VERSION 5.8 ;
BUSBITCHARS "[]" ;
DIVIDERCHAR "/" ;
UNITS
    DATABASE MICRONS 1000 ;
END UNITS

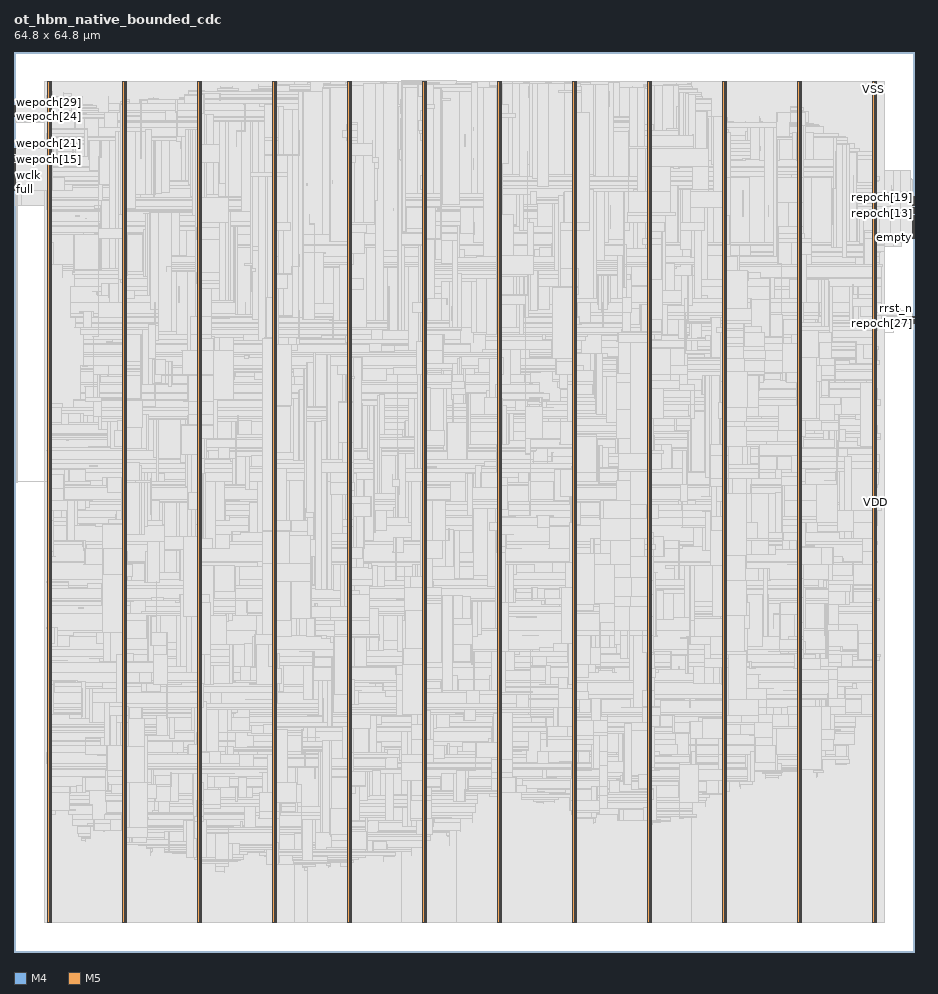
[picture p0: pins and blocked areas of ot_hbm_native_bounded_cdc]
MACRO ot_hbm_native_bounded_cdc
  FOREIGN ot_hbm_native_bounded_cdc 0 0 ;
  CLASS BLOCK ;
  SIZE 64.8 BY 64.8 ;
  PIN empty
    DIRECTION OUTPUT ;
    USE SIGNAL ;
    PORT
      LAYER M4 ;
        RECT  64.716 51.408 64.8 51.432 ;
    END
  END empty
  PIN full
    DIRECTION OUTPUT ;
    USE SIGNAL ;
    PORT
      LAYER M4 ;
        RECT  0 54.864 0.084 54.888 ;
    END
  END full
  PIN r_fault
    DIRECTION OUTPUT ;
    USE SIGNAL ;
    PORT
      LAYER M4 ;
        RECT  64.716 51.504 64.8 51.528 ;
    END
  END r_fault
  PIN rclk
    DIRECTION INPUT ;
    USE SIGNAL ;
    PORT
      LAYER M4 ;
        RECT  64.716 51.6 64.8 51.624 ;
    END
  END rclk
  PIN rd_freed[0]
    DIRECTION OUTPUT ;
    USE SIGNAL ;
    PORT
      LAYER M4 ;
        RECT  0 54.96 0.084 54.984 ;
    END
  END rd_freed[0]
  PIN rd_freed[1]
    DIRECTION OUTPUT ;
    USE SIGNAL ;
    PORT
      LAYER M4 ;
        RECT  0 55.056 0.084 55.08 ;
    END
  END rd_freed[1]
  PIN rd_freed[2]
    DIRECTION OUTPUT ;
    USE SIGNAL ;
    PORT
      LAYER M4 ;
        RECT  0 55.152 0.084 55.176 ;
    END
  END rd_freed[2]
  PIN rdata[0]
    DIRECTION OUTPUT ;
    USE SIGNAL ;
    PORT
      LAYER M4 ;
        RECT  64.716 51.696 64.8 51.72 ;
    END
  END rdata[0]
  PIN re
    DIRECTION INPUT ;
    USE SIGNAL ;
    PORT
      LAYER M4 ;
        RECT  64.716 51.792 64.8 51.816 ;
    END
  END re
  PIN repoch[0]
    DIRECTION INPUT ;
    USE SIGNAL ;
    PORT
      LAYER M4 ;
        RECT  64.716 51.888 64.8 51.912 ;
    END
  END repoch[0]
  PIN repoch[10]
    DIRECTION INPUT ;
    USE SIGNAL ;
    PORT
      LAYER M4 ;
        RECT  64.716 52.848 64.8 52.872 ;
    END
  END repoch[10]
  PIN repoch[11]
    DIRECTION INPUT ;
    USE SIGNAL ;
    PORT
      LAYER M4 ;
        RECT  64.716 52.944 64.8 52.968 ;
    END
  END repoch[11]
  PIN repoch[12]
    DIRECTION INPUT ;
    USE SIGNAL ;
    PORT
      LAYER M4 ;
        RECT  64.716 53.04 64.8 53.064 ;
    END
  END repoch[12]
  PIN repoch[13]
    DIRECTION INPUT ;
    USE SIGNAL ;
    PORT
      LAYER M4 ;
        RECT  64.716 53.136 64.8 53.16 ;
    END
  END repoch[13]
  PIN repoch[14]
    DIRECTION INPUT ;
    USE SIGNAL ;
    PORT
      LAYER M4 ;
        RECT  64.716 53.232 64.8 53.256 ;
    END
  END repoch[14]
  PIN repoch[15]
    DIRECTION INPUT ;
    USE SIGNAL ;
    PORT
      LAYER M4 ;
        RECT  64.716 53.328 64.8 53.352 ;
    END
  END repoch[15]
  PIN repoch[16]
    DIRECTION INPUT ;
    USE SIGNAL ;
    PORT
      LAYER M4 ;
        RECT  64.716 53.424 64.8 53.448 ;
    END
  END repoch[16]
  PIN repoch[17]
    DIRECTION INPUT ;
    USE SIGNAL ;
    PORT
      LAYER M4 ;
        RECT  64.716 53.52 64.8 53.544 ;
    END
  END repoch[17]
  PIN repoch[18]
    DIRECTION INPUT ;
    USE SIGNAL ;
    PORT
      LAYER M4 ;
        RECT  64.716 53.616 64.8 53.64 ;
    END
  END repoch[18]
  PIN repoch[19]
    DIRECTION INPUT ;
    USE SIGNAL ;
    PORT
      LAYER M4 ;
        RECT  64.716 53.712 64.8 53.736 ;
    END
  END repoch[19]
  PIN repoch[1]
    DIRECTION INPUT ;
    USE SIGNAL ;
    PORT
      LAYER M4 ;
        RECT  64.716 51.984 64.8 52.008 ;
    END
  END repoch[1]
  PIN repoch[20]
    DIRECTION INPUT ;
    USE SIGNAL ;
    PORT
      LAYER M4 ;
        RECT  64.716 53.808 64.8 53.832 ;
    END
  END repoch[20]
  PIN repoch[21]
    DIRECTION INPUT ;
    USE SIGNAL ;
    PORT
      LAYER M4 ;
        RECT  64.716 53.904 64.8 53.928 ;
    END
  END repoch[21]
  PIN repoch[22]
    DIRECTION INPUT ;
    USE SIGNAL ;
    PORT
      LAYER M4 ;
        RECT  64.716 54 64.8 54.024 ;
    END
  END repoch[22]
  PIN repoch[23]
    DIRECTION INPUT ;
    USE SIGNAL ;
    PORT
      LAYER M4 ;
        RECT  64.716 54.096 64.8 54.12 ;
    END
  END repoch[23]
  PIN repoch[24]
    DIRECTION INPUT ;
    USE SIGNAL ;
    PORT
      LAYER M4 ;
        RECT  64.716 54.192 64.8 54.216 ;
    END
  END repoch[24]
  PIN repoch[25]
    DIRECTION INPUT ;
    USE SIGNAL ;
    PORT
      LAYER M4 ;
        RECT  64.716 54.288 64.8 54.312 ;
    END
  END repoch[25]
  PIN repoch[26]
    DIRECTION INPUT ;
    USE SIGNAL ;
    PORT
      LAYER M4 ;
        RECT  64.716 54.384 64.8 54.408 ;
    END
  END repoch[26]
  PIN repoch[27]
    DIRECTION INPUT ;
    USE SIGNAL ;
    PORT
      LAYER M4 ;
        RECT  64.716 45.264 64.8 45.288 ;
    END
  END repoch[27]
  PIN repoch[28]
    DIRECTION INPUT ;
    USE SIGNAL ;
    PORT
      LAYER M4 ;
        RECT  64.716 45.36 64.8 45.384 ;
    END
  END repoch[28]
  PIN repoch[29]
    DIRECTION INPUT ;
    USE SIGNAL ;
    PORT
      LAYER M4 ;
        RECT  64.716 45.456 64.8 45.48 ;
    END
  END repoch[29]
  PIN repoch[2]
    DIRECTION INPUT ;
    USE SIGNAL ;
    PORT
      LAYER M4 ;
        RECT  64.716 52.08 64.8 52.104 ;
    END
  END repoch[2]
  PIN repoch[30]
    DIRECTION INPUT ;
    USE SIGNAL ;
    PORT
      LAYER M4 ;
        RECT  64.716 45.552 64.8 45.576 ;
    END
  END repoch[30]
  PIN repoch[31]
    DIRECTION INPUT ;
    USE SIGNAL ;
    PORT
      LAYER M4 ;
        RECT  64.716 45.648 64.8 45.672 ;
    END
  END repoch[31]
  PIN repoch[3]
    DIRECTION INPUT ;
    USE SIGNAL ;
    PORT
      LAYER M4 ;
        RECT  64.716 52.176 64.8 52.2 ;
    END
  END repoch[3]
  PIN repoch[4]
    DIRECTION INPUT ;
    USE SIGNAL ;
    PORT
      LAYER M4 ;
        RECT  64.716 52.272 64.8 52.296 ;
    END
  END repoch[4]
  PIN repoch[5]
    DIRECTION INPUT ;
    USE SIGNAL ;
    PORT
      LAYER M4 ;
        RECT  64.716 52.368 64.8 52.392 ;
    END
  END repoch[5]
  PIN repoch[6]
    DIRECTION INPUT ;
    USE SIGNAL ;
    PORT
      LAYER M4 ;
        RECT  64.716 52.464 64.8 52.488 ;
    END
  END repoch[6]
  PIN repoch[7]
    DIRECTION INPUT ;
    USE SIGNAL ;
    PORT
      LAYER M4 ;
        RECT  64.716 52.56 64.8 52.584 ;
    END
  END repoch[7]
  PIN repoch[8]
    DIRECTION INPUT ;
    USE SIGNAL ;
    PORT
      LAYER M4 ;
        RECT  64.716 52.656 64.8 52.68 ;
    END
  END repoch[8]
  PIN repoch[9]
    DIRECTION INPUT ;
    USE SIGNAL ;
    PORT
      LAYER M4 ;
        RECT  64.716 52.752 64.8 52.776 ;
    END
  END repoch[9]
  PIN rrst_n
    DIRECTION INPUT ;
    USE SIGNAL ;
    PORT
      LAYER M4 ;
        RECT  64.716 45.744 64.8 45.768 ;
    END
  END rrst_n
  PIN w_fault
    DIRECTION OUTPUT ;
    USE SIGNAL ;
    PORT
      LAYER M4 ;
        RECT  0 55.248 0.084 55.272 ;
    END
  END w_fault
  PIN wclk
    DIRECTION INPUT ;
    USE SIGNAL ;
    PORT
      LAYER M4 ;
        RECT  0 55.344 0.084 55.368 ;
    END
  END wclk
  PIN wdata[0]
    DIRECTION INPUT ;
    USE SIGNAL ;
    PORT
      LAYER M4 ;
        RECT  0 55.44 0.084 55.464 ;
    END
  END wdata[0]
  PIN we
    DIRECTION INPUT ;
    USE SIGNAL ;
    PORT
      LAYER M4 ;
        RECT  0 55.536 0.084 55.56 ;
    END
  END we
  PIN wepoch[0]
    DIRECTION INPUT ;
    USE SIGNAL ;
    PORT
      LAYER M4 ;
        RECT  0 55.632 0.084 55.656 ;
    END
  END wepoch[0]
  PIN wepoch[10]
    DIRECTION INPUT ;
    USE SIGNAL ;
    PORT
      LAYER M4 ;
        RECT  0 56.592 0.084 56.616 ;
    END
  END wepoch[10]
  PIN wepoch[11]
    DIRECTION INPUT ;
    USE SIGNAL ;
    PORT
      LAYER M4 ;
        RECT  0 56.688 0.084 56.712 ;
    END
  END wepoch[11]
  PIN wepoch[12]
    DIRECTION INPUT ;
    USE SIGNAL ;
    PORT
      LAYER M4 ;
        RECT  0 56.784 0.084 56.808 ;
    END
  END wepoch[12]
  PIN wepoch[13]
    DIRECTION INPUT ;
    USE SIGNAL ;
    PORT
      LAYER M4 ;
        RECT  0 56.88 0.084 56.904 ;
    END
  END wepoch[13]
  PIN wepoch[14]
    DIRECTION INPUT ;
    USE SIGNAL ;
    PORT
      LAYER M4 ;
        RECT  0 56.976 0.084 57 ;
    END
  END wepoch[14]
  PIN wepoch[15]
    DIRECTION INPUT ;
    USE SIGNAL ;
    PORT
      LAYER M4 ;
        RECT  0 57.072 0.084 57.096 ;
    END
  END wepoch[15]
  PIN wepoch[16]
    DIRECTION INPUT ;
    USE SIGNAL ;
    PORT
      LAYER M4 ;
        RECT  0 57.168 0.084 57.192 ;
    END
  END wepoch[16]
  PIN wepoch[17]
    DIRECTION INPUT ;
    USE SIGNAL ;
    PORT
      LAYER M4 ;
        RECT  0 57.264 0.084 57.288 ;
    END
  END wepoch[17]
  PIN wepoch[18]
    DIRECTION INPUT ;
    USE SIGNAL ;
    PORT
      LAYER M4 ;
        RECT  0 57.36 0.084 57.384 ;
    END
  END wepoch[18]
  PIN wepoch[19]
    DIRECTION INPUT ;
    USE SIGNAL ;
    PORT
      LAYER M4 ;
        RECT  0 57.456 0.084 57.48 ;
    END
  END wepoch[19]
  PIN wepoch[1]
    DIRECTION INPUT ;
    USE SIGNAL ;
    PORT
      LAYER M4 ;
        RECT  0 55.728 0.084 55.752 ;
    END
  END wepoch[1]
  PIN wepoch[20]
    DIRECTION INPUT ;
    USE SIGNAL ;
    PORT
      LAYER M4 ;
        RECT  0 57.552 0.084 57.576 ;
    END
  END wepoch[20]
  PIN wepoch[21]
    DIRECTION INPUT ;
    USE SIGNAL ;
    PORT
      LAYER M4 ;
        RECT  0 57.648 0.084 57.672 ;
    END
  END wepoch[21]
  PIN wepoch[22]
    DIRECTION INPUT ;
    USE SIGNAL ;
    PORT
      LAYER M4 ;
        RECT  0 57.744 0.084 57.768 ;
    END
  END wepoch[22]
  PIN wepoch[23]
    DIRECTION INPUT ;
    USE SIGNAL ;
    PORT
      LAYER M4 ;
        RECT  0 57.84 0.084 57.864 ;
    END
  END wepoch[23]
  PIN wepoch[24]
    DIRECTION INPUT ;
    USE SIGNAL ;
    PORT
      LAYER M4 ;
        RECT  0 60.144 0.084 60.168 ;
    END
  END wepoch[24]
  PIN wepoch[25]
    DIRECTION INPUT ;
    USE SIGNAL ;
    PORT
      LAYER M4 ;
        RECT  0 60.24 0.084 60.264 ;
    END
  END wepoch[25]
  PIN wepoch[26]
    DIRECTION INPUT ;
    USE SIGNAL ;
    PORT
      LAYER M4 ;
        RECT  0 60.336 0.084 60.36 ;
    END
  END wepoch[26]
  PIN wepoch[27]
    DIRECTION INPUT ;
    USE SIGNAL ;
    PORT
      LAYER M4 ;
        RECT  0 60.432 0.084 60.456 ;
    END
  END wepoch[27]
  PIN wepoch[28]
    DIRECTION INPUT ;
    USE SIGNAL ;
    PORT
      LAYER M4 ;
        RECT  0 60.528 0.084 60.552 ;
    END
  END wepoch[28]
  PIN wepoch[29]
    DIRECTION INPUT ;
    USE SIGNAL ;
    PORT
      LAYER M4 ;
        RECT  0 60.624 0.084 60.648 ;
    END
  END wepoch[29]
  PIN wepoch[2]
    DIRECTION INPUT ;
    USE SIGNAL ;
    PORT
      LAYER M4 ;
        RECT  0 55.824 0.084 55.848 ;
    END
  END wepoch[2]
  PIN wepoch[30]
    DIRECTION INPUT ;
    USE SIGNAL ;
    PORT
      LAYER M4 ;
        RECT  0 60.72 0.084 60.744 ;
    END
  END wepoch[30]
  PIN wepoch[31]
    DIRECTION INPUT ;
    USE SIGNAL ;
    PORT
      LAYER M4 ;
        RECT  0 60.816 0.084 60.84 ;
    END
  END wepoch[31]
  PIN wepoch[3]
    DIRECTION INPUT ;
    USE SIGNAL ;
    PORT
      LAYER M4 ;
        RECT  0 55.92 0.084 55.944 ;
    END
  END wepoch[3]
  PIN wepoch[4]
    DIRECTION INPUT ;
    USE SIGNAL ;
    PORT
      LAYER M4 ;
        RECT  0 56.016 0.084 56.04 ;
    END
  END wepoch[4]
  PIN wepoch[5]
    DIRECTION INPUT ;
    USE SIGNAL ;
    PORT
      LAYER M4 ;
        RECT  0 56.112 0.084 56.136 ;
    END
  END wepoch[5]
  PIN wepoch[6]
    DIRECTION INPUT ;
    USE SIGNAL ;
    PORT
      LAYER M4 ;
        RECT  0 56.208 0.084 56.232 ;
    END
  END wepoch[6]
  PIN wepoch[7]
    DIRECTION INPUT ;
    USE SIGNAL ;
    PORT
      LAYER M4 ;
        RECT  0 56.304 0.084 56.328 ;
    END
  END wepoch[7]
  PIN wepoch[8]
    DIRECTION INPUT ;
    USE SIGNAL ;
    PORT
      LAYER M4 ;
        RECT  0 56.4 0.084 56.424 ;
    END
  END wepoch[8]
  PIN wepoch[9]
    DIRECTION INPUT ;
    USE SIGNAL ;
    PORT
      LAYER M4 ;
        RECT  0 56.496 0.084 56.52 ;
    END
  END wepoch[9]
  PIN wrst_n
    DIRECTION INPUT ;
    USE SIGNAL ;
    PORT
      LAYER M4 ;
        RECT  0 60.912 0.084 60.936 ;
    END
  END wrst_n
  PIN VDD
    DIRECTION INOUT ;
    USE POWER ;
    PORT
      LAYER M5 ;
        RECT  61.992 2.151 62.112 62.649 ;
        RECT  56.592 2.151 56.712 62.649 ;
        RECT  51.192 2.151 51.312 62.649 ;
        RECT  45.792 2.151 45.912 62.649 ;
        RECT  40.392 2.151 40.512 62.649 ;
        RECT  34.992 2.151 35.112 62.649 ;
        RECT  29.592 2.151 29.712 62.649 ;
        RECT  24.192 2.151 24.312 62.649 ;
        RECT  18.792 2.151 18.912 62.649 ;
        RECT  13.392 2.151 13.512 62.649 ;
        RECT  7.992 2.151 8.112 62.649 ;
        RECT  2.592 2.151 2.712 62.649 ;
    END
  END VDD
  PIN VSS
    DIRECTION INOUT ;
    USE GROUND ;
    PORT
      LAYER M5 ;
        RECT  61.8 2.137 61.92 62.663 ;
        RECT  56.4 2.137 56.52 62.663 ;
        RECT  51 2.137 51.12 62.663 ;
        RECT  45.6 2.137 45.72 62.663 ;
        RECT  40.2 2.137 40.32 62.663 ;
        RECT  34.8 2.137 34.92 62.663 ;
        RECT  29.4 2.137 29.52 62.663 ;
        RECT  24 2.137 24.12 62.663 ;
        RECT  18.6 2.137 18.72 62.663 ;
        RECT  13.2 2.137 13.32 62.663 ;
        RECT  7.8 2.137 7.92 62.663 ;
        RECT  2.4 2.137 2.52 62.663 ;
    END
  END VSS
  # OT_OBS_CLOSED layer=M5 d_um=1.536 added=353
  OBS
    LAYER RVTN ;
     RECT  2.16 2.16 62.64 2.295 ;
     RECT  2.16 2.565 62.64 2.835 ;
     RECT  2.16 3.105 62.64 3.375 ;
     RECT  2.16 3.645 62.64 3.915 ;
     RECT  2.16 4.185 62.64 4.455 ;
     RECT  2.16 4.725 62.64 4.995 ;
     RECT  2.16 5.265 62.64 5.535 ;
     RECT  2.16 5.805 62.64 6.075 ;
     RECT  2.16 6.345 62.64 6.615 ;
     RECT  2.16 6.885 62.64 7.155 ;
     RECT  2.16 7.425 62.64 7.695 ;
     RECT  2.16 7.965 62.64 8.235 ;
     RECT  2.16 8.505 62.64 8.775 ;
     RECT  2.16 9.045 62.64 9.315 ;
     RECT  2.16 9.585 62.64 9.855 ;
     RECT  2.16 10.125 62.64 10.395 ;
     RECT  2.16 10.665 62.64 10.935 ;
     RECT  2.16 11.205 62.64 11.475 ;
     RECT  2.16 11.745 62.64 12.015 ;
     RECT  2.16 12.285 62.64 12.555 ;
     RECT  2.16 12.825 62.64 13.095 ;
     RECT  2.16 13.365 62.64 13.635 ;
     RECT  2.16 13.905 62.64 14.175 ;
     RECT  2.16 14.445 62.64 14.715 ;
     RECT  2.16 14.985 62.64 15.255 ;
     RECT  2.16 15.525 62.64 15.795 ;
     RECT  2.16 16.065 62.64 16.335 ;
     RECT  2.16 16.605 62.64 16.875 ;
     RECT  2.16 17.145 62.64 17.415 ;
     RECT  2.16 17.685 62.64 17.955 ;
     RECT  2.16 18.225 62.64 18.495 ;
     RECT  2.16 18.765 62.64 19.035 ;
     RECT  2.16 19.305 62.64 19.575 ;
     RECT  2.16 19.845 62.64 20.115 ;
     RECT  2.16 20.385 62.64 20.655 ;
     RECT  2.16 20.925 62.64 21.195 ;
     RECT  2.16 21.465 62.64 21.735 ;
     RECT  2.16 22.005 62.64 22.275 ;
     RECT  2.16 22.545 62.64 22.815 ;
     RECT  2.16 23.085 62.64 23.355 ;
     RECT  2.16 23.625 62.64 23.895 ;
     RECT  2.16 24.165 62.64 24.435 ;
     RECT  2.16 24.705 62.64 24.975 ;
     RECT  2.16 25.245 62.64 25.515 ;
     RECT  2.16 25.785 62.64 26.055 ;
     RECT  2.16 26.325 62.64 26.595 ;
     RECT  2.16 26.865 62.64 27.135 ;
     RECT  2.16 27.405 62.64 27.675 ;
     RECT  2.16 27.945 62.64 28.215 ;
     RECT  2.16 28.485 62.64 28.755 ;
     RECT  2.16 29.025 62.64 29.295 ;
     RECT  2.16 29.565 62.64 29.835 ;
     RECT  2.16 30.105 62.64 30.375 ;
     RECT  2.16 30.645 62.64 30.915 ;
     RECT  2.16 31.185 62.64 31.455 ;
     RECT  2.16 31.725 62.64 31.995 ;
     RECT  2.16 32.265 62.64 32.535 ;
     RECT  2.16 32.805 62.64 33.075 ;
     RECT  2.16 33.345 62.64 33.615 ;
     RECT  2.16 33.885 62.64 34.155 ;
     RECT  2.16 34.425 62.64 34.695 ;
     RECT  2.16 34.965 62.64 35.235 ;
     RECT  2.16 35.505 62.64 35.775 ;
     RECT  2.16 36.045 62.64 36.315 ;
     RECT  2.16 36.585 62.64 36.855 ;
     RECT  2.16 37.125 62.64 37.395 ;
     RECT  2.16 37.665 62.64 37.935 ;
     RECT  2.16 38.205 62.64 38.475 ;
     RECT  2.16 38.745 62.64 39.015 ;
     RECT  2.16 39.285 62.64 39.555 ;
     RECT  2.16 39.825 62.64 40.095 ;
     RECT  2.16 40.365 62.64 40.635 ;
     RECT  2.16 40.905 62.64 41.175 ;
     RECT  2.16 41.445 62.64 41.715 ;
     RECT  2.16 41.985 62.64 42.255 ;
     RECT  2.16 42.525 62.64 42.795 ;
     RECT  2.16 43.065 62.64 43.335 ;
     RECT  2.16 43.605 62.64 43.875 ;
     RECT  2.16 44.145 62.64 44.415 ;
     RECT  2.16 44.685 62.64 44.955 ;
     RECT  2.16 45.225 62.64 45.495 ;
     RECT  2.16 45.765 62.64 46.035 ;
     RECT  2.16 46.305 62.64 46.575 ;
     RECT  2.16 46.845 62.64 47.115 ;
     RECT  2.16 47.385 62.64 47.655 ;
     RECT  2.16 47.925 62.64 48.195 ;
     RECT  2.16 48.465 62.64 48.735 ;
     RECT  2.16 49.005 62.64 49.275 ;
     RECT  2.16 49.545 62.64 49.815 ;
     RECT  2.16 50.085 62.64 50.355 ;
     RECT  2.16 50.625 62.64 50.895 ;
     RECT  2.16 51.165 62.64 51.435 ;
     RECT  2.16 51.705 62.64 51.975 ;
     RECT  2.16 52.245 62.64 52.515 ;
     RECT  2.16 52.785 62.64 53.055 ;
     RECT  2.16 53.325 62.64 53.595 ;
     RECT  2.16 53.865 62.64 54.135 ;
     RECT  2.16 54.405 62.64 54.675 ;
     RECT  2.16 54.945 62.64 55.215 ;
     RECT  2.16 55.485 62.64 55.755 ;
     RECT  2.16 56.025 62.64 56.295 ;
     RECT  2.16 56.565 62.64 56.835 ;
     RECT  2.16 57.105 62.64 57.375 ;
     RECT  2.16 57.645 62.64 57.915 ;
     RECT  2.16 58.185 62.64 58.455 ;
     RECT  2.16 58.725 62.64 58.995 ;
     RECT  2.16 59.265 62.64 59.535 ;
     RECT  2.16 59.805 62.64 60.075 ;
     RECT  2.16 60.345 62.64 60.615 ;
     RECT  2.16 60.885 62.64 61.155 ;
     RECT  2.16 61.425 62.64 61.695 ;
     RECT  2.16 61.965 62.64 62.235 ;
     RECT  2.16 62.505 62.64 62.64 ;
    LAYER RVTP ;
     RECT  2.16 2.295 62.64 2.565 ;
     RECT  2.16 2.835 62.64 3.105 ;
     RECT  2.16 3.375 62.64 3.645 ;
     RECT  2.16 3.915 62.64 4.185 ;
     RECT  2.16 4.455 62.64 4.725 ;
     RECT  2.16 4.995 62.64 5.265 ;
     RECT  2.16 5.535 62.64 5.805 ;
     RECT  2.16 6.075 62.64 6.345 ;
     RECT  2.16 6.615 62.64 6.885 ;
     RECT  2.16 7.155 62.64 7.425 ;
     RECT  2.16 7.695 62.64 7.965 ;
     RECT  2.16 8.235 62.64 8.505 ;
     RECT  2.16 8.775 62.64 9.045 ;
     RECT  2.16 9.315 62.64 9.585 ;
     RECT  2.16 9.855 62.64 10.125 ;
     RECT  2.16 10.395 62.64 10.665 ;
     RECT  2.16 10.935 62.64 11.205 ;
     RECT  2.16 11.475 62.64 11.745 ;
     RECT  2.16 12.015 62.64 12.285 ;
     RECT  2.16 12.555 62.64 12.825 ;
     RECT  2.16 13.095 62.64 13.365 ;
     RECT  2.16 13.635 62.64 13.905 ;
     RECT  2.16 14.175 62.64 14.445 ;
     RECT  2.16 14.715 62.64 14.985 ;
     RECT  2.16 15.255 62.64 15.525 ;
     RECT  2.16 15.795 62.64 16.065 ;
     RECT  2.16 16.335 62.64 16.605 ;
     RECT  2.16 16.875 62.64 17.145 ;
     RECT  2.16 17.415 62.64 17.685 ;
     RECT  2.16 17.955 62.64 18.225 ;
     RECT  2.16 18.495 62.64 18.765 ;
     RECT  2.16 19.035 62.64 19.305 ;
     RECT  2.16 19.575 62.64 19.845 ;
     RECT  2.16 20.115 62.64 20.385 ;
     RECT  2.16 20.655 62.64 20.925 ;
     RECT  2.16 21.195 62.64 21.465 ;
     RECT  2.16 21.735 62.64 22.005 ;
     RECT  2.16 22.275 62.64 22.545 ;
     RECT  2.16 22.815 62.64 23.085 ;
     RECT  2.16 23.355 62.64 23.625 ;
     RECT  2.16 23.895 62.64 24.165 ;
     RECT  2.16 24.435 62.64 24.705 ;
     RECT  2.16 24.975 62.64 25.245 ;
     RECT  2.16 25.515 62.64 25.785 ;
     RECT  2.16 26.055 62.64 26.325 ;
     RECT  2.16 26.595 62.64 26.865 ;
     RECT  2.16 27.135 62.64 27.405 ;
     RECT  2.16 27.675 62.64 27.945 ;
     RECT  2.16 28.215 62.64 28.485 ;
     RECT  2.16 28.755 62.64 29.025 ;
     RECT  2.16 29.295 62.64 29.565 ;
     RECT  2.16 29.835 62.64 30.105 ;
     RECT  2.16 30.375 62.64 30.645 ;
     RECT  2.16 30.915 62.64 31.185 ;
     RECT  2.16 31.455 62.64 31.725 ;
     RECT  2.16 31.995 62.64 32.265 ;
     RECT  2.16 32.535 62.64 32.805 ;
     RECT  2.16 33.075 62.64 33.345 ;
     RECT  2.16 33.615 62.64 33.885 ;
     RECT  2.16 34.155 62.64 34.425 ;
     RECT  2.16 34.695 62.64 34.965 ;
     RECT  2.16 35.235 62.64 35.505 ;
     RECT  2.16 35.775 62.64 36.045 ;
     RECT  2.16 36.315 62.64 36.585 ;
     RECT  2.16 36.855 62.64 37.125 ;
     RECT  2.16 37.395 62.64 37.665 ;
     RECT  2.16 37.935 62.64 38.205 ;
     RECT  2.16 38.475 62.64 38.745 ;
     RECT  2.16 39.015 62.64 39.285 ;
     RECT  2.16 39.555 62.64 39.825 ;
     RECT  2.16 40.095 62.64 40.365 ;
     RECT  2.16 40.635 62.64 40.905 ;
     RECT  2.16 41.175 62.64 41.445 ;
     RECT  2.16 41.715 62.64 41.985 ;
     RECT  2.16 42.255 62.64 42.525 ;
     RECT  2.16 42.795 62.64 43.065 ;
     RECT  2.16 43.335 62.64 43.605 ;
     RECT  2.16 43.875 62.64 44.145 ;
     RECT  2.16 44.415 62.64 44.685 ;
     RECT  2.16 44.955 62.64 45.225 ;
     RECT  2.16 45.495 62.64 45.765 ;
     RECT  2.16 46.035 62.64 46.305 ;
     RECT  2.16 46.575 62.64 46.845 ;
     RECT  2.16 47.115 62.64 47.385 ;
     RECT  2.16 47.655 62.64 47.925 ;
     RECT  2.16 48.195 62.64 48.465 ;
     RECT  2.16 48.735 62.64 49.005 ;
     RECT  2.16 49.275 62.64 49.545 ;
     RECT  2.16 49.815 62.64 50.085 ;
     RECT  2.16 50.355 62.64 50.625 ;
     RECT  2.16 50.895 62.64 51.165 ;
     RECT  2.16 51.435 62.64 51.705 ;
     RECT  2.16 51.975 62.64 52.245 ;
     RECT  2.16 52.515 62.64 52.785 ;
     RECT  2.16 53.055 62.64 53.325 ;
     RECT  2.16 53.595 62.64 53.865 ;
     RECT  2.16 54.135 62.64 54.405 ;
     RECT  2.16 54.675 62.64 54.945 ;
     RECT  2.16 55.215 62.64 55.485 ;
     RECT  2.16 55.755 62.64 56.025 ;
     RECT  2.16 56.295 62.64 56.565 ;
     RECT  2.16 56.835 62.64 57.105 ;
     RECT  2.16 57.375 62.64 57.645 ;
     RECT  2.16 57.915 62.64 58.185 ;
     RECT  2.16 58.455 62.64 58.725 ;
     RECT  2.16 58.995 62.64 59.265 ;
     RECT  2.16 59.535 62.64 59.805 ;
     RECT  2.16 60.075 62.64 60.345 ;
     RECT  2.16 60.615 62.64 60.885 ;
     RECT  2.16 61.155 62.64 61.425 ;
     RECT  2.16 61.695 62.64 61.965 ;
     RECT  2.16 62.235 62.64 62.505 ;
    LAYER M1 ;
     RECT  2.16 2.151 62.64 62.649 ;
    LAYER M2 ;
     RECT  0.103 53.766 0.139 53.784 ;
     RECT  0.139 53.766 0.175 54.504 ;
     RECT  0.103 55.26 0.175 55.71 ;
     RECT  0.103 57.186 0.239 57.204 ;
     RECT  0.175 53.766 0.535 55.71 ;
     RECT  0.103 59.742 0.535 59.76 ;
     RECT  0.535 53.766 2.16 55.854 ;
     RECT  0.535 59.742 2.16 59.832 ;
     RECT  2.16 2.151 18.931 62.649 ;
     RECT  18.931 2.151 20.219 62.694 ;
     RECT  20.219 2.151 21.127 62.649 ;
     RECT  21.127 2.151 27.931 62.694 ;
     RECT  27.931 2.151 31.883 62.766 ;
     RECT  31.883 2.151 48.803 62.694 ;
     RECT  48.803 2.151 62.64 62.649 ;
     RECT  62.64 50.436 62.699 56.286 ;
     RECT  62.64 45.738 63.239 46.368 ;
     RECT  62.64 44.622 63.311 44.64 ;
     RECT  63.239 45.738 63.311 46.296 ;
     RECT  62.699 50.796 63.311 56.286 ;
     RECT  63.311 46.206 63.851 46.296 ;
     RECT  63.311 51.876 63.851 56.286 ;
     RECT  63.311 50.796 63.887 51.12 ;
     RECT  63.851 52.254 63.887 53.01 ;
     RECT  63.887 50.868 63.923 51.12 ;
     RECT  63.887 52.254 63.923 52.272 ;
     RECT  63.923 51.102 63.959 51.12 ;
     RECT  63.851 54.756 64.535 56.286 ;
     RECT  64.535 54.756 64.607 55.674 ;
     RECT  64.607 54.756 64.643 55.584 ;
     RECT  64.643 55.566 64.679 55.584 ;
     RECT  63.851 46.206 64.715 46.224 ;
     RECT  64.615 51.786 64.715 51.804 ;
     RECT  64.643 54.756 64.715 54.774 ;
    LAYER M3 ;
     RECT  2.415 2.143 2.505 2.413 ;
     RECT  7.815 2.143 7.905 2.413 ;
     RECT  13.215 2.143 13.305 2.413 ;
     RECT  18.615 2.143 18.705 2.413 ;
     RECT  24.015 2.143 24.105 2.413 ;
     RECT  29.415 2.143 29.505 2.413 ;
     RECT  34.815 2.143 34.905 2.413 ;
     RECT  40.215 2.143 40.305 2.413 ;
     RECT  45.615 2.143 45.705 2.413 ;
     RECT  51.015 2.143 51.105 2.413 ;
     RECT  56.415 2.143 56.505 2.413 ;
     RECT  61.815 2.143 61.905 2.413 ;
     RECT  15.12 5.701 15.138 5.773 ;
     RECT  14.652 5.773 15.138 5.809 ;
     RECT  20.916 5.845 20.934 5.881 ;
     RECT  20.916 5.881 21.114 6.115 ;
     RECT  14.508 5.809 15.138 6.151 ;
     RECT  20.772 6.115 21.114 6.151 ;
     RECT  22.608 6.115 22.626 6.151 ;
     RECT  24.015 2.413 24.297 6.151 ;
     RECT  22.608 6.151 22.77 6.241 ;
     RECT  20.772 6.151 21.69 6.277 ;
     RECT  18.615 2.413 18.897 6.283 ;
     RECT  13.215 2.413 13.497 6.349 ;
     RECT  13.176 6.349 13.497 6.385 ;
     RECT  14.472 6.151 15.426 6.385 ;
     RECT  20.124 6.277 21.69 6.385 ;
     RECT  22.5 6.241 22.77 6.385 ;
     RECT  18.216 6.283 18.897 6.421 ;
     RECT  20.124 6.385 22.77 6.421 ;
     RECT  23.508 6.151 24.297 6.421 ;
     RECT  13.176 6.385 15.426 6.511 ;
     RECT  13.176 6.511 16.074 6.583 ;
     RECT  20.124 6.421 24.462 6.619 ;
     RECT  13.176 6.583 16.29 6.691 ;
     RECT  18.216 6.421 19.098 6.691 ;
     RECT  20.052 6.619 24.462 6.691 ;
     RECT  12.996 6.691 16.506 6.781 ;
     RECT  20.052 6.691 24.786 6.781 ;
     RECT  18.18 6.691 19.098 6.889 ;
     RECT  26.568 6.547 26.586 6.889 ;
     RECT  27.396 6.853 27.414 6.889 ;
     RECT  18.036 6.889 19.098 6.925 ;
     RECT  20.052 6.781 25.326 6.925 ;
     RECT  26.568 6.889 27.414 6.925 ;
     RECT  18.036 6.925 25.326 6.961 ;
     RECT  26.568 6.925 27.45 6.961 ;
     RECT  12.42 6.781 16.506 7.003 ;
     RECT  12.42 7.003 16.794 7.087 ;
     RECT  9.792 6.925 9.81 7.159 ;
     RECT  11.376 7.087 16.794 7.159 ;
     RECT  10.836 7.159 16.794 7.189 ;
     RECT  10.836 7.189 16.938 7.195 ;
     RECT  17.676 6.961 27.45 7.195 ;
     RECT  9.792 7.159 9.882 7.231 ;
     RECT  10.836 7.195 27.45 7.231 ;
     RECT  28.584 6.961 28.602 7.231 ;
     RECT  10.836 7.231 28.638 7.349 ;
     RECT  9.792 7.231 9.954 7.465 ;
     RECT  9.54 7.465 9.954 7.501 ;
     RECT  10.836 7.349 21.726 7.501 ;
     RECT  22.5 7.349 28.638 7.501 ;
     RECT  29.415 2.413 29.697 7.501 ;
     RECT  22.5 7.501 29.697 7.529 ;
     RECT  9.54 7.501 21.726 7.663 ;
     RECT  9.036 7.663 21.726 7.699 ;
     RECT  7.815 2.413 8.097 7.771 ;
     RECT  8.964 7.699 21.726 7.771 ;
     RECT  22.824 7.529 29.697 8.005 ;
     RECT  5.112 7.933 5.13 8.041 ;
     RECT  4.86 8.041 5.13 8.203 ;
     RECT  4.86 8.203 5.526 8.239 ;
     RECT  31.32 7.699 31.338 8.239 ;
     RECT  4.824 8.239 5.526 8.311 ;
     RECT  22.824 8.005 30.006 8.311 ;
     RECT  31.32 8.239 31.374 8.311 ;
     RECT  31.212 8.311 31.374 8.401 ;
     RECT  22.788 8.311 30.006 8.437 ;
     RECT  4.608 8.311 5.526 8.545 ;
     RECT  7.815 7.771 21.726 8.581 ;
     RECT  22.788 8.437 30.114 8.581 ;
     RECT  31.14 8.401 31.374 8.581 ;
     RECT  7.776 8.581 31.374 8.609 ;
     RECT  26.136 8.609 31.374 8.699 ;
     RECT  6.408 8.707 6.534 8.779 ;
     RECT  26.244 8.699 31.374 8.779 ;
     RECT  32.112 8.707 32.13 8.779 ;
     RECT  6.264 8.779 6.534 8.851 ;
     RECT  7.776 8.609 25.398 8.851 ;
     RECT  6.264 8.851 25.398 8.969 ;
     RECT  17.388 8.969 25.398 9.005 ;
     RECT  4.536 8.545 5.526 9.013 ;
     RECT  6.264 8.969 16.614 9.013 ;
     RECT  4.536 9.013 16.614 9.121 ;
     RECT  45.615 2.413 45.897 9.211 ;
     RECT  26.244 8.779 32.13 9.319 ;
     RECT  41.724 9.283 41.742 9.355 ;
     RECT  45.615 9.211 45.954 9.355 ;
     RECT  23.976 9.005 25.398 9.391 ;
     RECT  45.615 9.355 46.53 9.391 ;
     RECT  45.615 9.391 47.286 9.499 ;
     RECT  4.212 9.121 16.614 9.509 ;
     RECT  26.244 9.319 32.166 9.589 ;
     RECT  33.012 9.355 33.03 9.589 ;
     RECT  40.215 2.413 40.497 9.625 ;
     RECT  41.724 9.355 41.886 9.625 ;
     RECT  23.976 9.391 25.506 9.643 ;
     RECT  26.244 9.589 33.03 9.643 ;
     RECT  43.56 9.499 43.578 9.661 ;
     RECT  45.18 9.499 47.286 9.661 ;
     RECT  48.204 9.625 48.222 9.661 ;
     RECT  40.215 9.625 41.886 9.691 ;
     RECT  43.56 9.661 47.286 9.751 ;
     RECT  48.204 9.661 49.158 9.751 ;
     RECT  17.388 9.005 23.202 9.823 ;
     RECT  23.976 9.643 33.03 9.823 ;
     RECT  6.516 9.509 16.614 9.887 ;
     RECT  2.415 2.413 2.697 9.895 ;
     RECT  43.56 9.751 49.158 9.923 ;
     RECT  4.212 9.509 5.634 9.931 ;
     RECT  40.215 9.691 41.958 9.931 ;
     RECT  6.588 9.887 16.614 9.959 ;
     RECT  17.388 9.823 33.03 10.021 ;
     RECT  6.624 9.959 16.614 10.049 ;
     RECT  40.14 9.931 42.714 10.093 ;
     RECT  43.56 9.923 48.834 10.093 ;
     RECT  9.972 10.049 10.422 10.157 ;
     RECT  40.14 10.093 48.834 10.165 ;
     RECT  2.415 9.895 2.97 10.253 ;
     RECT  39.996 10.165 48.834 10.363 ;
     RECT  11.196 10.049 16.614 10.471 ;
     RECT  17.352 10.021 33.246 10.471 ;
     RECT  3.888 9.931 5.634 10.561 ;
     RECT  3.816 10.561 5.634 10.625 ;
     RECT  3.816 10.625 5.454 10.669 ;
     RECT  11.196 10.471 33.246 10.669 ;
     RECT  38.088 10.705 38.106 10.741 ;
     RECT  39.96 10.363 48.834 10.741 ;
     RECT  49.752 10.471 49.77 10.741 ;
     RECT  6.624 10.049 9.234 10.831 ;
     RECT  37.62 10.741 38.106 10.831 ;
     RECT  38.88 10.741 38.898 10.831 ;
     RECT  37.62 10.831 38.898 10.867 ;
     RECT  6.588 10.831 9.234 10.903 ;
     RECT  34.815 2.413 35.097 10.903 ;
     RECT  39.96 10.741 49.77 10.939 ;
     RECT  3.744 10.669 5.454 11.011 ;
     RECT  10.08 10.157 10.422 11.011 ;
     RECT  11.196 10.669 33.39 11.011 ;
     RECT  37.368 10.867 38.898 11.011 ;
     RECT  36.504 11.011 39.186 11.101 ;
     RECT  39.96 10.939 49.878 11.101 ;
     RECT  36.504 11.101 49.878 11.137 ;
     RECT  34.776 10.903 35.097 11.209 ;
     RECT  6.588 10.903 9.306 11.245 ;
     RECT  3.6 11.011 5.454 11.275 ;
     RECT  6.552 11.245 9.306 11.281 ;
     RECT  10.08 11.011 33.39 11.281 ;
     RECT  36.504 11.137 50.094 11.371 ;
     RECT  51.015 2.413 51.297 11.371 ;
     RECT  6.552 11.281 33.39 11.443 ;
     RECT  34.2 11.209 35.097 11.443 ;
     RECT  36.504 11.371 51.297 11.507 ;
     RECT  36.504 11.507 42.858 11.509 ;
     RECT  2.415 10.253 2.697 11.551 ;
     RECT  3.456 11.275 5.454 11.551 ;
     RECT  6.552 11.443 35.097 11.551 ;
     RECT  43.596 11.507 51.297 11.551 ;
     RECT  2.415 11.551 5.454 11.641 ;
     RECT  6.552 11.551 35.19 11.641 ;
     RECT  36.108 11.509 42.858 11.669 ;
     RECT  2.415 11.641 35.19 11.705 ;
     RECT  15.516 11.705 35.19 11.713 ;
     RECT  36.468 11.669 42.858 11.741 ;
     RECT  2.415 11.705 14.706 11.813 ;
     RECT  2.415 11.813 14.526 11.849 ;
     RECT  15.516 11.713 35.262 11.947 ;
     RECT  52.272 11.749 52.29 11.947 ;
     RECT  52.236 11.947 52.29 12.091 ;
     RECT  52.236 12.091 53.19 12.245 ;
     RECT  43.596 11.551 51.498 12.253 ;
     RECT  52.236 12.245 53.118 12.253 ;
     RECT  36.576 11.741 42.858 12.361 ;
     RECT  43.596 12.253 53.118 12.361 ;
     RECT  15.516 11.947 35.694 12.523 ;
     RECT  36.576 12.361 53.118 12.523 ;
     RECT  54.108 12.523 54.126 12.559 ;
     RECT  55.008 12.487 55.026 12.559 ;
     RECT  2.415 11.849 14.454 12.631 ;
     RECT  15.516 12.523 53.118 12.631 ;
     RECT  56.415 2.413 56.697 12.631 ;
     RECT  57.744 12.559 57.762 12.631 ;
     RECT  54.108 12.559 55.026 12.721 ;
     RECT  54.108 12.721 55.242 12.865 ;
     RECT  53.892 12.865 55.242 12.901 ;
     RECT  57.744 12.631 57.834 12.901 ;
     RECT  53.892 12.901 55.314 13.027 ;
     RECT  56.376 12.631 56.697 13.027 ;
     RECT  57.564 12.901 58.266 13.055 ;
     RECT  2.415 12.631 53.118 13.171 ;
     RECT  53.892 13.027 56.697 13.171 ;
     RECT  2.415 13.171 56.697 13.199 ;
     RECT  27.576 13.199 56.697 13.277 ;
     RECT  27.576 13.277 53.154 13.289 ;
     RECT  2.415 13.199 26.73 13.361 ;
     RECT  57.564 13.055 58.194 13.405 ;
     RECT  53.892 13.277 56.697 13.441 ;
     RECT  57.492 13.405 58.194 13.441 ;
     RECT  2.415 13.361 16.218 13.559 ;
     RECT  27.576 13.289 53.082 13.559 ;
     RECT  2.415 13.559 14.094 13.603 ;
     RECT  59.112 13.531 59.958 13.603 ;
     RECT  27.576 13.559 37.71 13.631 ;
     RECT  38.448 13.559 53.082 13.631 ;
     RECT  59.112 13.603 60.174 13.829 ;
     RECT  53.892 13.441 58.194 13.873 ;
     RECT  59.112 13.829 60.102 13.873 ;
     RECT  17.244 13.361 26.73 13.945 ;
     RECT  17.244 13.945 26.802 13.981 ;
     RECT  27.576 13.631 36.918 13.981 ;
     RECT  41.436 13.631 53.082 14.071 ;
     RECT  53.892 13.873 60.102 14.071 ;
     RECT  41.436 14.071 60.102 14.099 ;
     RECT  41.436 14.099 59.13 14.207 ;
     RECT  41.436 14.207 47.754 14.243 ;
     RECT  14.832 13.559 16.218 14.251 ;
     RECT  17.244 13.981 36.918 14.251 ;
     RECT  2.34 13.603 14.094 14.369 ;
     RECT  2.376 14.369 14.094 14.381 ;
     RECT  37.656 13.631 37.71 14.413 ;
     RECT  38.448 13.631 40.662 14.413 ;
     RECT  41.436 14.243 42.606 14.413 ;
     RECT  37.656 14.413 42.606 14.441 ;
     RECT  14.832 14.251 36.918 14.521 ;
     RECT  12.168 14.381 14.094 14.611 ;
     RECT  14.832 14.521 37.062 14.611 ;
     RECT  12.168 14.611 37.062 14.747 ;
     RECT  16.776 14.747 37.062 14.783 ;
     RECT  16.812 14.783 37.062 14.819 ;
     RECT  48.528 14.207 59.13 14.881 ;
     RECT  59.904 14.099 60.102 14.881 ;
     RECT  43.38 14.243 47.754 14.909 ;
     RECT  48.528 14.881 60.102 14.953 ;
     RECT  2.376 14.381 11.43 15.151 ;
     RECT  12.168 14.747 15.966 15.151 ;
     RECT  17.244 14.819 37.062 15.179 ;
     RECT  2.376 15.151 15.966 15.215 ;
     RECT  37.872 14.441 42.606 15.331 ;
     RECT  43.38 14.909 47.61 15.331 ;
     RECT  17.244 15.179 20.79 15.565 ;
     RECT  37.872 15.331 47.61 15.727 ;
     RECT  48.528 14.953 60.534 15.727 ;
     RECT  2.415 15.215 15.966 15.799 ;
     RECT  16.776 15.565 20.79 15.799 ;
     RECT  21.708 15.179 37.062 15.871 ;
     RECT  37.872 15.727 60.534 15.871 ;
     RECT  2.415 15.799 20.79 15.961 ;
     RECT  2.415 15.961 20.826 16.141 ;
     RECT  21.708 15.871 60.534 16.141 ;
     RECT  2.415 16.141 60.606 16.259 ;
     RECT  2.415 16.259 15.966 16.403 ;
     RECT  16.776 16.259 60.606 16.529 ;
     RECT  16.92 16.529 60.606 16.951 ;
     RECT  61.815 2.413 62.097 16.951 ;
     RECT  16.92 16.951 62.097 17.105 ;
     RECT  2.415 16.403 15.786 17.149 ;
     RECT  16.92 17.105 61.038 17.213 ;
     RECT  2.415 17.149 15.93 17.221 ;
     RECT  2.415 17.221 16.074 17.491 ;
     RECT  16.92 17.213 40.734 17.491 ;
     RECT  2.415 17.491 40.734 17.609 ;
     RECT  2.415 17.609 36.198 17.879 ;
     RECT  14.904 17.879 32.706 17.915 ;
     RECT  37.008 17.609 40.734 18.187 ;
     RECT  41.508 17.213 61.038 18.187 ;
     RECT  37.008 18.187 61.038 18.257 ;
     RECT  33.516 17.879 36.198 18.571 ;
     RECT  37.008 18.257 40.497 18.571 ;
     RECT  41.292 18.257 61.038 18.571 ;
     RECT  61.815 17.105 62.097 18.571 ;
     RECT  2.415 17.879 14.166 18.661 ;
     RECT  14.904 17.915 32.598 18.661 ;
     RECT  33.516 18.571 40.497 19.075 ;
     RECT  2.415 18.661 32.598 19.111 ;
     RECT  33.48 19.075 40.497 19.111 ;
     RECT  2.415 19.111 40.497 19.373 ;
     RECT  9.864 19.373 40.497 19.381 ;
     RECT  41.292 18.571 62.097 19.381 ;
     RECT  9.864 19.381 62.097 19.535 ;
     RECT  2.415 19.373 9.054 20.155 ;
     RECT  9.864 19.535 16.29 20.155 ;
     RECT  17.028 19.535 62.097 20.489 ;
     RECT  38.304 20.489 62.097 20.579 ;
     RECT  2.415 20.155 16.29 20.821 ;
     RECT  17.028 20.489 37.35 20.821 ;
     RECT  38.304 20.579 59.562 20.849 ;
     RECT  60.336 20.579 62.097 21.001 ;
     RECT  2.415 20.821 37.35 21.271 ;
     RECT  38.304 20.849 40.77 21.271 ;
     RECT  60.336 21.001 62.298 21.271 ;
     RECT  60.336 21.271 62.406 21.389 ;
     RECT  41.508 20.849 59.562 21.397 ;
     RECT  60.336 21.389 62.298 21.397 ;
     RECT  41.508 21.397 62.298 21.425 ;
     RECT  2.415 21.271 40.77 21.775 ;
     RECT  41.508 21.425 62.097 21.775 ;
     RECT  2.415 21.775 62.097 23.125 ;
     RECT  2.376 23.125 62.097 24.359 ;
     RECT  9.18 24.359 62.097 24.539 ;
     RECT  9.468 24.539 62.097 24.899 ;
     RECT  2.376 24.359 8.406 24.971 ;
     RECT  2.415 24.971 8.406 25.249 ;
     RECT  2.415 25.249 8.586 25.285 ;
     RECT  9.468 24.899 39.258 25.285 ;
     RECT  39.996 24.899 62.097 25.321 ;
     RECT  2.415 25.285 39.258 25.439 ;
     RECT  39.996 25.321 62.298 25.475 ;
     RECT  38.16 25.439 39.258 26.131 ;
     RECT  39.996 25.475 62.097 26.131 ;
     RECT  2.415 25.439 37.314 26.203 ;
     RECT  38.16 26.131 62.097 26.203 ;
     RECT  2.415 26.203 62.097 26.401 ;
     RECT  2.376 26.401 62.097 26.789 ;
     RECT  2.415 26.789 62.097 28.021 ;
     RECT  2.415 28.021 62.154 28.139 ;
     RECT  2.415 28.139 62.097 29.371 ;
     RECT  2.415 29.371 62.154 29.561 ;
     RECT  2.415 29.561 62.097 30.721 ;
     RECT  2.415 30.721 62.154 31.253 ;
     RECT  3.42 31.253 62.154 31.793 ;
     RECT  3.564 31.793 62.154 31.801 ;
     RECT  3.564 31.801 62.442 32.189 ;
     RECT  3.564 32.189 62.298 32.225 ;
     RECT  3.564 32.225 62.262 32.459 ;
     RECT  3.6 32.459 62.262 32.567 ;
     RECT  3.6 32.567 62.097 33.421 ;
     RECT  3.6 33.421 62.154 33.583 ;
     RECT  2.415 31.253 2.697 33.691 ;
     RECT  3.42 33.583 62.154 33.691 ;
     RECT  2.415 33.691 62.226 34.501 ;
     RECT  2.415 34.501 62.334 34.781 ;
     RECT  2.415 34.781 54.702 35.159 ;
     RECT  55.476 34.781 62.334 35.339 ;
     RECT  2.415 35.159 37.422 35.429 ;
     RECT  38.376 35.159 54.702 35.659 ;
     RECT  55.476 35.339 59.238 35.659 ;
     RECT  59.976 35.339 62.334 35.843 ;
     RECT  15.48 35.429 37.422 36.013 ;
     RECT  15.48 36.013 37.566 36.085 ;
     RECT  2.415 35.429 14.706 36.091 ;
     RECT  38.376 35.659 59.238 36.247 ;
     RECT  59.976 35.843 62.097 36.247 ;
     RECT  15.48 36.085 37.638 36.283 ;
     RECT  38.376 36.247 62.097 36.283 ;
     RECT  2.376 36.091 14.706 36.319 ;
     RECT  15.48 36.283 62.097 36.319 ;
     RECT  2.376 36.319 62.097 36.931 ;
     RECT  2.376 36.931 62.406 37.049 ;
     RECT  2.376 37.049 14.634 37.157 ;
     RECT  2.376 37.157 14.598 37.229 ;
     RECT  15.372 37.049 62.406 37.319 ;
     RECT  2.376 37.229 14.418 37.355 ;
     RECT  15.372 37.319 62.154 37.355 ;
     RECT  39.168 37.355 62.154 37.499 ;
     RECT  39.348 37.499 62.154 37.895 ;
     RECT  2.415 37.355 14.418 38.011 ;
     RECT  15.912 37.355 38.394 38.101 ;
     RECT  2.415 38.011 14.922 38.155 ;
     RECT  15.912 38.101 38.502 38.155 ;
     RECT  2.415 38.155 38.502 38.443 ;
     RECT  39.348 37.895 62.097 38.443 ;
     RECT  2.415 38.443 62.097 38.543 ;
     RECT  2.415 38.543 37.098 38.975 ;
     RECT  37.836 38.543 62.097 39.011 ;
     RECT  2.415 38.975 36.126 39.209 ;
     RECT  50.832 39.011 62.097 39.361 ;
     RECT  36.972 38.975 37.098 39.451 ;
     RECT  37.836 39.011 49.986 39.451 ;
     RECT  2.415 39.209 3.51 39.479 ;
     RECT  36.972 39.451 49.986 39.623 ;
     RECT  4.284 39.209 36.126 39.721 ;
     RECT  36.972 39.623 38.538 39.721 ;
     RECT  50.832 39.361 62.37 39.749 ;
     RECT  4.284 39.721 38.538 39.785 ;
     RECT  50.832 39.749 62.262 39.785 ;
     RECT  50.832 39.785 62.154 39.793 ;
     RECT  39.312 39.623 49.986 39.901 ;
     RECT  50.724 39.793 62.154 39.901 ;
     RECT  4.788 39.785 38.538 40.199 ;
     RECT  4.788 40.199 38.106 40.289 ;
     RECT  39.312 39.901 62.154 40.469 ;
     RECT  39.312 40.469 51.534 40.567 ;
     RECT  52.308 40.469 62.154 40.595 ;
     RECT  39.276 40.567 51.534 40.675 ;
     RECT  4.788 40.289 37.818 40.829 ;
     RECT  4.788 40.829 19.854 41.009 ;
     RECT  20.844 40.829 37.818 41.009 ;
     RECT  39.132 40.675 51.534 41.071 ;
     RECT  38.772 41.071 51.534 41.215 ;
     RECT  52.308 40.595 62.097 41.215 ;
     RECT  20.844 41.009 37.206 41.563 ;
     RECT  20.736 41.563 37.206 41.755 ;
     RECT  4.788 41.009 19.782 41.791 ;
     RECT  20.592 41.755 37.89 41.791 ;
     RECT  38.772 41.215 62.097 41.791 ;
     RECT  4.788 41.791 62.097 41.945 ;
     RECT  4.788 41.945 39.438 42.017 ;
     RECT  4.788 42.017 39.402 42.215 ;
     RECT  40.215 41.945 62.097 42.331 ;
     RECT  40.215 42.331 62.334 42.557 ;
     RECT  40.215 42.557 62.154 42.719 ;
     RECT  40.215 42.719 41.526 42.755 ;
     RECT  42.264 42.719 62.154 42.797 ;
     RECT  4.968 42.215 39.402 42.871 ;
     RECT  40.215 42.755 41.49 42.871 ;
     RECT  4.968 42.871 41.49 42.989 ;
     RECT  4.968 42.989 41.346 43.025 ;
     RECT  4.968 43.025 40.878 43.169 ;
     RECT  44.496 42.797 62.154 43.331 ;
     RECT  33.696 43.169 40.878 43.367 ;
     RECT  49.212 43.331 62.154 43.411 ;
     RECT  42.264 42.797 43.722 43.537 ;
     RECT  44.496 43.331 48.402 43.537 ;
     RECT  49.212 43.411 62.226 43.565 ;
     RECT  4.968 43.169 32.886 43.709 ;
     RECT  5.004 43.709 32.886 43.835 ;
     RECT  33.912 43.367 40.878 44.041 ;
     RECT  42.264 43.537 48.402 44.059 ;
     RECT  5.004 43.835 32.166 44.069 ;
     RECT  49.212 43.565 62.097 44.249 ;
     RECT  33.912 44.041 41.166 44.347 ;
     RECT  42.264 44.059 48.474 44.419 ;
     RECT  33.084 43.915 33.102 44.455 ;
     RECT  33.912 44.347 41.31 44.455 ;
     RECT  5.004 44.069 25.722 44.491 ;
     RECT  33.084 44.455 41.31 44.491 ;
     RECT  42.264 44.419 48.618 44.491 ;
     RECT  33.084 44.491 48.618 44.581 ;
     RECT  26.532 44.069 32.166 44.725 ;
     RECT  49.5 44.249 62.097 44.761 ;
     RECT  4.788 44.491 25.722 44.851 ;
     RECT  26.532 44.725 32.238 44.851 ;
     RECT  4.788 44.851 32.238 44.959 ;
     RECT  32.976 44.581 48.618 44.959 ;
     RECT  4.788 44.959 48.618 44.971 ;
     RECT  49.5 44.761 62.19 45.031 ;
     RECT  4.392 44.971 48.618 45.229 ;
     RECT  49.5 45.031 62.226 45.229 ;
     RECT  63.288 44.617 63.306 45.259 ;
     RECT  4.392 45.229 62.226 45.265 ;
     RECT  4.392 45.265 62.442 45.329 ;
     RECT  63.252 45.259 63.306 45.355 ;
     RECT  63.252 45.355 63.846 45.547 ;
     RECT  4.392 45.329 40.734 45.697 ;
     RECT  4.068 45.697 40.734 45.725 ;
     RECT  41.472 45.329 62.442 45.841 ;
     RECT  63.216 45.547 63.846 45.841 ;
     RECT  4.068 45.725 40.59 45.959 ;
     RECT  41.472 45.841 63.846 46.031 ;
     RECT  64.692 45.643 64.71 46.229 ;
     RECT  63.18 46.031 63.846 46.301 ;
     RECT  63.18 46.301 63.234 46.337 ;
     RECT  63.216 46.337 63.234 46.373 ;
     RECT  4.068 45.959 40.554 46.741 ;
     RECT  4.068 46.741 40.734 46.777 ;
     RECT  41.472 46.031 62.442 46.777 ;
     RECT  4.068 46.777 62.442 47.885 ;
     RECT  4.356 47.885 62.442 48.461 ;
     RECT  48.384 48.461 62.442 48.467 ;
     RECT  48.528 48.467 62.442 48.533 ;
     RECT  4.356 48.461 47.43 48.811 ;
     RECT  3.456 48.541 3.474 49.081 ;
     RECT  4.212 48.811 47.43 49.081 ;
     RECT  3.456 49.081 47.43 49.243 ;
     RECT  3.456 49.243 47.718 49.351 ;
     RECT  48.816 48.533 62.442 49.351 ;
     RECT  48.816 49.351 62.514 49.469 ;
     RECT  3.456 49.351 48.006 49.477 ;
     RECT  48.816 49.469 62.334 49.477 ;
     RECT  2.415 39.479 2.697 49.621 ;
     RECT  3.456 49.477 62.334 49.621 ;
     RECT  2.415 49.621 62.334 50.093 ;
     RECT  53.028 50.093 62.334 50.395 ;
     RECT  53.028 50.395 62.37 50.431 ;
     RECT  2.415 50.093 52.254 50.863 ;
     RECT  53.028 50.431 62.694 50.863 ;
     RECT  63.864 50.791 63.882 50.863 ;
     RECT  2.415 50.863 62.694 50.963 ;
     RECT  63.864 50.863 63.918 51.097 ;
     RECT  63.864 51.097 63.954 51.691 ;
     RECT  5.94 50.963 62.694 51.709 ;
     RECT  63.828 51.691 63.954 51.739 ;
     RECT  5.796 51.709 62.694 51.745 ;
     RECT  63.828 51.739 64.638 51.745 ;
     RECT  2.415 50.963 4.986 51.781 ;
     RECT  5.796 51.745 64.638 51.781 ;
     RECT  2.415 51.781 64.71 51.809 ;
     RECT  64.692 51.809 64.71 51.821 ;
     RECT  2.415 51.809 63.954 52.205 ;
     RECT  2.415 52.205 63.918 52.313 ;
     RECT  63.828 52.313 63.918 52.493 ;
     RECT  2.415 52.313 62.73 52.589 ;
     RECT  63.828 52.493 63.882 53.165 ;
     RECT  2.415 52.589 62.694 53.323 ;
     RECT  63.828 53.165 63.846 53.323 ;
     RECT  2.415 53.323 63.846 53.401 ;
     RECT  2.376 53.401 63.846 53.491 ;
     RECT  2.34 53.491 63.846 53.671 ;
     RECT  64.692 53.035 64.71 53.707 ;
     RECT  64.656 53.707 64.71 53.899 ;
     RECT  64.62 53.899 64.71 53.995 ;
     RECT  2.304 53.671 63.846 54.095 ;
     RECT  2.34 54.095 63.846 54.167 ;
     RECT  55.98 54.167 63.846 54.187 ;
     RECT  64.584 53.995 64.71 54.187 ;
     RECT  2.34 54.167 55.17 54.329 ;
     RECT  55.98 54.187 64.71 54.365 ;
     RECT  0.108 53.761 0.126 54.481 ;
     RECT  0.108 54.481 0.162 54.607 ;
     RECT  55.98 54.365 63.234 54.707 ;
     RECT  64.512 54.365 64.71 54.779 ;
     RECT  63.18 54.707 63.234 54.905 ;
     RECT  0.108 54.607 0.198 54.985 ;
     RECT  9.108 54.329 55.17 54.985 ;
     RECT  55.98 54.707 62.097 54.985 ;
     RECT  2.34 54.329 8.334 55.051 ;
     RECT  63.18 54.905 63.198 55.175 ;
     RECT  2.304 55.051 8.334 55.219 ;
     RECT  9.108 54.985 62.097 55.219 ;
     RECT  2.304 55.219 62.097 55.453 ;
     RECT  2.304 55.453 62.262 55.561 ;
     RECT  64.512 54.779 64.674 55.589 ;
     RECT  64.512 55.589 64.602 55.679 ;
     RECT  2.304 55.561 62.298 55.823 ;
     RECT  0.108 54.985 0.234 55.831 ;
     RECT  2.304 55.823 62.262 55.859 ;
     RECT  0.108 55.831 0.558 55.949 ;
     RECT  0.54 55.949 0.558 56.045 ;
     RECT  2.304 55.859 62.097 56.203 ;
     RECT  64.512 55.679 64.53 56.291 ;
     RECT  2.268 56.203 62.097 56.491 ;
     RECT  2.232 56.491 62.097 56.561 ;
     RECT  0.216 57.115 0.234 57.163 ;
     RECT  0.144 57.163 0.234 57.181 ;
     RECT  0.108 57.181 0.234 57.259 ;
     RECT  2.232 56.561 59.022 57.379 ;
     RECT  59.832 56.561 62.097 57.379 ;
     RECT  0.108 57.259 0.342 57.389 ;
     RECT  0.108 57.389 0.234 57.485 ;
     RECT  0.216 57.485 0.234 57.533 ;
     RECT  2.232 57.379 62.097 57.605 ;
     RECT  2.232 57.605 60.858 57.839 ;
     RECT  2.232 57.839 60.534 57.875 ;
     RECT  2.268 57.875 60.534 58.217 ;
     RECT  2.268 58.217 59.994 58.415 ;
     RECT  2.34 58.415 59.994 58.649 ;
     RECT  2.34 58.649 59.886 58.685 ;
     RECT  2.34 58.685 54.918 58.721 ;
     RECT  55.8 58.685 59.346 58.919 ;
     RECT  2.34 58.721 5.274 58.955 ;
     RECT  55.8 58.919 59.238 58.955 ;
     RECT  2.376 58.955 5.274 59.189 ;
     RECT  2.412 59.189 5.274 59.261 ;
     RECT  6.084 58.721 54.918 59.369 ;
     RECT  55.8 58.955 58.302 59.459 ;
     RECT  55.8 59.459 57.978 59.495 ;
     RECT  55.8 59.495 57.906 59.603 ;
     RECT  55.8 59.603 57.582 59.639 ;
     RECT  7.452 59.369 54.918 59.729 ;
     RECT  55.8 59.639 57.186 59.729 ;
     RECT  7.452 59.729 51.822 59.765 ;
     RECT  52.632 59.729 52.65 59.765 ;
     RECT  53.64 59.729 53.91 59.801 ;
     RECT  0.108 59.737 0.126 59.809 ;
     RECT  7.452 59.765 51.354 59.837 ;
     RECT  54.9 59.729 54.918 59.837 ;
     RECT  2.412 59.261 5.094 59.995 ;
     RECT  6.084 59.369 6.534 59.995 ;
     RECT  53.64 59.801 53.766 60.035 ;
     RECT  11.7 59.837 51.354 60.071 ;
     RECT  2.412 59.995 6.534 60.115 ;
     RECT  11.7 60.071 51.297 60.179 ;
     RECT  53.64 60.035 53.658 60.179 ;
     RECT  0.108 59.809 0.558 60.269 ;
     RECT  2.304 60.115 6.534 60.269 ;
     RECT  3.996 60.269 6.534 60.427 ;
     RECT  7.452 59.837 10.926 60.427 ;
     RECT  0.54 60.269 0.558 60.461 ;
     RECT  3.996 60.427 10.926 60.461 ;
     RECT  55.872 59.729 57.186 60.539 ;
     RECT  3.996 60.461 6.066 60.575 ;
     RECT  55.872 60.539 56.862 60.575 ;
     RECT  6.804 60.461 10.926 60.619 ;
     RECT  11.7 60.179 50.202 60.619 ;
     RECT  4.608 60.575 6.066 60.719 ;
     RECT  4.608 60.719 5.922 60.809 ;
     RECT  55.872 60.575 56.826 60.809 ;
     RECT  55.872 60.809 56.697 60.845 ;
     RECT  4.644 60.809 5.922 60.917 ;
     RECT  4.644 60.917 5.67 60.989 ;
     RECT  6.804 60.619 50.202 61.079 ;
     RECT  7.632 61.079 50.202 61.115 ;
     RECT  2.304 60.269 3.222 61.195 ;
     RECT  4.644 60.989 4.95 61.229 ;
     RECT  7.632 61.115 8.298 61.259 ;
     RECT  7.815 61.259 8.298 61.349 ;
     RECT  9.036 61.115 50.202 61.349 ;
     RECT  9.432 61.349 50.202 61.373 ;
     RECT  9.432 61.373 10.854 61.385 ;
     RECT  11.664 61.373 50.202 61.385 ;
     RECT  9.648 61.385 10.386 61.421 ;
     RECT  11.88 61.385 50.202 61.457 ;
     RECT  10.008 61.421 10.026 61.529 ;
     RECT  11.88 61.457 21.366 61.529 ;
     RECT  2.304 61.195 3.87 61.619 ;
     RECT  4.932 61.229 4.95 61.619 ;
     RECT  6.804 61.079 6.822 61.619 ;
     RECT  38.988 61.457 49.554 61.619 ;
     RECT  3.564 61.619 3.87 61.627 ;
     RECT  2.304 61.619 2.79 61.655 ;
     RECT  22.104 61.457 38.25 61.655 ;
     RECT  12.276 61.529 21.366 61.714 ;
     RECT  3.564 61.627 4.158 61.799 ;
     RECT  3.564 61.799 3.582 61.889 ;
     RECT  38.988 61.619 49.482 61.889 ;
     RECT  2.415 61.655 2.79 61.925 ;
     RECT  12.564 61.714 21.366 61.925 ;
     RECT  12.564 61.925 16.146 61.961 ;
     RECT  12.564 61.961 13.698 61.997 ;
     RECT  14.616 61.961 16.146 61.997 ;
     RECT  13.215 61.997 13.698 62.033 ;
     RECT  17.1 61.925 21.366 62.033 ;
     RECT  17.1 62.033 21.33 62.069 ;
     RECT  38.988 61.889 49.194 62.069 ;
     RECT  14.652 61.997 16.146 62.159 ;
     RECT  44.352 62.069 49.194 62.159 ;
     RECT  14.652 62.159 15.714 62.195 ;
     RECT  44.352 62.159 44.55 62.195 ;
     RECT  45.324 62.159 49.194 62.195 ;
     RECT  22.212 61.655 38.25 62.231 ;
     RECT  25.056 62.231 38.25 62.237 ;
     RECT  25.056 62.237 33.39 62.24 ;
     RECT  34.2 62.237 38.25 62.251 ;
     RECT  38.988 62.069 43.614 62.251 ;
     RECT  14.832 62.195 15.714 62.267 ;
     RECT  25.2 62.24 33.39 62.267 ;
     RECT  34.2 62.251 43.614 62.267 ;
     RECT  14.832 62.267 14.85 62.303 ;
     RECT  15.696 62.267 15.714 62.303 ;
     RECT  17.604 62.069 21.33 62.303 ;
     RECT  34.2 62.267 41.742 62.303 ;
     RECT  42.66 62.267 43.614 62.303 ;
     RECT  44.532 62.195 44.55 62.303 ;
     RECT  45.324 62.195 48.87 62.339 ;
     RECT  2.415 61.925 2.697 62.387 ;
     RECT  7.815 61.349 8.097 62.387 ;
     RECT  13.215 62.033 13.497 62.387 ;
     RECT  22.248 62.231 24.297 62.387 ;
     RECT  34.2 62.303 38.79 62.387 ;
     RECT  45.324 62.339 45.897 62.387 ;
     RECT  51.015 60.179 51.297 62.387 ;
     RECT  56.415 60.845 56.697 62.387 ;
     RECT  61.815 57.605 62.097 62.387 ;
     RECT  17.604 62.303 17.622 62.429 ;
     RECT  18.615 62.303 21.33 62.429 ;
     RECT  22.248 62.387 24.174 62.429 ;
     RECT  42.768 62.303 43.614 62.429 ;
     RECT  45.324 62.387 45.774 62.429 ;
     RECT  46.728 62.339 48.798 62.429 ;
     RECT  46.728 62.429 46.746 62.435 ;
     RECT  47.52 62.429 48.798 62.435 ;
     RECT  18.615 62.429 20.214 62.465 ;
     RECT  22.248 62.429 22.95 62.465 ;
     RECT  25.2 62.267 33.354 62.465 ;
     RECT  35.748 62.387 38.79 62.465 ;
     RECT  39.636 62.303 41.742 62.465 ;
     RECT  47.7 62.435 48.798 62.465 ;
     RECT  22.248 62.465 22.806 62.501 ;
     RECT  31.752 62.465 33.354 62.501 ;
     RECT  35.748 62.465 37.206 62.501 ;
     RECT  47.7 62.465 47.718 62.501 ;
     RECT  48.456 62.465 48.798 62.501 ;
     RECT  25.2 62.465 30.654 62.525 ;
     RECT  35.748 62.501 35.91 62.525 ;
     RECT  36.684 62.501 37.206 62.525 ;
     RECT  25.344 62.525 30.654 62.537 ;
     RECT  31.752 62.501 31.878 62.537 ;
     RECT  38.232 62.465 38.79 62.537 ;
     RECT  27.684 62.537 30.654 62.573 ;
     RECT  31.824 62.537 31.878 62.573 ;
     RECT  35.892 62.525 35.91 62.573 ;
     RECT  36.684 62.525 37.134 62.573 ;
     RECT  39.636 62.465 41.49 62.573 ;
     RECT  39.636 62.573 40.554 62.579 ;
     RECT  21.132 62.429 21.33 62.609 ;
     RECT  22.788 62.501 22.806 62.609 ;
     RECT  23.832 62.429 24.174 62.609 ;
     RECT  26.388 62.537 26.802 62.609 ;
     RECT  27.684 62.573 30.078 62.609 ;
     RECT  36.684 62.573 36.702 62.609 ;
     RECT  38.232 62.537 38.682 62.609 ;
     RECT  41.472 62.573 41.49 62.609 ;
     RECT  45.615 62.429 45.774 62.609 ;
     RECT  32.976 62.501 33.354 62.621 ;
     RECT  42.804 62.429 43.614 62.621 ;
     RECT  2.415 62.387 2.505 62.657 ;
     RECT  7.815 62.387 7.905 62.657 ;
     RECT  13.215 62.387 13.305 62.657 ;
     RECT  18.615 62.465 18.954 62.657 ;
     RECT  27.684 62.609 29.505 62.657 ;
     RECT  34.2 62.387 34.905 62.657 ;
     RECT  40.215 62.579 40.554 62.657 ;
     RECT  45.615 62.609 45.705 62.657 ;
     RECT  51.015 62.387 51.105 62.657 ;
     RECT  56.415 62.387 56.505 62.657 ;
     RECT  61.815 62.387 61.905 62.657 ;
     RECT  27.684 62.657 29.322 62.669 ;
     RECT  18.936 62.657 18.954 62.699 ;
     RECT  20.196 62.465 20.214 62.699 ;
     RECT  21.132 62.609 21.15 62.699 ;
     RECT  23.868 62.609 24.174 62.699 ;
     RECT  27.936 62.669 29.322 62.699 ;
     RECT  34.2 62.657 34.794 62.699 ;
     RECT  40.536 62.657 40.554 62.699 ;
     RECT  43.524 62.621 43.614 62.699 ;
     RECT  48.78 62.501 48.798 62.699 ;
     RECT  27.936 62.699 27.954 62.771 ;
     RECT  31.86 62.573 31.878 62.771 ;
    LAYER M4 ;
     RECT  2.365 23.328 2.408 23.352 ;
     RECT  2.365 26.64 2.408 26.664 ;
     RECT  0.181 33.84 2.408 33.864 ;
     RECT  2.365 36.096 2.408 36.12 ;
     RECT  0.06 54.864 2.408 57.864 ;
     RECT  0.06 60.144 2.408 60.936 ;
     RECT  2.408 2.148 2.512 62.652 ;
     RECT  2.512 2.418 2.704 62.382 ;
     RECT  2.704 54.864 2.765 58.152 ;
     RECT  2.704 60.624 2.801 60.648 ;
     RECT  2.704 28.464 2.819 31.272 ;
     RECT  2.819 28.464 2.86 29.64 ;
     RECT  2.704 17.088 2.867 19.56 ;
     RECT  2.765 56.88 2.873 58.152 ;
     RECT  2.867 18.768 2.945 19.56 ;
     RECT  2.86 28.464 2.981 28.488 ;
     RECT  2.873 57.12 3.053 58.152 ;
     RECT  2.704 21.984 3.125 23.352 ;
     RECT  3.053 57.312 3.125 58.152 ;
     RECT  2.704 36.096 3.197 36.12 ;
     RECT  2.704 38.016 3.395 39.192 ;
     RECT  3.125 57.84 3.485 58.152 ;
     RECT  2.704 33.408 3.629 34.728 ;
     RECT  2.765 54.864 3.665 55.752 ;
     RECT  2.819 31.008 3.788 31.272 ;
     RECT  2.86 29.616 3.805 29.64 ;
     RECT  3.788 31.008 3.805 31.8 ;
     RECT  3.805 29.616 3.829 31.8 ;
     RECT  2.704 20.976 3.881 21 ;
     RECT  2.704 26.64 3.913 26.664 ;
     RECT  3.629 33.84 3.913 34.728 ;
     RECT  3.805 36.816 3.917 36.84 ;
     RECT  3.395 38.016 3.917 38.76 ;
     RECT  3.913 26.208 3.953 26.664 ;
     RECT  2.704 11.28 4.019 11.928 ;
     RECT  2.867 17.088 4.021 17.112 ;
     RECT  3.125 21.984 4.025 22.776 ;
     RECT  3.913 33.84 4.025 34.776 ;
     RECT  4.019 11.424 4.061 11.928 ;
     RECT  3.697 61.2 4.117 61.224 ;
     RECT  3.665 54.864 4.205 55.272 ;
     RECT  4.172 56.928 4.259 56.952 ;
     RECT  2.704 49.488 4.261 51.672 ;
     RECT  4.025 22.752 4.273 22.776 ;
     RECT  4.261 48.96 4.349 51.672 ;
     RECT  3.829 29.616 4.385 32.472 ;
     RECT  2.704 10.224 4.421 10.248 ;
     RECT  2.945 19.488 4.453 19.56 ;
     RECT  3.485 58.128 4.453 58.152 ;
     RECT  4.061 11.472 4.489 11.928 ;
     RECT  4.453 19.392 4.601 19.56 ;
     RECT  4.385 30.72 4.601 32.472 ;
     RECT  4.601 30.72 4.745 30.84 ;
     RECT  4.453 52.992 4.745 53.016 ;
     RECT  3.917 38.112 4.813 38.76 ;
     RECT  4.117 60.384 4.817 61.224 ;
     RECT  4.021 16.8 4.844 17.112 ;
     RECT  4.844 16.8 4.885 18.024 ;
     RECT  4.601 19.392 4.885 19.512 ;
     RECT  4.489 11.472 4.921 11.976 ;
     RECT  4.385 29.616 4.957 29.64 ;
     RECT  4.669 24.768 4.997 24.792 ;
     RECT  4.813 38.112 4.997 38.808 ;
     RECT  4.381 44.976 5.029 45 ;
     RECT  4.741 46.08 5.029 46.104 ;
     RECT  4.957 29.232 5.036 29.64 ;
     RECT  4.453 57.312 5.101 58.152 ;
     RECT  4.357 59.232 5.101 59.256 ;
     RECT  5.036 27.888 5.123 27.912 ;
     RECT  5.036 28.944 5.123 29.64 ;
     RECT  2.704 14.88 5.125 14.904 ;
     RECT  5.101 40.704 5.125 40.728 ;
     RECT  4.921 11.472 5.141 12.552 ;
     RECT  5.125 14.208 5.171 15.432 ;
     RECT  4.885 16.8 5.177 19.512 ;
     RECT  5.123 29.04 5.177 29.64 ;
     RECT  4.601 31.824 5.177 32.472 ;
     RECT  4.025 33.84 5.177 34.728 ;
     RECT  5.177 29.04 5.213 29.256 ;
     RECT  5.125 39.648 5.213 40.728 ;
     RECT  5.137 52.8 5.249 52.824 ;
     RECT  4.817 60.384 5.249 60.408 ;
     RECT  3.953 26.208 5.281 26.232 ;
     RECT  5.101 57.312 5.285 59.256 ;
     RECT  4.525 9.12 5.317 9.144 ;
     RECT  4.997 38.112 5.321 38.664 ;
     RECT  4.957 42.192 5.321 42.216 ;
     RECT  5.171 15.408 5.389 15.432 ;
     RECT  5.285 57.312 5.389 58.392 ;
     RECT  5.177 16.8 5.461 18.984 ;
     RECT  5.389 57.072 5.461 58.392 ;
     RECT  5.177 32.016 5.465 32.472 ;
     RECT  5.177 33.84 5.533 33.96 ;
     RECT  5.029 44.976 5.609 46.104 ;
     RECT  5.461 16.56 5.681 18.984 ;
     RECT  5.465 32.448 5.681 32.472 ;
     RECT  5.317 9.12 5.708 9.24 ;
     RECT  5.708 9.12 5.749 9.48 ;
     RECT  5.609 45.696 5.753 46.104 ;
     RECT  5.749 8.736 5.795 9.48 ;
     RECT  5.785 53.52 5.821 53.544 ;
     RECT  4.745 30.816 5.893 30.84 ;
     RECT  4.273 22.752 5.929 23.016 ;
     RECT  5.677 47.568 5.965 47.592 ;
     RECT  5.213 39.888 6.001 40.728 ;
     RECT  5.821 42.048 6.001 42.072 ;
     RECT  5.425 34.992 6.005 35.016 ;
     RECT  5.171 14.208 6.037 14.232 ;
     RECT  5.965 47.328 6.037 47.592 ;
     RECT  5.641 44.304 6.083 44.328 ;
     RECT  5.321 38.112 6.109 38.616 ;
     RECT  5.425 21.12 6.145 21.144 ;
     RECT  4.205 55.248 6.145 55.272 ;
     RECT  5.461 56.256 6.145 58.392 ;
     RECT  6.001 39.888 6.149 42.072 ;
     RECT  4.349 49.152 6.181 51.672 ;
     RECT  5.821 53.52 6.217 53.784 ;
     RECT  6.149 41.04 6.221 42.072 ;
     RECT  6.037 14.16 6.253 14.232 ;
     RECT  5.389 15.408 6.253 15.48 ;
     RECT  6.181 49.152 6.253 52.488 ;
     RECT  6.217 53.472 6.253 53.784 ;
     RECT  5.281 26.208 6.277 26.52 ;
     RECT  5.213 29.04 6.284 29.064 ;
     RECT  6.253 49.152 6.284 53.784 ;
     RECT  6.037 47.28 6.289 47.592 ;
     RECT  6.284 49.152 6.293 54.12 ;
     RECT  6.109 37.584 6.316 38.616 ;
     RECT  5.681 18.96 6.361 18.984 ;
     RECT  5.533 33.6 6.361 33.96 ;
     RECT  6.277 25.056 6.364 26.52 ;
     RECT  6.364 25.824 6.373 26.52 ;
     RECT  6.284 28.08 6.373 29.064 ;
     RECT  6.373 25.824 6.437 29.064 ;
     RECT  6.145 20.928 6.469 21.144 ;
     RECT  5.929 22.224 6.469 23.016 ;
     RECT  6.253 14.16 6.505 15.48 ;
     RECT  5.681 16.56 6.505 17.976 ;
     RECT  5.425 60 6.505 60.024 ;
     RECT  5.753 45.696 6.509 45.768 ;
     RECT  6.505 60 6.545 60.456 ;
     RECT  5.141 11.664 6.62 12.552 ;
     RECT  6.361 33.6 6.649 34.152 ;
     RECT  6.62 11.664 6.707 13.08 ;
     RECT  6.221 41.472 6.716 42.072 ;
     RECT  5.389 36.384 6.721 36.408 ;
     RECT  6.316 37.584 6.721 38.232 ;
     RECT  6.649 33.552 6.757 34.152 ;
     RECT  6.716 41.472 6.803 42.216 ;
     RECT  5.893 30.624 6.805 30.84 ;
     RECT  6.289 47.28 6.829 48.12 ;
     RECT  6.707 11.664 6.833 12.216 ;
     RECT  6.829 47.136 6.853 48.12 ;
     RECT  6.505 14.16 6.901 17.976 ;
     RECT  6.293 49.2 6.901 54.12 ;
     RECT  6.145 55.248 6.901 58.392 ;
     RECT  6.901 14.112 6.937 17.976 ;
     RECT  6.469 20.928 6.937 23.016 ;
     RECT  6.829 24.192 6.937 24.216 ;
     RECT  6.805 30.624 6.937 31.128 ;
     RECT  5.795 8.736 6.973 9.24 ;
     RECT  6.721 36.384 6.973 38.232 ;
     RECT  6.833 11.664 7.045 12.072 ;
     RECT  6.937 30.336 7.045 31.128 ;
     RECT  6.649 43.92 7.081 43.944 ;
     RECT  7.045 30.144 7.333 31.128 ;
     RECT  6.901 49.2 7.333 58.392 ;
     RECT  6.937 13.392 7.405 17.976 ;
     RECT  6.361 18.96 7.405 19.416 ;
     RECT  7.333 30.144 7.405 31.512 ;
     RECT  6.853 46.704 7.525 48.12 ;
     RECT  7.333 49.2 7.525 59.064 ;
     RECT  6.545 60.432 7.621 60.456 ;
     RECT  7.405 13.392 7.669 19.416 ;
     RECT  6.437 25.824 7.729 26.232 ;
     RECT  6.437 27.216 7.729 29.064 ;
     RECT  7.405 30.144 7.729 31.8 ;
     RECT  6.757 33.072 7.729 34.152 ;
     RECT  6.973 8.736 7.765 9.528 ;
     RECT  7.765 8.736 7.808 9.912 ;
     RECT  7.045 11.424 7.808 12.072 ;
     RECT  7.669 13.392 7.808 19.8 ;
     RECT  6.937 20.928 7.808 24.216 ;
     RECT  7.729 25.824 7.808 29.064 ;
     RECT  7.729 30.144 7.808 34.152 ;
     RECT  6.973 36.288 7.808 38.232 ;
     RECT  6.149 39.888 7.808 39.912 ;
     RECT  6.803 41.472 7.808 41.592 ;
     RECT  7.081 43.92 7.808 44.088 ;
     RECT  6.509 45.696 7.808 45.72 ;
     RECT  7.525 46.704 7.808 59.064 ;
     RECT  7.621 60.432 7.808 61.032 ;
     RECT  7.808 2.148 7.912 62.652 ;
     RECT  7.912 2.418 8.104 62.382 ;
     RECT  8.104 48.72 8.165 51.672 ;
     RECT  8.104 26.784 8.201 28.824 ;
     RECT  8.104 13.344 8.284 17.64 ;
     RECT  8.104 7.92 8.291 12.216 ;
     RECT  8.284 15.456 8.309 17.64 ;
     RECT  8.284 13.344 8.345 13.944 ;
     RECT  8.201 26.784 8.453 28.008 ;
     RECT  8.291 7.92 8.489 10.872 ;
     RECT  8.345 13.392 8.489 13.944 ;
     RECT  8.489 7.92 8.561 8.76 ;
     RECT  8.104 20.928 8.633 21.48 ;
     RECT  8.104 47.088 8.669 47.64 ;
     RECT  8.489 13.92 8.777 13.944 ;
     RECT  8.104 53.52 8.777 59.064 ;
     RECT  8.104 30.048 9.029 35.256 ;
     RECT  8.104 39.888 9.133 41.496 ;
     RECT  8.104 42.528 9.133 44.472 ;
     RECT  8.104 60.192 9.155 60.216 ;
     RECT  9.133 39.888 9.164 44.472 ;
     RECT  8.309 15.552 9.173 17.64 ;
     RECT  9.029 30.048 9.173 35.016 ;
     RECT  8.104 19.104 9.205 19.368 ;
     RECT  8.104 36.24 9.205 38.136 ;
     RECT  9.164 39.696 9.209 44.472 ;
     RECT  8.489 9.888 9.245 10.872 ;
     RECT  9.173 16.8 9.245 17.64 ;
     RECT  9.209 39.696 9.251 39.72 ;
     RECT  9.209 40.848 9.277 44.472 ;
     RECT  8.165 49.008 9.277 51.672 ;
     RECT  9.277 49.008 9.313 51.768 ;
     RECT  8.453 26.784 9.421 27.96 ;
     RECT  9.173 30.048 9.425 34.536 ;
     RECT  9.313 48.672 9.457 52.008 ;
     RECT  9.313 53.136 9.457 53.16 ;
     RECT  9.421 26.64 9.493 27.96 ;
     RECT  8.777 54.528 9.493 59.064 ;
     RECT  8.104 22.56 9.529 23.88 ;
     RECT  9.205 18.768 9.533 19.368 ;
     RECT  9.205 36.24 9.565 38.712 ;
     RECT  8.561 7.92 9.569 8.28 ;
     RECT  8.291 12.192 9.601 12.216 ;
     RECT  8.633 20.928 9.601 21.432 ;
     RECT  9.529 22.56 9.601 24.264 ;
     RECT  9.109 61.344 9.601 61.368 ;
     RECT  9.425 30.624 9.605 34.536 ;
     RECT  9.173 15.552 9.635 15.672 ;
     RECT  9.493 26.64 9.637 28.872 ;
     RECT  8.669 47.28 9.637 47.64 ;
     RECT  9.457 48.672 9.637 53.16 ;
     RECT  9.601 61.104 9.637 61.368 ;
     RECT  9.589 9.648 9.676 9.672 ;
     RECT  9.601 20.928 9.677 24.264 ;
     RECT  9.565 36.096 9.677 38.712 ;
     RECT  9.277 40.848 9.685 44.856 ;
     RECT  9.637 47.28 9.745 53.16 ;
     RECT  9.817 46.272 9.853 46.296 ;
     RECT  9.745 47.28 9.853 53.256 ;
     RECT  8.104 25.296 9.889 25.32 ;
     RECT  9.605 31.104 9.916 34.536 ;
     RECT  9.601 12.192 9.925 13.176 ;
     RECT  9.493 54.528 9.929 59.208 ;
     RECT  9.685 40.848 9.965 45.144 ;
     RECT  9.929 54.528 10.028 58.392 ;
     RECT  9.677 36.096 10.069 38.328 ;
     RECT  9.925 12 10.073 13.176 ;
     RECT  10.028 54.384 10.115 58.392 ;
     RECT  9.677 20.928 10.145 24.216 ;
     RECT  10.115 54.576 10.181 58.392 ;
     RECT  10.105 39.312 10.189 39.336 ;
     RECT  9.245 10.848 10.213 10.872 ;
     RECT  10.073 12 10.213 12.744 ;
     RECT  9.635 15.6 10.249 15.672 ;
     RECT  9.245 16.8 10.249 17.064 ;
     RECT  10.145 20.928 10.285 21.288 ;
     RECT  9.916 33.84 10.285 34.536 ;
     RECT  10.069 35.616 10.285 38.328 ;
     RECT  9.965 44.064 10.393 45.144 ;
     RECT  9.853 46.272 10.393 53.256 ;
     RECT  10.285 33.84 10.397 38.328 ;
     RECT  10.393 44.064 10.433 53.256 ;
     RECT  9.916 31.104 10.469 32.472 ;
     RECT  9.637 26.64 10.505 29.592 ;
     RECT  9.533 18.768 10.541 19.32 ;
     RECT  10.145 22.272 10.541 24.216 ;
     RECT  10.285 20.592 10.556 21.288 ;
     RECT  10.541 19.296 10.597 19.32 ;
     RECT  10.181 54.624 10.613 58.392 ;
     RECT  10.556 20.448 10.643 21.288 ;
     RECT  10.643 20.592 10.649 21.288 ;
     RECT  10.469 31.104 10.717 32.328 ;
     RECT  9.889 25.296 10.793 25.512 ;
     RECT  9.569 8.112 10.825 8.28 ;
     RECT  10.505 27.312 10.825 29.592 ;
     RECT  10.717 30.816 10.825 32.328 ;
     RECT  10.397 33.84 10.865 34.44 ;
     RECT  9.965 40.944 10.937 42.648 ;
     RECT  10.249 15.6 11.045 17.064 ;
     RECT  10.937 40.944 11.113 42.552 ;
     RECT  10.825 8.112 11.132 8.712 ;
     RECT  11.045 15.6 11.185 16.92 ;
     RECT  10.613 54.672 11.189 58.392 ;
     RECT  11.132 7.2 11.219 8.712 ;
     RECT  10.213 10.848 11.269 12.744 ;
     RECT  10.433 44.688 11.363 53.256 ;
     RECT  11.113 40.704 11.369 42.552 ;
     RECT  11.369 40.944 11.405 42.552 ;
     RECT  11.185 15.408 11.585 16.92 ;
     RECT  10.793 25.296 11.653 25.32 ;
     RECT  9.637 61.104 11.66 61.416 ;
     RECT  10.825 27.312 11.689 32.328 ;
     RECT  11.363 44.688 11.689 49.032 ;
     RECT  10.649 20.592 11.725 21.144 ;
     RECT  10.541 22.32 11.725 24.216 ;
     RECT  11.66 60.48 11.747 61.416 ;
     RECT  9.709 14.208 11.761 14.232 ;
     RECT  11.269 10.848 11.873 12.888 ;
     RECT  11.653 25.2 11.941 25.32 ;
     RECT  11.689 27.312 11.941 32.376 ;
     RECT  11.363 50.16 11.945 53.256 ;
     RECT  11.725 20.592 12.013 24.216 ;
     RECT  11.941 25.2 12.013 25.752 ;
     RECT  10.397 35.568 12.013 38.328 ;
     RECT  11.189 55.536 12.037 58.392 ;
     RECT  10.597 19.296 12.089 19.416 ;
     RECT  11.219 7.968 12.193 8.712 ;
     RECT  11.747 61.104 12.265 61.416 ;
     RECT  10.865 33.84 12.337 34.008 ;
     RECT  12.013 35.232 12.337 38.328 ;
     RECT  12.337 33.84 12.373 38.328 ;
     RECT  12.037 55.536 12.373 58.728 ;
     RECT  12.193 7.968 12.409 9.48 ;
     RECT  12.013 20.592 12.409 25.752 ;
     RECT  11.945 50.16 12.409 51.96 ;
     RECT  11.761 14.208 12.476 14.376 ;
     RECT  12.373 33.552 12.476 38.328 ;
     RECT  12.085 43.296 12.481 43.32 ;
     RECT  11.689 44.448 12.481 49.032 ;
     RECT  11.941 26.736 12.509 32.376 ;
     RECT  12.476 33.552 12.509 38.664 ;
     RECT  12.193 39.648 12.517 39.672 ;
     RECT  11.405 40.944 12.517 42.12 ;
     RECT  12.373 55.536 12.589 59.256 ;
     RECT  12.589 55.296 12.733 59.256 ;
     RECT  11.585 15.984 12.769 16.92 ;
     RECT  12.409 20.112 12.805 25.752 ;
     RECT  12.509 26.736 12.805 38.664 ;
     RECT  11.873 11.424 12.877 12.888 ;
     RECT  11.945 53.04 12.877 53.256 ;
     RECT  12.733 54.384 12.877 59.256 ;
     RECT  12.409 6.816 12.908 9.48 ;
     RECT  12.877 10.608 12.908 12.888 ;
     RECT  12.476 14.208 13.021 14.904 ;
     RECT  12.769 15.984 13.021 17.64 ;
     RECT  12.481 43.296 13.057 49.032 ;
     RECT  12.409 50.064 13.057 51.96 ;
     RECT  13.057 43.296 13.093 51.96 ;
     RECT  12.877 53.04 13.093 59.256 ;
     RECT  12.908 6.816 13.208 12.888 ;
     RECT  13.021 14.208 13.208 17.64 ;
     RECT  12.697 18.72 13.208 18.744 ;
     RECT  12.805 20.112 13.208 38.664 ;
     RECT  12.517 39.648 13.208 42.12 ;
     RECT  13.093 43.296 13.208 59.256 ;
     RECT  12.265 61.104 13.208 61.704 ;
     RECT  13.208 2.148 13.312 62.652 ;
     RECT  13.312 2.418 13.504 62.382 ;
     RECT  13.504 29.04 13.565 45.768 ;
     RECT  13.565 29.04 13.673 45.624 ;
     RECT  13.504 53.136 13.709 61.8 ;
     RECT  13.673 29.04 13.773 34.488 ;
     RECT  13.504 46.752 13.817 51.96 ;
     RECT  13.673 35.52 13.853 45.624 ;
     RECT  13.853 37.008 13.859 45.624 ;
     RECT  13.709 53.136 13.859 60.312 ;
     RECT  13.504 6.816 13.889 9.576 ;
     RECT  13.504 14.448 13.889 18.024 ;
     RECT  13.504 10.608 13.925 12.888 ;
     RECT  13.853 35.52 14.033 36.024 ;
     RECT  13.859 37.008 14.105 44.328 ;
     RECT  13.817 46.8 14.105 51.96 ;
     RECT  13.504 19.248 14.147 22.296 ;
     RECT  14.147 19.248 14.393 20.616 ;
     RECT  14.147 22.224 14.393 22.296 ;
     RECT  13.504 23.808 14.393 27.816 ;
     RECT  13.859 54.576 14.393 60.312 ;
     RECT  14.393 25.44 14.465 27.816 ;
     RECT  14.105 41.472 14.465 44.328 ;
     RECT  13.889 6.816 14.497 8.568 ;
     RECT  14.393 22.224 14.501 22.248 ;
     RECT  13.773 29.04 14.537 33.864 ;
     RECT  14.105 37.008 14.645 40.44 ;
     RECT  13.925 10.608 14.749 11.832 ;
     RECT  13.889 14.448 14.753 17.496 ;
     RECT  13.709 61.44 14.785 61.8 ;
     RECT  14.105 46.896 14.821 51.96 ;
     RECT  13.859 53.136 14.821 53.592 ;
     RECT  14.465 41.472 14.825 44.232 ;
     RECT  14.785 61.344 14.861 61.8 ;
     RECT  14.749 10.32 14.867 11.832 ;
     RECT  14.861 61.344 14.897 61.464 ;
     RECT  14.645 40.032 15.113 40.44 ;
     RECT  15.113 40.032 15.149 40.152 ;
     RECT  14.537 31.104 15.185 33.864 ;
     RECT  14.821 46.896 15.205 53.592 ;
     RECT  14.393 54.576 15.205 59.784 ;
     RECT  14.393 23.808 15.212 24.408 ;
     RECT  15.185 31.104 15.221 32.472 ;
     RECT  14.825 41.472 15.221 42.024 ;
     RECT  14.897 61.44 15.221 61.464 ;
     RECT  14.753 14.448 15.253 14.808 ;
     RECT  15.212 23.76 15.299 24.408 ;
     RECT  14.753 15.84 15.395 17.496 ;
     RECT  15.299 23.808 15.437 24.408 ;
     RECT  15.205 46.896 15.443 59.784 ;
     RECT  14.497 6.672 15.469 8.568 ;
     RECT  15.469 6.672 15.473 9 ;
     RECT  13.859 45.6 15.509 45.624 ;
     RECT  14.393 19.344 15.541 20.616 ;
     RECT  15.253 22.128 15.541 22.152 ;
     RECT  14.537 29.04 15.545 30.072 ;
     RECT  15.221 31.104 15.545 31.464 ;
     RECT  14.033 35.52 15.613 35.544 ;
     RECT  15.443 46.896 15.617 53.352 ;
     RECT  15.395 15.984 15.653 17.496 ;
     RECT  15.545 29.568 15.653 30.072 ;
     RECT  15.653 29.616 15.685 30.072 ;
     RECT  14.645 37.008 15.685 38.184 ;
     RECT  15.185 33.648 15.721 33.864 ;
     RECT  15.613 35.328 15.721 35.544 ;
     RECT  15.473 6.672 15.725 7.8 ;
     RECT  15.685 29.616 15.725 30.264 ;
     RECT  15.541 19.344 15.761 22.152 ;
     RECT  15.437 23.856 15.761 24.408 ;
     RECT  15.221 41.472 15.781 41.832 ;
     RECT  15.473 8.976 15.793 9 ;
     RECT  15.617 46.896 15.793 52.248 ;
     RECT  14.825 43.248 15.827 44.232 ;
     RECT  15.253 14.256 15.833 14.808 ;
     RECT  15.761 19.488 15.833 22.152 ;
     RECT  15.781 41.232 15.868 41.832 ;
     RECT  13.925 12.864 15.869 12.888 ;
     RECT  14.465 25.968 15.869 27.816 ;
     RECT  15.793 46.8 15.901 52.248 ;
     RECT  15.721 33.648 15.925 35.544 ;
     RECT  15.685 37.008 15.925 38.232 ;
     RECT  15.761 24.24 15.937 24.408 ;
     RECT  15.869 25.968 15.937 27.768 ;
     RECT  15.901 46.752 15.937 52.248 ;
     RECT  15.833 19.488 15.941 19.512 ;
     RECT  15.937 24.24 15.941 27.768 ;
     RECT  15.868 41.472 15.941 41.832 ;
     RECT  14.867 11.136 15.973 11.832 ;
     RECT  15.925 33.648 16.012 38.232 ;
     RECT  16.012 37.296 16.081 38.232 ;
     RECT  15.973 10.848 16.085 11.832 ;
     RECT  15.937 45.936 16.085 52.248 ;
     RECT  16.085 11.136 16.189 11.832 ;
     RECT  15.833 14.256 16.193 14.472 ;
     RECT  16.081 37.296 16.193 38.664 ;
     RECT  15.941 26.4 16.229 27.768 ;
     RECT  15.725 7.008 16.265 7.8 ;
     RECT  15.221 32.448 16.265 32.472 ;
     RECT  15.725 30.048 16.301 30.264 ;
     RECT  15.793 8.976 16.333 9.096 ;
     RECT  15.617 53.328 16.405 53.352 ;
     RECT  15.443 54.384 16.405 59.784 ;
     RECT  16.333 8.976 16.445 9.384 ;
     RECT  15.781 39.792 16.481 39.816 ;
     RECT  15.827 44.064 16.513 44.232 ;
     RECT  15.833 20.592 16.621 22.152 ;
     RECT  16.445 8.976 16.625 9 ;
     RECT  16.549 61.008 16.643 61.032 ;
     RECT  16.012 33.648 16.657 35.688 ;
     RECT  16.189 11.136 16.733 12.552 ;
     RECT  15.941 24.24 16.787 25.32 ;
     RECT  16.265 7.008 16.805 7.224 ;
     RECT  16.585 42.768 16.877 42.936 ;
     RECT  16.301 30.24 16.909 30.264 ;
     RECT  15.545 31.44 16.909 31.464 ;
     RECT  16.787 25.296 16.913 25.32 ;
     RECT  16.909 30.24 16.945 31.464 ;
     RECT  16.877 42.816 16.945 42.936 ;
     RECT  15.653 15.984 16.949 16.92 ;
     RECT  16.657 33.312 16.949 35.688 ;
     RECT  16.085 45.936 17.053 50.712 ;
     RECT  16.085 51.696 17.053 52.248 ;
     RECT  16.405 53.328 17.053 59.784 ;
     RECT  16.949 15.984 17.125 16.344 ;
     RECT  16.949 34.944 17.125 35.688 ;
     RECT  16.193 37.296 17.129 38.28 ;
     RECT  16.733 11.136 17.165 11.832 ;
     RECT  16.621 20.592 17.197 22.2 ;
     RECT  17.053 45.936 17.197 59.784 ;
     RECT  17.197 20.592 17.333 22.728 ;
     RECT  15.941 41.472 17.341 41.736 ;
     RECT  17.333 20.592 17.377 22.872 ;
     RECT  16.945 19.296 17.449 19.32 ;
     RECT  17.377 20.592 17.449 23.064 ;
     RECT  17.449 19.296 17.485 23.064 ;
     RECT  16.787 24.24 17.485 24.264 ;
     RECT  16.193 14.448 17.521 14.472 ;
     RECT  16.945 30.24 17.521 32.328 ;
     RECT  16.949 33.312 17.521 33.864 ;
     RECT  16.229 27.744 17.557 27.768 ;
     RECT  16.513 44.064 17.593 44.472 ;
     RECT  17.197 45.552 17.593 59.784 ;
     RECT  17.593 9.648 17.653 9.672 ;
     RECT  17.269 61.104 17.701 61.128 ;
     RECT  17.165 11.424 17.881 11.832 ;
     RECT  17.701 12.912 17.881 12.936 ;
     RECT  17.125 15.744 17.953 16.344 ;
     RECT  17.653 9.648 17.989 10.104 ;
     RECT  17.521 30.24 17.989 33.864 ;
     RECT  17.125 34.944 17.989 35.736 ;
     RECT  16.945 42.816 17.989 43.032 ;
     RECT  16.805 7.2 18.025 7.224 ;
     RECT  17.129 37.296 18.097 38.184 ;
     RECT  17.593 44.064 18.097 59.784 ;
     RECT  17.701 60.864 18.097 61.128 ;
     RECT  17.989 34.944 18.133 36.264 ;
     RECT  18.097 37.296 18.133 38.424 ;
     RECT  17.989 9.648 18.169 10.344 ;
     RECT  16.229 26.4 18.169 26.424 ;
     RECT  18.025 7.2 18.205 7.416 ;
     RECT  18.169 9.648 18.229 10.44 ;
     RECT  17.881 11.424 18.229 12.936 ;
     RECT  17.989 29.76 18.229 33.864 ;
     RECT  18.133 34.944 18.229 38.424 ;
     RECT  17.557 27.744 18.236 28.152 ;
     RECT  17.989 42.768 18.241 43.032 ;
     RECT  18.097 44.064 18.241 61.128 ;
     RECT  18.169 26.4 18.421 26.664 ;
     RECT  18.205 6.288 18.608 7.416 ;
     RECT  18.229 9.648 18.608 12.936 ;
     RECT  17.521 14.208 18.608 14.472 ;
     RECT  17.953 15.744 18.608 16.392 ;
     RECT  16.657 18.192 18.608 18.216 ;
     RECT  17.485 19.296 18.608 24.264 ;
     RECT  18.421 25.488 18.608 26.664 ;
     RECT  18.236 27.744 18.608 28.776 ;
     RECT  18.229 29.76 18.608 38.424 ;
     RECT  17.341 41.232 18.608 41.736 ;
     RECT  18.241 42.768 18.608 61.128 ;
     RECT  17.629 62.16 18.608 62.184 ;
     RECT  18.608 2.148 18.712 62.652 ;
     RECT  18.712 2.418 18.904 62.424 ;
     RECT  18.904 18 18.965 21.48 ;
     RECT  18.904 42.816 19.037 60.888 ;
     RECT  18.904 6.288 19.073 10.632 ;
     RECT  18.904 40.464 19.073 41.736 ;
     RECT  19.037 43.008 19.073 60.888 ;
     RECT  19.073 7.392 19.132 10.632 ;
     RECT  18.965 18.768 19.145 21.48 ;
     RECT  19.132 9.888 19.217 10.632 ;
     RECT  19.217 10.08 19.253 10.632 ;
     RECT  18.904 25.488 19.253 26.664 ;
     RECT  19.253 10.08 19.289 10.44 ;
     RECT  19.145 18.768 19.397 20.664 ;
     RECT  19.073 40.464 19.433 40.488 ;
     RECT  19.073 45.84 19.433 60.888 ;
     RECT  18.904 29.472 19.613 34.824 ;
     RECT  18.904 11.76 19.685 16.008 ;
     RECT  19.073 43.008 19.757 44.232 ;
     RECT  19.613 29.472 19.859 33.96 ;
     RECT  18.904 61.968 19.865 62.424 ;
     RECT  18.904 35.952 19.916 39.288 ;
     RECT  19.253 25.536 19.955 26.664 ;
     RECT  18.904 22.752 19.973 24.504 ;
     RECT  19.433 45.84 20.041 60.648 ;
     RECT  19.916 35.952 20.113 39.864 ;
     RECT  19.073 41.472 20.149 41.736 ;
     RECT  19.132 7.392 20.221 8.472 ;
     RECT  19.289 10.08 20.257 10.104 ;
     RECT  19.685 11.76 20.257 13.32 ;
     RECT  19.073 6.288 20.261 6.312 ;
     RECT  19.955 25.536 20.261 26.52 ;
     RECT  19.973 22.8 20.365 24.504 ;
     RECT  20.257 10.08 20.405 13.32 ;
     RECT  19.757 43.296 20.428 44.232 ;
     RECT  20.113 35.424 20.473 39.864 ;
     RECT  20.473 35.424 20.509 40.344 ;
     RECT  20.041 45.648 20.509 60.648 ;
     RECT  19.865 61.968 20.509 61.992 ;
     RECT  20.428 43.728 20.531 44.232 ;
     RECT  20.509 35.424 20.581 40.44 ;
     RECT  20.365 22.8 20.585 25.272 ;
     RECT  19.685 14.448 20.684 15.624 ;
     RECT  20.221 7.392 20.725 8.52 ;
     RECT  20.677 9.504 20.725 9.528 ;
     RECT  20.684 14.448 20.725 16.008 ;
     RECT  20.725 7.392 20.761 9.528 ;
     RECT  20.509 45.648 20.761 61.992 ;
     RECT  20.725 14.304 20.771 16.008 ;
     RECT  20.771 14.304 20.801 15.48 ;
     RECT  19.397 19.296 20.821 20.664 ;
     RECT  20.821 19.104 20.833 20.664 ;
     RECT  20.581 35.424 20.833 40.488 ;
     RECT  20.149 41.472 20.833 42.024 ;
     RECT  18.904 27.744 20.869 28.488 ;
     RECT  19.859 30.288 20.869 33.96 ;
     RECT  20.761 45.552 20.873 61.992 ;
     RECT  20.869 30 20.941 33.96 ;
     RECT  20.833 35.424 20.941 42.024 ;
     RECT  20.585 25.248 21.017 25.272 ;
     RECT  20.585 22.8 21.049 24.264 ;
     RECT  20.941 30 21.049 42.024 ;
     RECT  21.049 30 21.053 42.456 ;
     RECT  21.053 39.264 21.161 42.456 ;
     RECT  20.833 18.192 21.481 20.664 ;
     RECT  20.545 21.648 21.481 21.672 ;
     RECT  20.261 26.496 21.517 26.52 ;
     RECT  20.869 27.744 21.517 28.536 ;
     RECT  20.761 6.576 21.521 9.528 ;
     RECT  21.161 39.312 21.589 42.456 ;
     RECT  21.481 18.192 21.593 21.672 ;
     RECT  20.873 45.552 21.635 50.328 ;
     RECT  21.517 26.496 21.637 28.536 ;
     RECT  21.053 30 21.637 38.232 ;
     RECT  21.049 22.704 21.661 24.264 ;
     RECT  21.593 20.592 21.665 21.672 ;
     RECT  21.661 22.704 21.683 25.08 ;
     RECT  21.637 26.496 21.733 38.232 ;
     RECT  21.521 7.92 21.737 9.528 ;
     RECT  21.589 39.312 21.737 43.176 ;
     RECT  21.683 23.904 21.881 25.08 ;
     RECT  20.405 10.512 21.949 13.32 ;
     RECT  20.801 14.304 21.949 14.472 ;
     RECT  21.157 17.04 21.949 17.064 ;
     RECT  21.593 18.192 21.949 19.56 ;
     RECT  20.801 15.456 21.989 15.48 ;
     RECT  21.737 8.592 22.057 9.528 ;
     RECT  21.949 10.512 22.057 14.472 ;
     RECT  21.683 22.704 22.129 22.824 ;
     RECT  20.531 44.208 22.129 44.232 ;
     RECT  21.733 26.112 22.165 38.232 ;
     RECT  22.057 8.592 22.201 14.472 ;
     RECT  20.873 51.696 22.201 61.992 ;
     RECT  21.949 17.04 22.213 19.56 ;
     RECT  21.635 46.704 22.313 50.328 ;
     RECT  22.313 50.304 22.457 50.328 ;
     RECT  22.165 26.112 22.525 38.28 ;
     RECT  21.737 39.312 22.525 43.032 ;
     RECT  22.129 22.608 22.529 22.824 ;
     RECT  22.213 16.512 22.561 19.56 ;
     RECT  21.521 6.576 22.565 6.888 ;
     RECT  22.525 26.112 22.601 43.032 ;
     RECT  22.201 8.592 22.733 15.24 ;
     RECT  21.635 45.552 22.741 45.576 ;
     RECT  22.201 51.696 22.741 62.184 ;
     RECT  22.529 22.608 22.777 22.728 ;
     RECT  22.741 51.168 22.777 62.184 ;
     RECT  22.601 35.424 22.817 43.032 ;
     RECT  22.733 8.496 22.849 15.24 ;
     RECT  22.561 16.224 22.885 19.56 ;
     RECT  21.665 20.592 22.885 21.192 ;
     RECT  22.849 8.064 22.889 15.24 ;
     RECT  22.601 26.112 22.889 33.864 ;
     RECT  22.129 44.208 22.933 44.376 ;
     RECT  22.741 45.504 22.933 45.576 ;
     RECT  22.885 16.224 22.961 21.192 ;
     RECT  22.961 17.28 22.993 21.192 ;
     RECT  22.777 22.272 22.993 22.728 ;
     RECT  22.933 44.208 22.993 45.576 ;
     RECT  22.313 46.704 22.993 49.32 ;
     RECT  22.993 17.28 22.997 22.728 ;
     RECT  22.993 44.208 23.02 49.32 ;
     RECT  22.889 26.112 23.029 27.912 ;
     RECT  22.997 19.92 23.033 22.728 ;
     RECT  23.02 45.504 23.425 49.32 ;
     RECT  21.881 23.904 23.533 24.888 ;
     RECT  23.029 26.016 23.533 27.912 ;
     RECT  23.033 20.064 23.641 22.728 ;
     RECT  22.817 35.424 23.653 42.216 ;
     RECT  22.889 13.92 23.677 15.24 ;
     RECT  22.961 16.224 23.677 16.248 ;
     RECT  22.889 30.144 23.677 33.864 ;
     RECT  23.641 20.064 23.785 22.776 ;
     RECT  23.533 23.904 23.785 27.912 ;
     RECT  23.02 44.208 23.857 44.376 ;
     RECT  23.677 30.144 23.893 34.104 ;
     RECT  23.653 35.28 23.893 42.216 ;
     RECT  22.597 6.528 24.008 6.552 ;
     RECT  22.889 8.064 24.008 12.552 ;
     RECT  23.677 13.92 24.008 16.248 ;
     RECT  22.997 17.28 24.008 18.84 ;
     RECT  23.785 20.064 24.008 27.912 ;
     RECT  22.889 29.088 24.008 29.112 ;
     RECT  23.893 30.144 24.008 42.216 ;
     RECT  23.857 43.92 24.008 44.376 ;
     RECT  23.425 45.504 24.008 49.512 ;
     RECT  22.777 51.168 24.008 62.28 ;
     RECT  24.008 2.148 24.112 62.652 ;
     RECT  24.112 2.418 24.304 62.382 ;
     RECT  24.304 44.976 24.329 62.382 ;
     RECT  24.304 35.712 24.437 42.792 ;
     RECT  24.304 17.856 24.545 19.608 ;
     RECT  24.304 20.592 24.545 26.376 ;
     RECT  24.304 27.696 24.653 34.488 ;
     RECT  24.545 17.856 24.833 18.84 ;
     RECT  24.304 9.504 24.869 12.984 ;
     RECT  24.833 18.816 25.013 18.84 ;
     RECT  24.437 36.24 25.013 42.792 ;
     RECT  25.013 36.24 25.085 39.528 ;
     RECT  25.013 41.184 25.085 42.792 ;
     RECT  24.653 27.696 25.157 34.008 ;
     RECT  24.329 51.744 25.189 62.382 ;
     RECT  25.157 29.088 25.265 34.008 ;
     RECT  24.304 7.248 25.34 8.472 ;
     RECT  24.869 9.504 25.34 9.672 ;
     RECT  24.545 20.592 25.409 23.16 ;
     RECT  24.329 44.976 25.409 50.76 ;
     RECT  25.34 7.248 25.427 9.672 ;
     RECT  25.085 36.24 25.441 39.384 ;
     RECT  24.869 10.896 25.445 12.984 ;
     RECT  25.441 35.76 25.477 39.384 ;
     RECT  24.304 14.4 25.513 16.344 ;
     RECT  25.157 27.696 25.513 27.96 ;
     RECT  25.409 21.696 25.573 23.16 ;
     RECT  24.545 24.24 25.573 26.376 ;
     RECT  25.573 21.696 25.619 26.376 ;
     RECT  25.513 14.4 25.621 16.44 ;
     RECT  25.477 35.52 25.621 39.384 ;
     RECT  24.304 43.776 25.621 43.848 ;
     RECT  25.445 11.232 25.625 12.984 ;
     RECT  25.513 27.6 25.733 27.96 ;
     RECT  25.625 11.28 25.801 12.984 ;
     RECT  25.619 26.352 25.801 26.376 ;
     RECT  25.733 27.6 25.801 27.864 ;
     RECT  25.427 7.248 25.841 8.04 ;
     RECT  25.265 29.616 25.877 34.008 ;
     RECT  25.877 30.192 25.909 34.008 ;
     RECT  25.621 35.424 25.909 39.384 ;
     RECT  25.841 7.248 25.913 7.944 ;
     RECT  25.909 30.192 25.949 39.384 ;
     RECT  25.949 30.192 26.051 31.8 ;
     RECT  25.585 19.344 26.053 19.368 ;
     RECT  25.409 45.504 26.053 50.76 ;
     RECT  25.189 51.744 26.053 62.52 ;
     RECT  25.621 14.4 26.093 17.064 ;
     RECT  25.949 33.024 26.161 39.384 ;
     RECT  25.801 26.352 26.201 27.864 ;
     RECT  25.619 21.696 26.237 24.744 ;
     RECT  26.161 33.024 26.309 40.104 ;
     RECT  26.309 37.296 26.341 40.104 ;
     RECT  25.801 11.28 26.417 13.08 ;
     RECT  26.093 14.4 26.453 15.096 ;
     RECT  25.621 43.248 26.453 43.848 ;
     RECT  26.093 16.416 26.489 17.064 ;
     RECT  26.309 33.024 26.489 36.312 ;
     RECT  26.053 19.104 26.557 19.368 ;
     RECT  26.557 18.816 26.597 19.368 ;
     RECT  26.237 21.696 26.633 24.264 ;
     RECT  26.053 45.504 26.633 62.52 ;
     RECT  26.201 26.352 26.669 27.768 ;
     RECT  26.341 37.296 26.669 40.152 ;
     RECT  26.453 14.4 26.705 14.808 ;
     RECT  25.427 9.504 26.737 9.672 ;
     RECT  26.417 11.28 26.737 12.84 ;
     RECT  26.597 18.816 26.773 18.84 ;
     RECT  25.913 7.392 26.813 7.944 ;
     RECT  25.085 41.184 26.813 42.024 ;
     RECT  26.051 30.384 26.849 31.8 ;
     RECT  26.705 14.4 26.881 14.616 ;
     RECT  26.813 7.392 26.885 7.752 ;
     RECT  26.489 17.04 26.917 17.064 ;
     RECT  26.633 45.504 26.924 49.32 ;
     RECT  26.849 31.296 27.313 31.8 ;
     RECT  26.813 41.568 27.313 42.024 ;
     RECT  26.737 9.504 27.317 12.84 ;
     RECT  27.277 28.8 27.349 28.824 ;
     RECT  26.453 43.248 27.389 43.656 ;
     RECT  26.669 26.784 27.445 27.768 ;
     RECT  27.349 28.8 27.445 29.88 ;
     RECT  25.409 20.592 27.457 20.616 ;
     RECT  26.885 7.392 27.461 7.416 ;
     RECT  27.313 31.296 27.493 32.04 ;
     RECT  26.489 33.024 27.493 35.784 ;
     RECT  26.917 17.04 27.529 17.112 ;
     RECT  26.773 18.384 27.529 18.84 ;
     RECT  27.445 26.784 27.532 29.88 ;
     RECT  27.457 19.968 27.565 20.616 ;
     RECT  27.493 31.296 27.589 35.784 ;
     RECT  26.633 22.464 27.637 24.264 ;
     RECT  26.924 44.736 27.637 49.32 ;
     RECT  26.633 50.544 27.637 62.52 ;
     RECT  27.637 44.736 27.673 62.52 ;
     RECT  27.589 31.296 27.713 36.168 ;
     RECT  26.881 14.208 27.781 14.616 ;
     RECT  27.317 11.376 27.877 12.84 ;
     RECT  27.781 13.824 27.877 14.616 ;
     RECT  27.877 11.376 27.889 14.616 ;
     RECT  27.781 15.888 27.889 15.912 ;
     RECT  27.673 44.736 27.893 62.664 ;
     RECT  27.317 9.504 27.961 10.392 ;
     RECT  27.565 19.872 27.961 20.616 ;
     RECT  27.637 21.648 27.961 24.264 ;
     RECT  26.669 37.296 27.961 37.656 ;
     RECT  27.893 51.888 27.965 62.664 ;
     RECT  27.961 19.872 28.001 24.264 ;
     RECT  28.001 19.872 28.067 22.776 ;
     RECT  27.532 28.8 28.073 29.88 ;
     RECT  27.961 37.104 28.105 37.656 ;
     RECT  27.529 25.392 28.117 25.416 ;
     RECT  27.532 26.784 28.117 27.768 ;
     RECT  27.893 44.736 28.145 50.856 ;
     RECT  28.105 37.104 28.177 38.184 ;
     RECT  27.529 17.04 28.181 18.84 ;
     RECT  27.713 31.296 28.181 35.928 ;
     RECT  27.965 51.888 28.217 62.232 ;
     RECT  28.067 19.872 28.253 19.896 ;
     RECT  28.217 51.888 28.253 53.592 ;
     RECT  27.961 9.072 28.357 10.392 ;
     RECT  27.889 11.376 28.357 15.912 ;
     RECT  28.181 31.296 28.393 33.864 ;
     RECT  28.177 37.104 28.393 38.28 ;
     RECT  26.669 39.36 28.393 39.864 ;
     RECT  27.389 43.296 28.393 43.656 ;
     RECT  28.145 44.736 28.393 49.368 ;
     RECT  28.357 9.072 28.597 15.912 ;
     RECT  28.181 17.04 28.597 17.16 ;
     RECT  28.073 29.616 28.645 29.88 ;
     RECT  28.393 30.912 28.645 33.864 ;
     RECT  28.117 25.392 28.717 27.768 ;
     RECT  28.181 18.384 28.753 18.84 ;
     RECT  28.181 34.848 28.825 35.928 ;
     RECT  28.393 37.104 28.825 39.864 ;
     RECT  28.001 23.808 28.933 24.264 ;
     RECT  28.717 25.392 28.933 27.912 ;
     RECT  28.597 9.072 28.969 17.16 ;
     RECT  28.217 54.624 29.036 62.232 ;
     RECT  28.067 21.648 29.041 22.776 ;
     RECT  28.933 23.808 29.041 27.912 ;
     RECT  28.825 34.848 29.041 39.864 ;
     RECT  29.041 34.848 29.077 39.912 ;
     RECT  27.313 41.568 29.077 42.072 ;
     RECT  28.393 43.296 29.149 49.368 ;
     RECT  28.145 50.736 29.149 50.856 ;
     RECT  29.077 34.848 29.249 42.072 ;
     RECT  29.149 43.296 29.249 50.856 ;
     RECT  29.041 21.648 29.293 27.912 ;
     RECT  28.645 29.616 29.293 33.864 ;
     RECT  28.969 8.448 29.408 17.16 ;
     RECT  28.753 18.384 29.408 19.272 ;
     RECT  29.293 21.648 29.408 33.864 ;
     RECT  29.249 34.848 29.408 50.856 ;
     RECT  28.253 52.128 29.408 53.592 ;
     RECT  29.036 54.624 29.408 62.424 ;
     RECT  29.408 2.148 29.512 62.652 ;
     RECT  29.512 2.418 29.704 62.472 ;
     RECT  29.704 43.536 29.765 43.8 ;
     RECT  29.704 45.504 29.765 48.456 ;
     RECT  29.704 41.664 29.801 42.168 ;
     RECT  29.704 13.632 29.981 17.4 ;
     RECT  29.704 36.48 30.017 40.632 ;
     RECT  29.704 11.232 30.083 11.832 ;
     RECT  29.704 8.448 30.125 9.672 ;
     RECT  29.704 26.208 30.125 32.52 ;
     RECT  29.765 48.432 30.161 48.456 ;
     RECT  29.704 54.624 30.197 62.472 ;
     RECT  29.981 13.632 30.227 17.112 ;
     RECT  30.125 9.072 30.233 9.672 ;
     RECT  30.125 26.208 30.233 26.664 ;
     RECT  30.233 9.36 30.269 9.672 ;
     RECT  29.704 49.872 30.377 53.592 ;
     RECT  30.269 9.6 30.413 9.672 ;
     RECT  30.227 16.08 30.413 17.112 ;
     RECT  29.704 34.896 30.413 34.92 ;
     RECT  30.377 53.376 30.521 53.592 ;
     RECT  30.521 53.568 30.709 53.592 ;
     RECT  30.197 54.624 30.709 62.184 ;
     RECT  30.083 11.664 30.733 11.832 ;
     RECT  29.704 20.88 30.757 25.128 ;
     RECT  30.233 26.208 30.757 26.232 ;
     RECT  30.733 11.664 30.769 12.552 ;
     RECT  29.801 41.712 30.769 42.168 ;
     RECT  29.765 45.504 30.769 47.448 ;
     RECT  29.704 18.672 30.803 19.656 ;
     RECT  30.757 20.88 30.803 26.232 ;
     RECT  30.769 41.616 30.805 42.168 ;
     RECT  29.765 43.776 30.805 43.8 ;
     RECT  30.377 49.872 30.805 52.344 ;
     RECT  30.805 49.584 30.809 52.344 ;
     RECT  30.709 53.568 30.809 62.184 ;
     RECT  30.803 18.768 30.841 19.656 ;
     RECT  30.803 20.88 30.841 25.704 ;
     RECT  30.841 18.768 30.845 25.704 ;
     RECT  30.809 53.808 30.881 62.04 ;
     RECT  30.805 41.616 30.889 44.472 ;
     RECT  30.017 36.48 30.913 40.584 ;
     RECT  30.889 43.776 30.989 44.472 ;
     RECT  30.227 13.92 31.025 14.904 ;
     RECT  30.125 27.744 31.061 32.472 ;
     RECT  30.913 36.096 31.133 40.584 ;
     RECT  31.025 14.208 31.169 14.904 ;
     RECT  31.169 14.256 31.201 14.904 ;
     RECT  31.133 36.096 31.237 38.136 ;
     RECT  31.201 14.256 31.349 15 ;
     RECT  30.769 45.504 31.381 48.264 ;
     RECT  30.413 16.176 31.385 17.112 ;
     RECT  31.061 32.448 31.453 32.472 ;
     RECT  29.704 33.648 31.453 33.864 ;
     RECT  30.889 41.616 31.484 42.36 ;
     RECT  30.413 9.648 31.493 9.672 ;
     RECT  30.845 18.864 31.565 25.704 ;
     RECT  31.381 44.976 31.597 48.264 ;
     RECT  30.809 49.584 31.597 51.24 ;
     RECT  31.133 39.36 31.619 40.584 ;
     RECT  31.385 16.176 31.637 16.2 ;
     RECT  31.565 20.928 31.665 25.704 ;
     RECT  30.769 11.664 31.669 12.84 ;
     RECT  31.061 27.744 31.673 30.456 ;
     RECT  31.673 27.744 31.705 30.36 ;
     RECT  30.989 43.776 31.853 43.8 ;
     RECT  31.669 10.848 31.885 12.84 ;
     RECT  31.484 41.568 31.921 42.36 ;
     RECT  31.565 18.864 31.925 19.896 ;
     RECT  31.597 44.976 31.957 51.24 ;
     RECT  30.809 52.224 31.957 52.344 ;
     RECT  31.349 14.256 31.961 14.808 ;
     RECT  31.957 44.976 31.961 52.344 ;
     RECT  31.925 18.864 31.993 19.608 ;
     RECT  31.705 26.928 32.069 30.36 ;
     RECT  31.961 49.968 32.069 52.344 ;
     RECT  31.921 41.568 32.104 42.744 ;
     RECT  30.881 53.808 32.105 61.992 ;
     RECT  32.069 51.744 32.173 52.344 ;
     RECT  32.104 41.568 32.249 42.792 ;
     RECT  31.961 44.976 32.249 48.84 ;
     RECT  31.665 24.048 32.285 25.704 ;
     RECT  31.961 14.448 32.317 14.808 ;
     RECT  31.813 17.184 32.389 17.208 ;
     RECT  31.619 39.456 32.389 40.584 ;
     RECT  32.249 41.568 32.389 42.024 ;
     RECT  32.389 16.656 32.461 17.208 ;
     RECT  32.069 49.968 32.465 50.568 ;
     RECT  31.885 10.848 32.483 13.08 ;
     RECT  32.389 39.456 32.483 42.024 ;
     RECT  31.453 32.448 32.497 33.864 ;
     RECT  31.237 35.472 32.605 38.136 ;
     RECT  32.483 39.456 32.605 40.2 ;
     RECT  31.061 31.44 32.677 31.464 ;
     RECT  32.497 32.448 32.677 34.44 ;
     RECT  32.605 35.472 32.681 40.2 ;
     RECT  32.483 11.664 32.716 13.08 ;
     RECT  32.681 36.288 32.753 40.2 ;
     RECT  31.665 20.928 32.857 22.872 ;
     RECT  32.753 36.528 32.861 40.2 ;
     RECT  32.285 24.048 32.897 25.608 ;
     RECT  32.857 20.88 32.924 22.872 ;
     RECT  32.897 24.048 32.924 25.224 ;
     RECT  32.924 20.88 32.965 25.224 ;
     RECT  32.249 44.976 32.965 48.264 ;
     RECT  32.105 54.624 32.965 61.992 ;
     RECT  32.677 31.44 33.005 34.44 ;
     RECT  32.965 20.736 33.011 25.224 ;
     RECT  32.069 28.8 33.037 30.36 ;
     RECT  33.005 31.44 33.037 31.944 ;
     RECT  31.993 18.816 33.061 19.608 ;
     RECT  33.011 20.736 33.061 21.672 ;
     RECT  32.173 51.744 33.068 53.592 ;
     RECT  33.005 33.456 33.071 34.44 ;
     RECT  33.068 51.648 33.073 53.592 ;
     RECT  32.069 26.928 33.109 27.768 ;
     RECT  33.037 28.8 33.109 31.944 ;
     RECT  33.109 26.928 33.113 31.944 ;
     RECT  33.061 18.816 33.148 21.672 ;
     RECT  33.148 20.736 33.149 21.672 ;
     RECT  32.483 41.616 33.185 42.024 ;
     RECT  32.716 13.056 33.212 13.08 ;
     RECT  32.317 14.448 33.212 15.096 ;
     RECT  33.212 13.056 33.221 15.096 ;
     RECT  32.461 16.656 33.221 17.496 ;
     RECT  33.071 33.456 33.253 34.488 ;
     RECT  33.221 14.016 33.299 15.096 ;
     RECT  32.965 44.592 33.325 48.264 ;
     RECT  32.465 49.968 33.329 50.136 ;
     RECT  33.011 22.752 33.365 25.224 ;
     RECT  32.965 54.624 33.365 62.616 ;
     RECT  33.185 41.712 33.469 42.024 ;
     RECT  33.221 17.472 33.545 17.496 ;
     RECT  33.253 33.456 33.635 35.016 ;
     RECT  33.365 22.848 33.689 25.224 ;
     RECT  33.635 33.456 33.725 33.672 ;
     RECT  33.329 50.064 33.793 50.136 ;
     RECT  33.073 51.12 33.793 53.592 ;
     RECT  33.365 54.624 33.793 62.232 ;
     RECT  33.635 34.992 33.901 35.016 ;
     RECT  33.325 44.592 34.009 48.456 ;
     RECT  32.861 38.736 34.045 40.2 ;
     RECT  33.113 27.12 34.117 31.944 ;
     RECT  33.299 14.448 34.189 15.096 ;
     RECT  34.045 38.736 34.225 40.392 ;
     RECT  33.469 41.712 34.225 42.744 ;
     RECT  33.148 18.816 34.261 19.608 ;
     RECT  34.189 14.448 34.364 15.384 ;
     RECT  34.364 13.824 34.369 15.384 ;
     RECT  34.261 18.816 34.369 19.896 ;
     RECT  33.149 20.88 34.369 21.672 ;
     RECT  32.716 11.664 34.405 11.784 ;
     RECT  34.369 13.824 34.441 16.152 ;
     RECT  34.441 13.824 34.513 16.92 ;
     RECT  33.689 23.28 34.657 25.224 ;
     RECT  34.117 26.304 34.657 31.944 ;
     RECT  34.009 44.448 34.729 48.456 ;
     RECT  34.729 44.448 34.765 48.984 ;
     RECT  33.793 50.064 34.765 62.232 ;
     RECT  34.405 11.664 34.808 12.552 ;
     RECT  34.513 13.824 34.808 17.208 ;
     RECT  34.369 18.816 34.808 21.672 ;
     RECT  34.657 23.28 34.808 31.944 ;
     RECT  33.725 33.552 34.808 33.672 ;
     RECT  33.901 34.992 34.808 35.304 ;
     RECT  32.861 36.528 34.808 37.464 ;
     RECT  34.225 38.736 34.808 42.744 ;
     RECT  34.765 44.448 34.808 62.232 ;
     RECT  34.808 2.148 34.912 62.652 ;
     RECT  34.912 2.418 35.104 62.52 ;
     RECT  35.104 36.528 35.165 39.864 ;
     RECT  35.104 51.36 35.165 62.52 ;
     RECT  35.165 51.36 35.201 51.384 ;
     RECT  35.104 15.552 35.219 15.576 ;
     RECT  35.104 18.72 35.381 21.672 ;
     RECT  35.104 24.144 35.381 30.072 ;
     RECT  35.381 29.04 35.453 30.072 ;
     RECT  35.165 36.528 35.453 39.336 ;
     RECT  35.104 33.552 35.555 34.152 ;
     RECT  35.104 31.392 35.596 32.472 ;
     RECT  35.104 16.56 35.597 17.208 ;
     RECT  35.381 24.144 35.603 27.912 ;
     RECT  35.453 36.528 35.633 38.76 ;
     RECT  35.633 36.624 35.669 38.76 ;
     RECT  35.597 16.896 35.705 17.208 ;
     RECT  35.104 40.896 35.777 43.368 ;
     RECT  35.165 55.968 35.881 62.52 ;
     RECT  35.104 11.712 35.891 12.936 ;
     RECT  35.603 25.2 35.993 27.912 ;
     RECT  35.453 30.048 35.993 30.072 ;
     RECT  35.669 36.864 35.993 38.76 ;
     RECT  35.381 20.304 36.029 21.672 ;
     RECT  35.891 11.712 36.085 12.552 ;
     RECT  35.993 25.2 36.137 26.088 ;
     RECT  35.596 31.392 36.137 31.464 ;
     RECT  35.104 44.976 36.169 48.984 ;
     RECT  35.104 49.968 36.169 50.088 ;
     RECT  36.085 11.52 36.173 12.552 ;
     RECT  36.137 25.872 36.173 26.088 ;
     RECT  36.169 44.976 36.197 50.088 ;
     RECT  35.603 24.144 36.205 24.168 ;
     RECT  35.165 52.416 36.205 54.552 ;
     RECT  35.993 27.168 36.209 27.912 ;
     RECT  35.555 33.792 36.313 34.152 ;
     RECT  36.197 44.976 36.421 50.136 ;
     RECT  36.205 52.224 36.421 54.552 ;
     RECT  35.881 55.968 36.421 62.568 ;
     RECT  36.029 21.408 36.425 21.672 ;
     RECT  35.777 41.568 36.497 43.368 ;
     RECT  35.104 14.448 36.533 14.472 ;
     RECT  35.453 29.04 36.533 29.064 ;
     RECT  36.421 44.448 36.677 50.136 ;
     RECT  36.421 51.984 36.677 54.552 ;
     RECT  36.677 45.696 36.745 50.136 ;
     RECT  36.497 41.568 36.764 41.592 ;
     RECT  35.993 36.864 36.851 37.464 ;
     RECT  36.764 41.04 36.857 41.592 ;
     RECT  36.173 11.52 36.893 11.976 ;
     RECT  35.993 38.736 36.893 38.76 ;
     RECT  35.705 17.184 36.997 17.208 ;
     RECT  36.745 45.696 37.037 50.184 ;
     RECT  36.997 17.088 37.043 17.208 ;
     RECT  35.596 32.448 37.045 32.472 ;
     RECT  36.313 33.792 37.045 34.536 ;
     RECT  36.137 31.44 37.1 31.464 ;
     RECT  37.045 32.448 37.1 34.536 ;
     RECT  36.497 42.72 37.109 43.368 ;
     RECT  36.677 51.984 37.109 52.776 ;
     RECT  37.043 17.088 37.141 17.112 ;
     RECT  37.1 31.44 37.145 34.536 ;
     RECT  36.421 55.824 37.145 62.568 ;
     RECT  36.029 20.304 37.177 20.328 ;
     RECT  36.677 53.808 37.177 54.552 ;
     RECT  37.141 16.896 37.187 17.112 ;
     RECT  37.145 31.44 37.187 33.912 ;
     RECT  37.177 20.304 37.217 20.616 ;
     RECT  36.805 35.856 37.217 35.88 ;
     RECT  37.037 46.224 37.217 50.184 ;
     RECT  36.173 25.872 37.244 25.896 ;
     RECT  37.217 50.064 37.249 50.184 ;
     RECT  37.187 16.896 37.285 16.92 ;
     RECT  37.244 25.296 37.285 25.896 ;
     RECT  37.249 50.064 37.321 50.376 ;
     RECT  35.381 18.72 37.325 18.744 ;
     RECT  37.141 40.896 37.325 40.92 ;
     RECT  36.425 21.648 37.357 21.672 ;
     RECT  37.145 55.824 37.357 62.52 ;
     RECT  37.321 50.064 37.501 50.472 ;
     RECT  36.209 27.312 37.505 27.912 ;
     RECT  37.177 53.808 37.613 54.744 ;
     RECT  36.205 24.096 37.649 24.168 ;
     RECT  37.109 52.224 37.681 52.776 ;
     RECT  37.613 53.808 37.681 53.88 ;
     RECT  37.357 55.728 37.681 62.52 ;
     RECT  36.893 11.52 37.685 11.784 ;
     RECT  37.645 31.392 37.717 31.416 ;
     RECT  37.285 25.296 37.721 26.232 ;
     RECT  37.217 46.224 37.721 49.08 ;
     RECT  37.721 46.272 37.757 49.08 ;
     RECT  36.637 22.8 37.793 22.824 ;
     RECT  37.357 21.648 37.825 21.816 ;
     RECT  37.141 39.888 37.825 39.912 ;
     RECT  37.501 50.064 37.825 50.568 ;
     RECT  36.851 37.008 37.937 37.464 ;
     RECT  37.721 25.296 38.005 25.464 ;
     RECT  37.825 39.6 38.005 39.912 ;
     RECT  37.964 38.064 38.051 38.088 ;
     RECT  36.677 44.448 38.077 44.472 ;
     RECT  38.005 39.216 38.081 39.912 ;
     RECT  37.685 11.52 38.189 11.544 ;
     RECT  38.005 25.056 38.243 25.464 ;
     RECT  37.825 19.248 38.257 19.272 ;
     RECT  37.217 20.592 38.257 20.616 ;
     RECT  38.077 44.112 38.297 44.472 ;
     RECT  37.285 16.56 38.3 16.92 ;
     RECT  38.081 39.216 38.333 39.624 ;
     RECT  38.3 16.224 38.341 16.92 ;
     RECT  38.077 12.528 38.369 13.128 ;
     RECT  38.321 14.784 38.405 14.808 ;
     RECT  37.681 55.104 38.513 62.52 ;
     RECT  37.717 30.576 38.533 31.416 ;
     RECT  38.533 30.192 38.579 31.416 ;
     RECT  37.757 46.272 38.585 47.928 ;
     RECT  38.509 29.04 38.593 29.064 ;
     RECT  38.257 19.248 38.657 20.616 ;
     RECT  37.109 42.72 38.697 42.792 ;
     RECT  38.297 44.112 38.697 44.136 ;
     RECT  37.357 35.328 38.725 35.352 ;
     RECT  37.825 50.064 38.725 50.712 ;
     RECT  37.505 27.312 38.761 27.336 ;
     RECT  38.725 35.328 38.765 35.976 ;
     RECT  38.725 50.064 38.797 51 ;
     RECT  37.681 52.224 38.797 53.88 ;
     RECT  37.937 37.008 38.801 37.032 ;
     RECT  38.697 42.72 38.809 44.136 ;
     RECT  38.341 15.84 38.833 16.92 ;
     RECT  37.187 32.592 38.833 33.912 ;
     RECT  38.579 31.392 38.837 31.416 ;
     RECT  37.825 21.648 38.869 21.96 ;
     RECT  38.765 35.952 38.873 35.976 ;
     RECT  38.333 39.216 38.873 39.24 ;
     RECT  38.809 44.112 38.873 44.136 ;
     RECT  38.833 32.496 38.905 33.912 ;
     RECT  37.757 49.056 38.941 49.08 ;
     RECT  38.797 50.064 38.941 53.88 ;
     RECT  38.972 41.568 39.013 41.592 ;
     RECT  38.809 42.72 39.013 43.128 ;
     RECT  38.369 12.528 39.053 12.552 ;
     RECT  38.833 15.84 39.121 17.64 ;
     RECT  38.585 46.656 39.193 47.928 ;
     RECT  38.941 49.056 39.193 53.88 ;
     RECT  38.657 19.248 39.205 19.8 ;
     RECT  38.579 30.192 39.229 30.216 ;
     RECT  39.193 46.656 39.229 53.88 ;
     RECT  39.013 41.568 39.265 43.128 ;
     RECT  38.243 25.392 39.301 25.464 ;
     RECT  39.301 25.392 39.397 26.232 ;
     RECT  39.229 46.656 39.589 54.456 ;
     RECT  38.513 55.968 39.625 62.52 ;
     RECT  39.589 46.656 39.661 54.648 ;
     RECT  39.397 24.624 39.697 26.232 ;
     RECT  38.761 27.312 39.697 28.056 ;
     RECT  38.581 11.424 39.733 11.448 ;
     RECT  39.121 15.552 39.829 17.64 ;
     RECT  39.205 18.96 39.829 19.8 ;
     RECT  39.349 38.16 39.829 38.184 ;
     RECT  38.869 21.648 39.836 22.248 ;
     RECT  39.836 20.832 39.877 22.248 ;
     RECT  39.397 23.52 39.877 23.544 ;
     RECT  39.229 29.232 39.973 30.216 ;
     RECT  38.905 32.496 39.985 34.728 ;
     RECT  39.733 11.424 40.069 11.688 ;
     RECT  39.973 29.232 40.093 30.936 ;
     RECT  39.985 32.304 40.093 34.728 ;
     RECT  40.093 29.232 40.129 34.728 ;
     RECT  40.069 11.424 40.165 12.504 ;
     RECT  39.301 13.68 40.165 13.704 ;
     RECT  39.829 38.16 40.201 38.712 ;
     RECT  39.985 10.224 40.208 10.248 ;
     RECT  40.165 11.424 40.208 13.704 ;
     RECT  39.829 15.552 40.208 19.8 ;
     RECT  39.877 20.832 40.208 23.544 ;
     RECT  39.697 24.624 40.208 28.056 ;
     RECT  40.129 29.232 40.208 34.92 ;
     RECT  39.301 36.576 40.208 36.696 ;
     RECT  40.201 38.16 40.208 38.808 ;
     RECT  39.265 40.608 40.208 43.128 ;
     RECT  40.057 45.168 40.208 45.192 ;
     RECT  39.661 46.656 40.208 54.744 ;
     RECT  39.625 55.968 40.208 62.568 ;
     RECT  40.208 2.148 40.312 62.652 ;
     RECT  40.312 2.418 40.504 62.568 ;
     RECT  40.504 26.784 40.673 26.808 ;
     RECT  40.504 45.168 40.745 45.72 ;
     RECT  40.504 55.968 40.781 62.568 ;
     RECT  40.504 30.816 40.817 32.328 ;
     RECT  40.745 45.168 40.889 45.192 ;
     RECT  40.504 18.192 41.357 18.744 ;
     RECT  40.504 19.776 41.393 22.776 ;
     RECT  41.357 18.192 41.497 18.264 ;
     RECT  40.504 40.608 41.497 43.128 ;
     RECT  40.504 27.936 41.533 29.112 ;
     RECT  40.504 9.696 41.569 11.688 ;
     RECT  40.504 13.104 41.605 13.128 ;
     RECT  40.504 14.496 41.605 14.952 ;
     RECT  40.504 16.656 41.605 16.92 ;
     RECT  41.497 18.144 41.605 18.264 ;
     RECT  41.605 13.104 41.609 14.952 ;
     RECT  41.609 13.248 41.701 14.952 ;
     RECT  41.533 27.936 41.708 29.784 ;
     RECT  40.781 55.968 41.749 62.472 ;
     RECT  40.504 24.624 41.753 25.08 ;
     RECT  40.504 47.088 41.753 54.936 ;
     RECT  41.708 27.6 41.785 29.784 ;
     RECT  41.785 26.736 41.795 29.784 ;
     RECT  41.497 40.176 41.821 43.128 ;
     RECT  41.749 55.92 41.857 62.472 ;
     RECT  40.504 38.784 41.893 38.808 ;
     RECT  41.821 39.888 41.893 43.128 ;
     RECT  41.393 20.112 41.897 22.776 ;
     RECT  41.893 38.784 41.929 43.128 ;
     RECT  40.504 33.888 41.933 37.272 ;
     RECT  41.569 9.696 41.969 11.928 ;
     RECT  41.753 47.088 41.969 54.744 ;
     RECT  41.933 33.888 41.977 37.08 ;
     RECT  41.969 47.088 42.001 48.744 ;
     RECT  41.969 9.936 42.005 11.928 ;
     RECT  42.001 46.656 42.073 48.744 ;
     RECT  41.977 33.888 42.109 36.456 ;
     RECT  41.897 20.112 42.113 20.424 ;
     RECT  41.897 21.408 42.133 22.776 ;
     RECT  40.817 31.44 42.153 32.328 ;
     RECT  42.005 9.936 42.179 9.96 ;
     RECT  42.005 11.28 42.179 11.928 ;
     RECT  42.109 33.744 42.185 36.456 ;
     RECT  42.133 21.408 42.22 23.736 ;
     RECT  41.701 13.248 42.229 15.624 ;
     RECT  41.605 16.656 42.229 18.264 ;
     RECT  42.153 31.152 42.253 32.328 ;
     RECT  42.229 13.248 42.257 18.264 ;
     RECT  42.257 14.4 42.275 18.264 ;
     RECT  42.275 14.4 42.293 17.112 ;
     RECT  42.073 46.272 42.332 48.744 ;
     RECT  42.185 34.896 42.365 36.456 ;
     RECT  41.929 38.736 42.401 43.128 ;
     RECT  42.253 44.976 42.419 45 ;
     RECT  42.332 46.08 42.419 48.744 ;
     RECT  42.253 31.152 42.509 32.472 ;
     RECT  41.795 29.328 42.517 29.784 ;
     RECT  42.509 31.152 42.517 32.328 ;
     RECT  42.293 14.4 42.545 15.864 ;
     RECT  41.969 49.776 42.545 54.744 ;
     RECT  42.401 38.736 42.685 41.448 ;
     RECT  42.517 29.328 42.689 32.328 ;
     RECT  42.401 42.816 42.725 43.128 ;
     RECT  42.293 16.896 42.755 17.112 ;
     RECT  42.179 11.28 42.761 11.4 ;
     RECT  42.419 46.272 42.761 48.744 ;
     RECT  41.857 55.872 42.793 62.472 ;
     RECT  42.755 17.088 42.797 17.112 ;
     RECT  42.275 18.24 42.797 18.264 ;
     RECT  42.365 34.896 42.797 36.312 ;
     RECT  42.761 11.376 42.833 11.4 ;
     RECT  42.761 46.656 42.833 48.744 ;
     RECT  42.545 51.12 42.833 54.744 ;
     RECT  42.22 21.408 42.869 22.824 ;
     RECT  42.833 46.752 42.941 48.744 ;
     RECT  41.795 27.936 42.949 27.96 ;
     RECT  42.689 29.328 42.949 31.416 ;
     RECT  42.865 23.808 43.013 23.832 ;
     RECT  42.949 27.936 43.045 31.416 ;
     RECT  42.113 20.304 43.117 20.424 ;
     RECT  42.793 55.872 43.193 62.616 ;
     RECT  43.117 20.112 43.229 20.424 ;
     RECT  42.797 35.904 43.34 36.312 ;
     RECT  42.725 42.816 43.369 42.84 ;
     RECT  43.229 20.112 43.373 20.136 ;
     RECT  42.685 38.16 43.379 41.448 ;
     RECT  43.379 39.216 43.381 41.448 ;
     RECT  43.369 42.528 43.381 42.84 ;
     RECT  41.795 26.736 43.405 26.76 ;
     RECT  43.045 27.888 43.405 31.416 ;
     RECT  43.405 26.736 43.409 31.416 ;
     RECT  43.34 35.904 43.427 37.032 ;
     RECT  42.185 33.744 43.441 33.912 ;
     RECT  42.797 34.896 43.441 34.92 ;
     RECT  43.369 43.968 43.477 43.992 ;
     RECT  42.941 47.088 43.477 48.744 ;
     RECT  42.545 49.776 43.477 50.136 ;
     RECT  43.381 39.216 43.481 42.84 ;
     RECT  43.484 10.272 43.485 10.296 ;
     RECT  42.545 14.4 43.549 15.72 ;
     RECT  43.441 33.744 43.549 34.92 ;
     RECT  43.409 26.88 43.589 31.416 ;
     RECT  43.193 60.144 43.625 62.616 ;
     RECT  42.869 21.408 43.657 22.776 ;
     RECT  43.388 23.904 43.667 23.928 ;
     RECT  43.369 12.384 43.693 12.408 ;
     RECT  43.481 39.216 43.697 42.792 ;
     RECT  41.753 24.912 43.717 25.08 ;
     RECT  43.477 43.968 43.729 44.568 ;
     RECT  43.729 43.92 43.765 44.568 ;
     RECT  43.477 47.088 43.811 50.136 ;
     RECT  43.693 12.384 43.82 12.744 ;
     RECT  43.549 13.728 43.82 15.72 ;
     RECT  43.811 47.856 43.868 50.136 ;
     RECT  42.833 51.312 43.868 54.744 ;
     RECT  43.717 24.912 43.877 25.704 ;
     RECT  43.765 43.92 43.885 44.808 ;
     RECT  43.82 12.384 43.909 15.72 ;
     RECT  43.549 33.648 43.909 34.92 ;
     RECT  43.427 35.904 43.909 36.12 ;
     RECT  43.485 9.504 43.913 10.296 ;
     RECT  43.909 12.048 43.945 15.72 ;
     RECT  43.589 31.392 43.945 31.416 ;
     RECT  43.589 26.88 43.955 30.168 ;
     RECT  43.868 47.856 43.985 54.744 ;
     RECT  43.945 31.392 44.012 32.088 ;
     RECT  43.909 33.648 44.012 36.12 ;
     RECT  43.955 26.88 44.099 29.064 ;
     RECT  43.657 21.12 44.161 22.776 ;
     RECT  43.379 38.16 44.197 38.232 ;
     RECT  43.697 40.368 44.243 42.792 ;
     RECT  43.877 24.912 44.245 25.608 ;
     RECT  44.161 21.12 44.291 23.208 ;
     RECT  43.193 55.872 44.305 59.112 ;
     RECT  43.625 60.144 44.305 62.28 ;
     RECT  43.549 19.536 44.341 19.56 ;
     RECT  44.291 21.12 44.341 22.776 ;
     RECT  44.125 46.08 44.341 46.104 ;
     RECT  44.245 24.672 44.345 25.608 ;
     RECT  43.729 17.616 44.377 17.64 ;
     RECT  44.197 37.632 44.377 38.232 ;
     RECT  43.697 39.216 44.377 39.336 ;
     RECT  44.345 24.912 44.387 25.608 ;
     RECT  44.012 31.392 44.453 36.12 ;
     RECT  43.945 12.048 44.483 16.488 ;
     RECT  43.985 47.856 44.483 49.368 ;
     RECT  44.483 12.048 44.485 16.392 ;
     RECT  44.485 11.712 44.489 16.392 ;
     RECT  44.243 40.848 44.489 42.792 ;
     RECT  44.377 17.616 44.593 18.264 ;
     RECT  44.341 19.536 44.593 22.776 ;
     RECT  43.985 50.64 44.593 54.744 ;
     RECT  44.593 50.64 44.881 54.888 ;
     RECT  44.305 55.872 44.881 62.28 ;
     RECT  44.341 45.216 45.025 46.344 ;
     RECT  43.885 43.92 45.068 43.992 ;
     RECT  45.068 43.872 45.109 43.992 ;
     RECT  45.025 45.216 45.109 46.584 ;
     RECT  44.099 26.88 45.205 29.016 ;
     RECT  43.955 30.144 45.205 30.168 ;
     RECT  44.489 42.768 45.205 42.792 ;
     RECT  45.109 43.872 45.205 46.584 ;
     RECT  43.913 9.504 45.313 10.248 ;
     RECT  44.387 25.248 45.385 25.608 ;
     RECT  44.453 31.392 45.452 31.8 ;
     RECT  44.453 32.88 45.452 36.12 ;
     RECT  44.881 50.64 45.457 62.28 ;
     RECT  45.452 31.392 45.493 36.12 ;
     RECT  45.493 23.952 45.565 23.976 ;
     RECT  45.385 25.248 45.565 25.848 ;
     RECT  44.489 40.848 45.565 41.4 ;
     RECT  45.313 9.504 45.608 10.392 ;
     RECT  44.489 11.712 45.608 11.736 ;
     RECT  44.489 12.72 45.608 16.392 ;
     RECT  44.593 17.616 45.608 22.776 ;
     RECT  45.565 23.904 45.608 25.848 ;
     RECT  45.205 26.88 45.608 30.168 ;
     RECT  45.493 31.2 45.608 36.12 ;
     RECT  44.377 37.632 45.608 39.336 ;
     RECT  45.565 40.656 45.608 41.4 ;
     RECT  45.205 42.768 45.608 46.584 ;
     RECT  44.483 48 45.608 49.368 ;
     RECT  45.457 50.64 45.608 62.376 ;
     RECT  45.608 2.148 45.712 62.652 ;
     RECT  45.712 2.418 45.904 62.382 ;
     RECT  45.904 19.536 46.001 20.376 ;
     RECT  45.904 28.464 46.019 30.168 ;
     RECT  45.904 34.752 46.019 41.4 ;
     RECT  45.904 21.408 46.073 27.336 ;
     RECT  46.019 34.752 46.109 37.224 ;
     RECT  45.904 44.112 46.109 62.382 ;
     RECT  45.904 13.056 46.115 14.952 ;
     RECT  46.073 21.408 46.115 21.672 ;
     RECT  45.904 16.272 46.145 18.264 ;
     RECT  46.109 34.752 46.145 37.032 ;
     RECT  46.019 38.4 46.163 41.4 ;
     RECT  46.001 19.776 46.204 20.376 ;
     RECT  46.073 22.752 46.217 27.336 ;
     RECT  45.904 9.504 46.253 12.024 ;
     RECT  46.217 22.752 46.253 26.04 ;
     RECT  46.217 27.312 46.325 27.336 ;
     RECT  46.253 22.752 46.361 22.776 ;
     RECT  46.204 20.16 46.397 20.376 ;
     RECT  45.904 31.2 46.397 32.232 ;
     RECT  46.115 13.056 46.505 13.08 ;
     RECT  46.115 14.16 46.505 14.424 ;
     RECT  46.253 9.504 46.541 9.528 ;
     RECT  46.145 16.272 46.547 18.216 ;
     RECT  46.109 44.112 46.613 55.224 ;
     RECT  46.145 34.752 46.643 36.552 ;
     RECT  46.163 38.4 46.649 38.568 ;
     RECT  46.613 44.448 46.691 55.224 ;
     RECT  46.109 56.784 46.717 62.382 ;
     RECT  46.163 40.272 46.787 41.4 ;
     RECT  46.253 23.952 46.793 26.04 ;
     RECT  46.019 28.464 46.793 29.928 ;
     RECT  46.793 28.464 46.829 29.64 ;
     RECT  46.787 40.56 46.865 41.4 ;
     RECT  46.691 47.664 46.937 55.224 ;
     RECT  46.691 44.448 47.081 46.584 ;
     RECT  46.865 40.848 47.18 41.4 ;
     RECT  47.18 40.848 47.221 41.592 ;
     RECT  45.904 42.72 47.221 42.744 ;
     RECT  46.397 20.352 47.293 20.376 ;
     RECT  46.115 21.648 47.293 21.672 ;
     RECT  47.293 20.352 47.333 21.672 ;
     RECT  46.643 34.8 47.333 36.552 ;
     RECT  46.505 14.16 47.369 14.184 ;
     RECT  47.333 34.8 47.405 36.264 ;
     RECT  46.547 16.272 47.437 17.064 ;
     RECT  46.793 23.952 47.477 25.848 ;
     RECT  47.221 40.848 47.477 43.416 ;
     RECT  46.717 56.784 47.509 62.424 ;
     RECT  46.649 38.4 47.545 38.424 ;
     RECT  47.437 15.84 47.549 17.064 ;
     RECT  46.937 47.664 47.549 49.608 ;
     RECT  46.897 27.6 47.581 27.864 ;
     RECT  47.545 37.536 47.729 38.424 ;
     RECT  46.937 51.12 47.801 55.224 ;
     RECT  47.509 56.4 47.843 62.424 ;
     RECT  47.581 26.832 47.845 27.864 ;
     RECT  46.829 29.04 47.845 29.64 ;
     RECT  46.253 11.136 47.852 12.024 ;
     RECT  46.397 32.208 47.869 32.232 ;
     RECT  47.081 44.448 47.869 45.528 ;
     RECT  47.801 51.12 47.873 55.176 ;
     RECT  47.843 56.4 47.873 62.28 ;
     RECT  47.852 11.136 47.893 12.216 ;
     RECT  47.477 40.848 47.893 43.128 ;
     RECT  47.845 26.832 47.909 29.64 ;
     RECT  47.873 56.4 47.909 61.896 ;
     RECT  47.909 26.832 47.932 29.544 ;
     RECT  47.932 29.04 47.945 29.544 ;
     RECT  47.893 40.416 47.945 43.128 ;
     RECT  47.873 51.12 47.989 54.888 ;
     RECT  47.869 32.208 48.044 32.52 ;
     RECT  47.893 10.848 48.053 12.216 ;
     RECT  48.053 11.76 48.085 12.216 ;
     RECT  47.473 13.632 48.085 13.656 ;
     RECT  47.081 46.56 48.085 46.584 ;
     RECT  47.549 47.664 48.085 48.744 ;
     RECT  47.989 50.592 48.121 54.888 ;
     RECT  48.044 31.872 48.131 32.52 ;
     RECT  47.941 33.648 48.157 33.672 ;
     RECT  47.405 34.8 48.157 36.12 ;
     RECT  47.945 29.04 48.161 29.304 ;
     RECT  47.909 56.544 48.179 61.896 ;
     RECT  47.893 9.648 48.233 9.672 ;
     RECT  46.547 18.144 48.265 18.216 ;
     RECT  47.477 24.096 48.265 25.848 ;
     RECT  47.932 26.832 48.265 27.864 ;
     RECT  47.333 20.352 48.337 21.336 ;
     RECT  48.179 57.072 48.341 61.896 ;
     RECT  47.945 40.416 48.377 43.08 ;
     RECT  48.157 33.648 48.428 36.12 ;
     RECT  47.977 22.608 48.445 22.632 ;
     RECT  47.869 44.16 48.445 45.528 ;
     RECT  48.445 44.064 48.449 45.528 ;
     RECT  48.377 40.416 48.467 41.592 ;
     RECT  48.449 45.408 48.469 45.528 ;
     RECT  48.085 46.56 48.469 48.744 ;
     RECT  48.428 33.6 48.515 36.12 ;
     RECT  48.337 20.064 48.517 21.336 ;
     RECT  48.445 22.608 48.517 22.728 ;
     RECT  48.515 34.512 48.517 36.12 ;
     RECT  47.729 37.536 48.517 37.56 ;
     RECT  48.161 29.184 48.521 29.304 ;
     RECT  48.157 39.408 48.553 39.432 ;
     RECT  48.517 20.064 48.557 22.728 ;
     RECT  48.469 45.408 48.557 48.744 ;
     RECT  48.085 11.76 48.593 13.656 ;
     RECT  48.517 34.512 48.593 37.56 ;
     RECT  48.341 57.072 48.593 61.8 ;
     RECT  48.265 18.144 48.613 18.264 ;
     RECT  48.593 12.72 48.661 13.656 ;
     RECT  47.549 15.84 48.661 16.536 ;
     RECT  48.557 22.176 48.661 22.728 ;
     RECT  48.265 24.096 48.661 27.864 ;
     RECT  48.613 17.616 48.7 18.264 ;
     RECT  48.661 22.176 48.707 27.864 ;
     RECT  48.593 34.56 48.709 37.56 ;
     RECT  48.553 38.64 48.709 39.432 ;
     RECT  48.121 50.112 48.709 54.888 ;
     RECT  48.709 34.56 48.755 39.432 ;
     RECT  48.661 12.72 48.805 14.232 ;
     RECT  48.557 46.56 48.845 48.744 ;
     RECT  48.557 20.064 48.949 20.568 ;
     RECT  48.521 29.232 48.949 29.304 ;
     RECT  48.057 30.576 48.949 30.6 ;
     RECT  48.845 47.04 48.985 48.744 ;
     RECT  48.709 50.016 48.985 54.888 ;
     RECT  48.707 22.608 48.995 27.864 ;
     RECT  48.7 18.144 49.061 18.264 ;
     RECT  48.131 32.208 49.061 32.52 ;
     RECT  48.593 57.072 49.061 61.752 ;
     RECT  48.805 12.72 49.093 14.472 ;
     RECT  48.661 15.84 49.093 16.584 ;
     RECT  49.093 12.72 49.169 16.584 ;
     RECT  48.589 10.752 49.237 10.776 ;
     RECT  49.237 10.752 49.283 11.352 ;
     RECT  49.169 15.36 49.309 16.584 ;
     RECT  48.985 47.04 49.493 54.888 ;
     RECT  49.061 61.728 49.493 61.752 ;
     RECT  48.467 40.416 49.525 41.208 ;
     RECT  49.283 11.328 49.561 11.352 ;
     RECT  49.309 15.36 49.571 16.872 ;
     RECT  48.949 29.232 49.597 30.6 ;
     RECT  49.525 40.176 49.597 41.208 ;
     RECT  49.561 11.328 49.601 11.448 ;
     RECT  48.377 43.056 49.705 43.08 ;
     RECT  48.949 19.344 49.717 20.568 ;
     RECT  49.717 19.344 49.741 21.144 ;
     RECT  48.995 22.608 49.741 24.216 ;
     RECT  48.755 34.56 49.741 38.952 ;
     RECT  49.597 40.176 49.741 41.496 ;
     RECT  49.597 28.896 49.777 30.6 ;
     RECT  49.597 31.728 49.777 31.752 ;
     RECT  49.741 34.56 49.777 41.496 ;
     RECT  48.449 44.064 49.777 44.184 ;
     RECT  49.601 11.424 49.849 11.448 ;
     RECT  49.169 12.72 49.849 13.512 ;
     RECT  49.061 57.072 49.849 60.552 ;
     RECT  49.493 47.04 49.925 47.304 ;
     RECT  49.849 56.976 49.925 60.552 ;
     RECT  49.493 48.432 49.961 54.888 ;
     RECT  49.525 32.784 50.101 32.808 ;
     RECT  50.101 32.784 50.108 33.096 ;
     RECT  49.777 34.176 50.108 41.496 ;
     RECT  49.777 28.896 50.137 31.752 ;
     RECT  48.557 45.408 50.137 45.528 ;
     RECT  49.705 42.816 50.173 43.08 ;
     RECT  49.777 44.064 50.173 44.376 ;
     RECT  50.173 42.816 50.209 44.376 ;
     RECT  50.137 45.408 50.209 45.72 ;
     RECT  50.137 28.896 50.245 31.8 ;
     RECT  50.108 32.784 50.245 41.496 ;
     RECT  49.925 56.976 50.245 60.168 ;
     RECT  49.961 51.12 50.353 54.888 ;
     RECT  50.245 56.688 50.353 60.168 ;
     RECT  49.741 19.344 50.389 24.216 ;
     RECT  48.995 25.248 50.389 27.864 ;
     RECT  49.849 11.424 50.725 13.512 ;
     RECT  50.389 19.344 50.773 27.864 ;
     RECT  50.245 28.896 50.773 41.496 ;
     RECT  50.209 42.816 50.857 45.72 ;
     RECT  50.773 19.344 50.929 41.496 ;
     RECT  50.725 11.424 51.008 14.232 ;
     RECT  49.571 15.984 51.008 16.872 ;
     RECT  49.061 18.144 51.008 18.168 ;
     RECT  50.929 19.248 51.008 41.496 ;
     RECT  50.857 42.576 51.008 45.72 ;
     RECT  49.925 47.04 51.008 47.064 ;
     RECT  49.961 48.432 51.008 50.136 ;
     RECT  50.353 51.12 51.008 60.168 ;
     RECT  51.008 2.148 51.112 62.652 ;
     RECT  51.112 2.418 51.304 62.382 ;
     RECT  51.304 15.696 51.437 19.368 ;
     RECT  51.304 58.464 51.437 59.208 ;
     RECT  51.437 19.248 51.443 19.368 ;
     RECT  51.304 26.64 51.443 37.08 ;
     RECT  51.437 15.696 51.481 18.024 ;
     RECT  51.304 48.912 51.587 55.8 ;
     RECT  51.437 58.464 51.587 58.968 ;
     RECT  51.443 26.64 51.725 34.104 ;
     RECT  51.304 38.16 51.869 42.744 ;
     RECT  51.481 18 52.085 18.024 ;
     RECT  51.587 48.912 52.265 50.136 ;
     RECT  51.481 15.696 52.268 17.016 ;
     RECT  52.265 50.064 52.337 50.136 ;
     RECT  51.304 47.04 52.369 47.064 ;
     RECT  51.304 20.928 52.405 25.464 ;
     RECT  51.443 35.088 52.441 37.08 ;
     RECT  51.869 38.16 52.441 39.912 ;
     RECT  52.369 46.848 52.441 47.064 ;
     RECT  51.304 57.024 52.441 57.096 ;
     RECT  51.869 41.184 52.501 42.744 ;
     RECT  51.304 43.824 52.501 43.848 ;
     RECT  52.501 41.184 52.547 43.848 ;
     RECT  52.547 42.816 52.549 43.848 ;
     RECT  51.304 44.88 52.549 45.528 ;
     RECT  52.547 41.184 52.589 41.832 ;
     RECT  52.549 42.816 52.589 45.528 ;
     RECT  52.589 41.52 52.595 41.832 ;
     RECT  51.304 14.208 52.657 14.232 ;
     RECT  51.587 58.464 52.657 58.824 ;
     RECT  52.441 57.024 52.661 57.144 ;
     RECT  52.265 48.912 52.693 49.032 ;
     RECT  51.725 26.784 52.732 34.104 ;
     RECT  52.657 58.464 52.801 59.112 ;
     RECT  52.405 20.928 52.805 25.752 ;
     RECT  51.304 12.288 52.837 12.312 ;
     RECT  52.657 13.296 52.837 14.232 ;
     RECT  51.443 19.248 52.837 19.272 ;
     RECT  52.441 35.088 52.841 39.912 ;
     RECT  52.589 44.304 52.873 45.528 ;
     RECT  52.693 48.384 52.876 49.032 ;
     RECT  52.876 48.384 52.877 48.936 ;
     RECT  52.268 15.648 52.981 17.016 ;
     RECT  52.805 20.928 52.981 20.952 ;
     RECT  51.587 51.12 52.981 55.752 ;
     RECT  52.841 39.6 53.017 39.912 ;
     RECT  52.873 44.304 53.017 45.768 ;
     RECT  52.441 46.752 53.017 47.064 ;
     RECT  52.661 57.072 53.017 57.144 ;
     RECT  52.801 58.464 53.017 59.352 ;
     RECT  52.837 12.288 53.053 14.232 ;
     RECT  52.841 35.088 53.057 38.568 ;
     RECT  52.732 28.608 53.075 34.104 ;
     RECT  53.075 28.608 53.116 33.048 ;
     RECT  52.981 20.4 53.129 20.952 ;
     RECT  53.017 44.304 53.129 47.064 ;
     RECT  52.732 26.784 53.233 27.624 ;
     RECT  53.053 12.288 53.315 14.424 ;
     RECT  52.981 15.6 53.341 17.112 ;
     RECT  53.341 15.408 53.377 17.112 ;
     RECT  52.693 18.192 53.377 18.216 ;
     RECT  53.315 13.008 53.411 14.424 ;
     RECT  53.129 20.4 53.417 20.424 ;
     RECT  53.377 15.408 53.557 18.216 ;
     RECT  52.837 19.248 53.557 19.368 ;
     RECT  53.017 39.6 53.557 40.44 ;
     RECT  52.595 41.52 53.557 41.544 ;
     RECT  53.557 15.408 53.603 19.992 ;
     RECT  53.557 39.6 53.603 41.544 ;
     RECT  53.075 34.08 53.605 34.104 ;
     RECT  53.057 35.088 53.605 35.112 ;
     RECT  53.605 34.08 53.651 35.112 ;
     RECT  53.057 36.24 53.651 37.08 ;
     RECT  53.017 57.072 53.665 59.352 ;
     RECT  53.603 40.416 53.669 41.544 ;
     RECT  53.603 19.968 53.741 19.992 ;
     RECT  52.877 48.528 53.741 48.936 ;
     RECT  53.651 36.48 53.885 37.08 ;
     RECT  52.805 21.984 53.921 25.752 ;
     RECT  53.921 22.752 53.953 25.752 ;
     RECT  53.233 26.736 53.953 27.624 ;
     RECT  53.669 40.992 53.957 41.544 ;
     RECT  53.957 41.136 53.961 41.544 ;
     RECT  52.981 51.12 54.025 55.848 ;
     RECT  53.665 57.024 54.025 59.352 ;
     RECT  53.961 41.136 54.065 41.64 ;
     RECT  52.589 42.816 54.085 43.272 ;
     RECT  54.085 42.624 54.131 43.272 ;
     RECT  53.603 15.408 54.133 18.984 ;
     RECT  53.057 38.4 54.133 38.568 ;
     RECT  54.133 14.88 54.179 18.984 ;
     RECT  53.953 22.752 54.281 27.624 ;
     RECT  54.281 22.752 54.317 25.752 ;
     RECT  53.116 28.608 54.323 33 ;
     RECT  53.129 44.304 54.385 46.968 ;
     RECT  53.741 48.528 54.385 48.552 ;
     RECT  53.411 13.008 54.389 13.656 ;
     RECT  54.281 26.784 54.389 27.624 ;
     RECT  54.389 26.784 54.497 26.808 ;
     RECT  54.385 44.304 54.497 48.552 ;
     RECT  54.179 14.88 54.669 17.64 ;
     RECT  53.885 36.48 54.677 36.792 ;
     RECT  52.337 50.112 54.709 50.136 ;
     RECT  54.025 51.12 54.709 59.352 ;
     RECT  54.179 18.96 54.713 18.984 ;
     RECT  54.497 47.04 54.785 48.552 ;
     RECT  54.389 13.104 54.805 13.656 ;
     RECT  54.323 30.24 54.817 33 ;
     RECT  54.323 28.608 54.821 29.256 ;
     RECT  53.651 34.08 54.86 34.536 ;
     RECT  54.745 35.664 54.86 35.688 ;
     RECT  54.709 50.112 54.889 59.352 ;
     RECT  54.889 50.112 54.901 59.832 ;
     RECT  54.677 36.768 54.925 36.792 ;
     RECT  54.133 38.256 54.925 38.568 ;
     RECT  54.901 50.112 54.929 60.456 ;
     RECT  54.805 13.104 54.937 14.232 ;
     RECT  54.929 50.112 54.956 58.488 ;
     RECT  54.925 36.768 54.959 39.192 ;
     RECT  54.929 59.808 54.973 60.456 ;
     RECT  54.956 49.536 54.995 58.488 ;
     RECT  54.349 21.648 55.093 21.672 ;
     RECT  54.317 22.752 55.093 25.128 ;
     RECT  54.995 57.024 55.109 58.488 ;
     RECT  55.093 21.648 55.177 25.128 ;
     RECT  55.177 21.504 55.189 25.128 ;
     RECT  54.065 41.232 55.213 41.64 ;
     RECT  54.817 30.24 55.237 33.048 ;
     RECT  54.86 34.08 55.237 35.688 ;
     RECT  54.937 13.104 55.289 13.608 ;
     RECT  54.669 15.6 55.289 17.64 ;
     RECT  54.497 44.304 55.324 45.912 ;
     RECT  54.821 28.992 55.333 29.256 ;
     RECT  55.237 30.24 55.333 35.688 ;
     RECT  55.213 41.136 55.333 41.64 ;
     RECT  54.131 42.624 55.333 42.648 ;
     RECT  55.324 44.304 55.333 45.576 ;
     RECT  55.333 43.776 55.42 45.576 ;
     RECT  55.333 41.136 55.573 42.648 ;
     RECT  55.573 41.088 55.601 42.648 ;
     RECT  55.289 15.744 55.717 17.64 ;
     RECT  55.333 28.992 55.861 35.688 ;
     RECT  54.959 36.768 55.861 39.336 ;
     RECT  54.785 47.04 55.861 47.688 ;
     RECT  55.601 40.992 55.957 42.648 ;
     RECT  54.995 49.536 56.005 55.992 ;
     RECT  55.109 57.072 56.041 58.488 ;
     RECT  55.189 21.504 56.185 24.936 ;
     RECT  55.289 13.104 56.293 13.128 ;
     RECT  56.041 57.072 56.329 59.016 ;
     RECT  55.861 28.992 56.365 39.336 ;
     RECT  55.957 40.992 56.365 43.32 ;
     RECT  56.293 13.104 56.408 13.176 ;
     RECT  55.717 15.744 56.408 17.688 ;
     RECT  55.393 18.816 56.408 18.84 ;
     RECT  56.156 20.448 56.408 20.472 ;
     RECT  56.185 21.504 56.408 25.128 ;
     RECT  55.717 27.888 56.408 27.912 ;
     RECT  56.365 28.992 56.408 43.32 ;
     RECT  55.42 44.448 56.408 45.576 ;
     RECT  55.861 47.04 56.408 48.408 ;
     RECT  56.005 49.488 56.408 55.992 ;
     RECT  56.329 57.024 56.408 59.016 ;
     RECT  54.973 60.432 56.408 60.456 ;
     RECT  56.408 2.148 56.512 62.652 ;
     RECT  56.512 2.418 56.704 62.382 ;
     RECT  56.704 36.336 56.819 41.256 ;
     RECT  56.704 44.784 56.819 48.408 ;
     RECT  56.819 37.056 56.837 41.256 ;
     RECT  56.704 49.488 56.837 55.992 ;
     RECT  56.704 23.328 56.867 27.912 ;
     RECT  56.704 29.232 57.011 34.776 ;
     RECT  56.837 37.152 57.011 41.256 ;
     RECT  56.704 57.072 57.011 60.408 ;
     RECT  56.704 21.504 57.017 22.344 ;
     RECT  56.867 23.328 57.017 26.28 ;
     RECT  57.011 29.232 57.017 33.672 ;
     RECT  57.011 57.072 57.017 59.544 ;
     RECT  57.017 30.24 57.053 33.672 ;
     RECT  56.837 49.488 57.443 55.8 ;
     RECT  57.017 57.072 57.593 59.016 ;
     RECT  57.017 29.232 57.629 29.256 ;
     RECT  57.011 37.344 57.665 41.256 ;
     RECT  56.704 15.36 57.733 17.64 ;
     RECT  57.017 21.504 57.733 21.528 ;
     RECT  56.704 42.528 57.733 42.744 ;
     RECT  56.819 44.784 57.733 45.576 ;
     RECT  57.053 32.208 57.779 33.624 ;
     RECT  57.769 29.088 57.805 29.112 ;
     RECT  57.733 42.528 57.817 42.792 ;
     RECT  56.867 27.888 57.841 27.912 ;
     RECT  57.805 28.944 57.841 29.112 ;
     RECT  57.733 44.448 57.841 45.576 ;
     RECT  57.053 30.24 57.845 30.984 ;
     RECT  57.779 32.4 57.845 33.624 ;
     RECT  57.017 26.256 57.913 26.28 ;
     RECT  56.819 46.8 57.913 48.408 ;
     RECT  57.665 40.08 57.925 41.256 ;
     RECT  57.817 42.528 57.925 42.744 ;
     RECT  57.733 21.12 57.98 21.528 ;
     RECT  57.011 34.752 57.989 34.776 ;
     RECT  57.733 15.36 58.021 18.168 ;
     RECT  57.925 40.08 58.061 42.744 ;
     RECT  57.98 20.352 58.067 21.528 ;
     RECT  58.061 42.192 58.115 42.744 ;
     RECT  56.704 13.152 58.117 13.512 ;
     RECT  58.021 14.64 58.117 18.168 ;
     RECT  57.841 43.92 58.117 45.576 ;
     RECT  58.117 13.152 58.163 18.168 ;
     RECT  58.117 43.92 58.165 45.72 ;
     RECT  57.913 46.752 58.165 48.408 ;
     RECT  57.665 37.344 58.309 38.76 ;
     RECT  57.913 26.256 58.313 26.808 ;
     RECT  57.017 23.328 58.345 25.08 ;
     RECT  58.165 43.92 58.381 48.408 ;
     RECT  58.067 21.12 58.417 21.528 ;
     RECT  58.345 22.8 58.417 25.08 ;
     RECT  58.163 14.064 58.421 18.168 ;
     RECT  58.417 21.12 58.493 25.08 ;
     RECT  58.313 26.256 58.525 26.76 ;
     RECT  58.421 14.544 58.529 18.168 ;
     RECT  58.529 17.04 58.556 18.168 ;
     RECT  58.493 21.696 58.595 25.08 ;
     RECT  58.309 36.912 58.633 38.76 ;
     RECT  58.061 40.08 58.633 41.16 ;
     RECT  58.556 17.04 58.643 18.6 ;
     RECT  58.381 43.872 58.673 48.408 ;
     RECT  58.673 43.872 58.691 48.264 ;
     RECT  58.633 36.912 58.709 41.16 ;
     RECT  58.691 43.92 58.745 48.264 ;
     RECT  57.443 49.488 58.745 49.512 ;
     RECT  58.595 23.136 58.777 25.08 ;
     RECT  58.643 17.04 58.787 17.688 ;
     RECT  58.787 17.664 58.817 17.688 ;
     RECT  57.443 51.12 58.885 55.8 ;
     RECT  58.745 43.92 58.924 47.928 ;
     RECT  58.924 45.504 58.961 47.928 ;
     RECT  57.841 27.888 58.969 29.112 ;
     RECT  57.845 30.24 58.993 30.264 ;
     RECT  58.885 50.736 58.993 55.8 ;
     RECT  57.593 57.072 58.993 58.68 ;
     RECT  58.529 14.544 59.02 16.008 ;
     RECT  58.969 27.888 59.033 28.488 ;
     RECT  59.02 15.312 59.075 16.008 ;
     RECT  58.709 41.04 59.077 41.16 ;
     RECT  58.709 36.912 59.101 39.912 ;
     RECT  59.075 15.84 59.141 16.008 ;
     RECT  59.077 41.04 59.164 41.544 ;
     RECT  57.845 32.4 59.173 32.568 ;
     RECT  58.345 33.936 59.183 33.96 ;
     RECT  58.993 50.736 59.213 58.68 ;
     RECT  59.101 36.288 59.221 39.912 ;
     RECT  58.885 19.632 59.269 19.656 ;
     RECT  58.777 23.136 59.269 25.224 ;
     RECT  58.525 26.208 59.269 26.76 ;
     RECT  58.993 30.24 59.269 30.312 ;
     RECT  59.173 32.4 59.269 32.952 ;
     RECT  59.183 33.936 59.269 34.632 ;
     RECT  59.269 19.632 59.315 20.568 ;
     RECT  59.221 35.664 59.357 39.912 ;
     RECT  59.269 23.136 59.363 26.76 ;
     RECT  58.115 42.672 59.393 42.744 ;
     RECT  59.357 36.768 59.401 39.912 ;
     RECT  59.269 30.24 59.425 31.272 ;
     RECT  59.269 32.4 59.425 34.632 ;
     RECT  59.141 15.984 59.501 16.008 ;
     RECT  58.595 21.696 59.533 22.008 ;
     RECT  59.315 20.544 59.573 20.568 ;
     RECT  59.401 38.688 59.596 39.912 ;
     RECT  59.363 25.056 59.605 26.76 ;
     RECT  59.213 50.736 59.641 58.152 ;
     RECT  59.033 28.08 59.645 28.488 ;
     RECT  59.533 21.648 59.681 22.008 ;
     RECT  59.645 28.08 59.717 28.344 ;
     RECT  59.164 41.04 59.785 41.16 ;
     RECT  59.353 19.104 59.813 19.128 ;
     RECT  59.425 29.76 59.821 34.632 ;
     RECT  59.357 35.664 59.821 35.688 ;
     RECT  59.401 36.768 59.861 37.656 ;
     RECT  59.785 17.088 59.891 17.112 ;
     RECT  59.813 18.24 59.897 19.128 ;
     RECT  59.641 49.968 59.933 58.152 ;
     RECT  58.961 45.504 60.145 45.768 ;
     RECT  58.961 46.752 60.145 47.928 ;
     RECT  59.605 25.056 60.149 27.096 ;
     RECT  59.393 42.672 60.181 42.696 ;
     RECT  59.933 51.168 60.185 58.152 ;
     RECT  59.821 29.76 60.293 35.688 ;
     RECT  60.293 30.912 60.329 35.688 ;
     RECT  60.149 25.2 60.373 27.096 ;
     RECT  59.717 28.08 60.373 28.104 ;
     RECT  60.145 45.504 60.38 47.928 ;
     RECT  59.897 18.96 60.397 19.128 ;
     RECT  60.373 25.2 60.437 28.104 ;
     RECT  60.437 25.2 60.46 27.864 ;
     RECT  60.38 45.504 60.467 48.072 ;
     RECT  60.46 25.2 60.473 27.096 ;
     RECT  59.596 38.832 60.577 39.912 ;
     RECT  60.181 42.384 60.577 42.696 ;
     RECT  58.924 43.92 60.577 43.944 ;
     RECT  59.933 49.968 60.613 49.992 ;
     RECT  60.577 42.384 60.653 43.944 ;
     RECT  60.397 18.96 60.689 19.32 ;
     RECT  60.185 51.168 60.689 57.576 ;
     RECT  59.681 21.648 60.716 21.72 ;
     RECT  59.363 23.136 60.716 23.592 ;
     RECT  59.861 36.768 60.721 37.08 ;
     RECT  60.689 18.96 60.725 18.984 ;
     RECT  60.689 55.44 60.725 57.576 ;
     RECT  60.716 21.648 60.757 23.592 ;
     RECT  60.757 21.072 60.761 23.592 ;
     RECT  60.689 51.168 60.761 54.408 ;
     RECT  60.467 45.504 60.796 47.88 ;
     RECT  60.761 21.072 60.803 23.16 ;
     RECT  60.761 51.168 60.901 52.92 ;
     RECT  60.721 36.432 60.949 37.08 ;
     RECT  60.293 29.76 61.093 29.784 ;
     RECT  60.613 49.536 61.196 49.992 ;
     RECT  60.901 51.024 61.196 52.92 ;
     RECT  60.577 38.352 61.405 39.912 ;
     RECT  59.785 40.992 61.405 41.16 ;
     RECT  60.803 21.072 61.808 21.672 ;
     RECT  60.803 23.136 61.808 23.16 ;
     RECT  60.473 25.2 61.808 25.992 ;
     RECT  60.473 27.072 61.808 27.096 ;
     RECT  61.093 28.848 61.808 29.784 ;
     RECT  60.329 30.912 61.808 34.824 ;
     RECT  60.949 36.432 61.808 37.32 ;
     RECT  61.405 38.352 61.808 41.16 ;
     RECT  60.653 42.384 61.808 43.752 ;
     RECT  60.796 45.504 61.808 47.352 ;
     RECT  61.196 49.536 61.808 52.92 ;
     RECT  60.761 53.904 61.808 54.408 ;
     RECT  60.725 55.44 61.808 57.096 ;
     RECT  61.808 2.148 61.912 62.652 ;
     RECT  61.912 2.418 62.104 62.382 ;
     RECT  62.104 51.36 62.339 53.256 ;
     RECT  62.339 51.504 63.133 53.256 ;
     RECT  62.104 54.384 63.133 54.408 ;
     RECT  63.205 45.552 63.241 45.576 ;
     RECT  63.241 45.264 63.277 45.576 ;
     RECT  63.133 51.504 63.853 54.408 ;
     RECT  63.277 45.264 64.764 45.768 ;
     RECT  63.853 51.408 64.764 54.408 ;
    LAYER M5 ;
     RECT  2.4 2.137 2.52 2.151 ;
     RECT  7.8 2.137 7.92 2.151 ;
     RECT  13.2 2.137 13.32 2.151 ;
     RECT  18.6 2.137 18.72 2.151 ;
     RECT  24 2.137 24.12 2.151 ;
     RECT  29.4 2.137 29.52 2.151 ;
     RECT  34.8 2.137 34.92 2.151 ;
     RECT  40.2 2.137 40.32 2.151 ;
     RECT  45.6 2.137 45.72 2.151 ;
     RECT  51 2.137 51.12 2.151 ;
     RECT  56.4 2.137 56.52 2.151 ;
     RECT  61.8 2.137 61.92 2.151 ;
     RECT  13.2 2.151 13.512 6.901 ;
     RECT  18.6 2.151 18.912 7.909 ;
     RECT  11.184 7.189 11.208 8.003 ;
     RECT  13.104 6.901 13.512 8.149 ;
     RECT  25.392 7.381 25.416 8.675 ;
     RECT  7.8 2.151 8.112 8.965 ;
     RECT  12.96 8.149 13.512 9.397 ;
     RECT  5.76 8.725 5.784 9.491 ;
     RECT  29.4 2.151 29.712 9.493 ;
     RECT  18.6 7.909 19.08 9.637 ;
     RECT  28.56 9.493 29.712 9.637 ;
     RECT  12.96 9.397 13.608 9.779 ;
     RECT  40.2 2.151 40.512 10.069 ;
     RECT  42.144 9.925 42.168 10.069 ;
     RECT  17.664 9.637 19.08 10.115 ;
     RECT  40.2 10.069 42.168 10.213 ;
     RECT  22.752 8.485 22.776 10.307 ;
     RECT  43.536 9.493 43.56 10.307 ;
     RECT  13.104 9.779 13.608 10.597 ;
     RECT  20.688 8.485 20.712 10.789 ;
     RECT  28.56 9.637 30.072 10.883 ;
     RECT  40.08 10.213 42.168 10.883 ;
     RECT  13.104 10.597 13.656 10.931 ;
     RECT  45.6 2.151 45.912 10.981 ;
     RECT  9.6 8.245 9.624 11.029 ;
     RECT  28.608 10.883 30.072 11.267 ;
     RECT  42.144 10.883 42.168 11.269 ;
     RECT  24 2.151 24.312 11.413 ;
     RECT  3.984 10.213 4.008 11.459 ;
     RECT  17.664 10.115 18.912 11.459 ;
     RECT  32.448 10.837 32.472 11.653 ;
     RECT  14.832 10.309 14.856 11.699 ;
     RECT  32.448 11.653 32.664 11.699 ;
     RECT  45.6 10.981 46.008 11.701 ;
     RECT  44.928 11.701 46.008 11.747 ;
     RECT  42.144 11.269 42.744 11.939 ;
     RECT  24 11.413 24.6 11.941 ;
     RECT  24 11.941 25.32 11.987 ;
     RECT  9.6 11.029 10.248 12.035 ;
     RECT  20.352 10.789 20.712 12.035 ;
     RECT  13.2 10.931 13.656 12.179 ;
     RECT  20.352 12.035 20.376 12.179 ;
     RECT  9.6 12.035 9.624 12.181 ;
     RECT  7.8 8.965 8.28 12.227 ;
     RECT  28.608 11.267 29.712 12.325 ;
     RECT  49.248 10.741 49.272 12.373 ;
     RECT  51 2.151 51.312 12.373 ;
     RECT  32.64 11.699 32.664 12.515 ;
     RECT  40.08 10.883 40.512 12.515 ;
     RECT  34.8 2.151 35.112 12.517 ;
     RECT  36.096 11.509 36.12 12.563 ;
     RECT  44.928 11.747 45.912 12.755 ;
     RECT  11.28 11.941 11.304 12.899 ;
     RECT  34.416 12.517 35.112 12.901 ;
     RECT  25.296 11.987 25.32 12.995 ;
     RECT  49.248 12.373 51.312 13.139 ;
     RECT  21.648 12.517 21.672 13.285 ;
     RECT  45.6 12.755 45.912 13.285 ;
     RECT  20.928 13.285 21.672 13.331 ;
     RECT  42.72 11.939 42.744 13.429 ;
     RECT  49.248 13.139 49.272 13.523 ;
     RECT  27.888 12.325 29.712 13.621 ;
     RECT  47.904 9.637 47.928 13.621 ;
     RECT  53.28 12.277 53.304 13.621 ;
     RECT  47.904 13.621 48.696 13.667 ;
     RECT  43.872 12.901 43.896 13.715 ;
     RECT  34.416 12.901 35.88 13.859 ;
     RECT  13.2 12.179 13.512 14.197 ;
     RECT  54.816 13.093 54.84 14.197 ;
     RECT  18.24 11.459 18.912 14.243 ;
     RECT  27.888 13.621 30.216 14.243 ;
     RECT  50.736 13.139 51.312 14.243 ;
     RECT  20.928 13.331 20.952 14.293 ;
     RECT  20.736 14.293 20.952 14.339 ;
     RECT  24 11.987 24.312 14.389 ;
     RECT  42.144 13.429 42.744 14.435 ;
     RECT  58.128 13.141 58.152 14.533 ;
     RECT  7.8 12.227 8.112 14.773 ;
     RECT  6.672 13.045 6.696 14.867 ;
     RECT  54.816 14.197 54.888 14.869 ;
     RECT  12.528 14.197 13.512 14.915 ;
     RECT  33.264 14.005 33.288 15.107 ;
     RECT  28.608 14.243 30.216 15.299 ;
     RECT  58.128 14.533 58.968 15.301 ;
     RECT  48.672 13.667 48.696 15.349 ;
     RECT  5.136 14.197 5.16 15.443 ;
     RECT  53.28 13.621 53.4 15.443 ;
     RECT  40.2 12.515 40.512 15.541 ;
     RECT  9.36 12.181 9.624 15.587 ;
     RECT  53.28 15.443 53.304 15.637 ;
     RECT  13.104 14.915 13.512 15.779 ;
     RECT  41.712 15.589 41.736 15.829 ;
     RECT  42.72 14.435 42.744 15.829 ;
     RECT  15.36 14.245 15.384 16.019 ;
     RECT  20.736 14.339 20.76 16.019 ;
     RECT  58.128 15.301 59.064 16.019 ;
     RECT  24 14.389 24.408 16.115 ;
     RECT  54.576 14.869 54.888 16.115 ;
     RECT  38.352 14.773 38.376 16.259 ;
     RECT  39.84 15.541 40.512 16.259 ;
     RECT  45.6 13.285 46.104 16.261 ;
     RECT  56.4 2.151 56.712 16.261 ;
     RECT  51 14.243 51.312 16.357 ;
     RECT  52.32 15.637 53.304 16.357 ;
     RECT  28.608 15.299 29.712 16.403 ;
     RECT  44.448 15.925 44.472 16.499 ;
     RECT  7.8 14.773 8.232 16.501 ;
     RECT  51 16.357 53.304 16.501 ;
     RECT  51 16.501 53.592 16.547 ;
     RECT  48.672 15.349 49.56 16.595 ;
     RECT  41.712 15.829 42.744 16.691 ;
     RECT  49.536 16.595 49.56 16.787 ;
     RECT  9.36 15.587 9.384 16.835 ;
     RECT  42.24 16.691 42.744 16.931 ;
     RECT  51 16.547 52.344 17.027 ;
     RECT  7.392 16.501 8.232 17.029 ;
     RECT  45.6 16.261 46.44 17.029 ;
     RECT  25.632 16.069 25.656 17.075 ;
     RECT  55.728 16.261 56.712 17.075 ;
     RECT  2.4 2.151 2.712 17.077 ;
     RECT  37.152 16.885 37.176 17.077 ;
     RECT  29.04 16.403 29.712 17.123 ;
     RECT  54.576 16.115 54.6 17.123 ;
     RECT  34.8 13.859 35.88 17.219 ;
     RECT  37.008 17.077 37.176 17.219 ;
     RECT  45.6 17.029 46.536 17.603 ;
     RECT  13.2 15.779 13.512 17.605 ;
     RECT  40.2 16.259 40.512 17.605 ;
     RECT  45.6 17.603 46.44 17.605 ;
     RECT  53.568 16.547 53.592 17.605 ;
     RECT  6.864 17.029 8.232 17.651 ;
     RECT  45.216 17.605 46.44 17.651 ;
     RECT  58.128 16.019 58.776 17.651 ;
     RECT  42.24 16.931 42.264 17.699 ;
     RECT  58.608 17.651 58.776 17.699 ;
     RECT  6.864 17.651 8.112 17.987 ;
     RECT  53.568 17.605 54.168 18.181 ;
     RECT  22.224 16.501 22.248 18.227 ;
     RECT  48.624 17.605 48.648 18.275 ;
     RECT  59.856 17.077 59.88 18.275 ;
     RECT  24 16.115 24.312 18.565 ;
     RECT  29.4 17.123 29.712 18.661 ;
     RECT  45.216 17.651 46.104 18.803 ;
     RECT  27.936 17.077 27.96 18.805 ;
     RECT  29.4 18.661 30.792 18.947 ;
     RECT  4.896 16.981 4.92 18.995 ;
     RECT  39.216 17.605 40.512 18.995 ;
     RECT  52.704 18.181 54.168 18.995 ;
     RECT  2.4 17.077 2.856 19.235 ;
     RECT  39.84 18.995 40.512 19.283 ;
     RECT  10.992 16.789 11.016 19.285 ;
     RECT  13.2 17.605 13.656 19.333 ;
     RECT  18.6 14.243 18.912 19.333 ;
     RECT  29.4 18.947 30.696 19.475 ;
     RECT  58.608 17.699 58.632 19.621 ;
     RECT  45.504 18.803 46.104 19.765 ;
     RECT  27.504 18.805 27.96 20.003 ;
     RECT  33.072 18.805 33.096 20.003 ;
     RECT  52.704 18.995 53.592 20.003 ;
     RECT  20.832 19.093 20.856 20.339 ;
     RECT  58.608 19.621 59.304 20.341 ;
     RECT  45.504 19.765 46.152 20.387 ;
     RECT  18.6 19.333 19.272 20.435 ;
     RECT  56.4 17.075 56.712 20.437 ;
     RECT  51 17.027 51.432 20.485 ;
     RECT  47.856 20.341 47.88 20.579 ;
     RECT  58.032 20.341 59.304 20.579 ;
     RECT  18.6 20.435 18.912 20.581 ;
     RECT  27.936 20.003 27.96 20.725 ;
     RECT  42.192 20.293 42.216 20.725 ;
     RECT  49.728 20.485 51.432 21.155 ;
     RECT  58.032 20.579 58.632 21.155 ;
     RECT  10.032 19.285 11.016 21.395 ;
     RECT  13.2 19.333 13.704 21.397 ;
     RECT  7.392 17.987 8.112 21.443 ;
     RECT  45.504 20.387 46.104 21.443 ;
     RECT  50.16 21.155 51.432 21.443 ;
     RECT  43.632 21.397 43.656 21.493 ;
     RECT  56.208 20.437 56.712 21.493 ;
     RECT  45.504 21.443 46.056 21.589 ;
     RECT  34.8 17.219 35.112 21.637 ;
     RECT  52.704 20.003 52.728 21.637 ;
     RECT  55.728 21.493 56.712 21.637 ;
     RECT  37.152 17.219 37.176 21.683 ;
     RECT  52.56 21.637 52.728 21.683 ;
     RECT  55.104 21.637 56.712 21.781 ;
     RECT  27.936 20.725 28.056 21.877 ;
     RECT  41.52 20.725 42.216 21.923 ;
     RECT  43.344 21.493 43.656 22.117 ;
     RECT  18.288 20.581 18.912 22.165 ;
     RECT  60.768 21.061 60.792 22.211 ;
     RECT  2.4 19.235 2.712 22.213 ;
     RECT  39.888 19.283 40.512 22.213 ;
     RECT  55.104 21.781 56.808 22.499 ;
     RECT  26.256 22.453 26.28 22.645 ;
     RECT  58.608 21.155 58.632 22.645 ;
     RECT  48.672 22.165 48.696 22.693 ;
     RECT  50.16 21.443 51.312 22.739 ;
     RECT  55.728 22.499 56.808 22.739 ;
     RECT  23.04 18.565 24.312 22.741 ;
     RECT  25.584 22.645 26.28 22.741 ;
     RECT  41.52 21.923 41.544 22.787 ;
     RECT  45.264 21.589 46.056 22.787 ;
     RECT  23.04 22.741 26.28 22.835 ;
     RECT  17.376 22.165 18.912 22.883 ;
     RECT  10.992 21.395 11.016 22.979 ;
     RECT  58.56 22.645 58.632 23.125 ;
     RECT  43.248 22.117 43.656 23.173 ;
     RECT  52.56 21.683 52.584 23.269 ;
     RECT  2.4 22.213 2.904 23.363 ;
     RECT  31.584 22.165 31.608 23.555 ;
     RECT  58.56 23.125 59.352 23.603 ;
     RECT  56.4 22.739 56.808 23.699 ;
     RECT  48.672 22.693 48.984 23.843 ;
     RECT  27.936 21.877 28.152 23.891 ;
     RECT  23.04 22.835 25.608 23.893 ;
     RECT  21.648 23.557 21.672 24.037 ;
     RECT  51 22.739 51.312 24.037 ;
     RECT  21.36 24.037 21.672 24.083 ;
     RECT  22.752 23.893 25.608 24.083 ;
     RECT  45.6 22.787 46.056 24.131 ;
     RECT  9.84 22.069 9.864 24.133 ;
     RECT  50.832 24.037 51.312 24.181 ;
     RECT  9.84 24.133 10.248 24.227 ;
     RECT  15.264 22.117 15.288 24.227 ;
     RECT  52.56 23.269 52.968 24.227 ;
     RECT  48.96 23.843 48.984 24.323 ;
     RECT  54.672 23.317 54.696 24.325 ;
     RECT  54.672 24.325 55.176 24.371 ;
     RECT  32.976 20.725 33 24.515 ;
     RECT  28.128 23.891 28.152 24.613 ;
     RECT  29.4 19.475 29.712 24.613 ;
     RECT  22.752 24.083 22.776 24.899 ;
     RECT  43.248 23.173 44.28 24.901 ;
     RECT  6.336 22.981 6.36 25.045 ;
     RECT  42.144 23.701 42.168 25.045 ;
     RECT  58.608 23.603 59.352 25.045 ;
     RECT  41.76 25.045 42.168 25.091 ;
     RECT  13.2 21.397 14.136 25.139 ;
     RECT  34.8 21.637 35.592 25.139 ;
     RECT  52.704 24.227 52.968 25.139 ;
     RECT  55.152 24.371 55.176 25.139 ;
     RECT  38.208 25.045 38.232 25.285 ;
     RECT  16.752 24.469 16.776 25.331 ;
     RECT  37.296 25.285 38.232 25.475 ;
     RECT  56.4 23.699 56.712 25.525 ;
     RECT  43.248 24.901 44.376 25.573 ;
     RECT  13.2 25.139 14.04 25.715 ;
     RECT  24 24.083 25.608 25.715 ;
     RECT  45.6 24.131 46.008 25.763 ;
     RECT  6.288 25.045 6.36 25.859 ;
     RECT  58.608 25.045 59.88 25.957 ;
     RECT  24 25.715 24.888 26.003 ;
     RECT  28.128 24.613 29.712 26.243 ;
     RECT  30.768 25.669 30.792 26.243 ;
     RECT  37.296 25.475 37.32 26.243 ;
     RECT  39.408 22.213 40.512 26.243 ;
     RECT  58.608 25.957 60.216 26.485 ;
     RECT  10.224 24.227 10.248 26.675 ;
     RECT  19.92 23.845 19.944 26.675 ;
     RECT  12.192 24.181 12.216 26.725 ;
     RECT  52.704 25.139 52.728 26.725 ;
     RECT  58.608 26.485 60.408 26.771 ;
     RECT  45.6 25.763 45.912 26.773 ;
     RECT  52.704 26.725 53.592 26.773 ;
     RECT  56.4 25.525 56.808 26.917 ;
     RECT  43.248 25.573 44.472 26.963 ;
     RECT  28.512 26.243 29.712 27.059 ;
     RECT  7.8 21.443 8.112 27.061 ;
     RECT  58.896 26.771 60.408 27.107 ;
     RECT  6.336 25.859 6.36 27.205 ;
     RECT  52.656 26.773 53.592 27.635 ;
     RECT  50.256 24.181 51.312 27.829 ;
     RECT  7.8 27.061 8.52 27.875 ;
     RECT  60.384 27.107 60.408 27.875 ;
     RECT  43.248 26.963 44.376 27.877 ;
     RECT  58.896 27.107 58.92 27.877 ;
     RECT  56.4 26.917 56.856 27.923 ;
     RECT  43.056 27.877 44.376 27.925 ;
     RECT  17.904 22.883 18.912 27.973 ;
     RECT  40.2 26.243 40.512 28.021 ;
     RECT  27.456 27.013 27.48 28.163 ;
     RECT  47.856 26.917 47.88 28.163 ;
     RECT  24 26.003 24.312 28.309 ;
     RECT  45.6 26.773 46.008 28.453 ;
     RECT  21.36 24.083 21.384 28.501 ;
     RECT  52.656 27.635 52.728 28.547 ;
     RECT  41.76 25.091 41.784 28.691 ;
     RECT  34.8 25.139 35.4 28.789 ;
     RECT  2.4 23.363 2.712 28.837 ;
     RECT  61.8 2.151 62.112 28.837 ;
     RECT  11.952 26.725 12.216 28.979 ;
     RECT  45.408 28.453 46.008 28.981 ;
     RECT  13.2 25.715 13.512 29.029 ;
     RECT  5.088 27.877 5.112 29.075 ;
     RECT  6.336 27.205 6.408 29.075 ;
     RECT  24 28.309 25.08 29.123 ;
     RECT  58.128 27.877 58.92 29.123 ;
     RECT  34.704 28.789 35.4 29.219 ;
     RECT  45.408 28.981 46.152 29.363 ;
     RECT  30.816 28.357 30.84 29.605 ;
     RECT  42.96 27.925 44.376 29.605 ;
     RECT  52.704 28.547 52.728 29.605 ;
     RECT  54.288 28.981 54.312 29.605 ;
     RECT  30.816 29.605 31.32 29.651 ;
     RECT  21.36 28.501 21.672 29.699 ;
     RECT  52.704 29.605 54.312 29.747 ;
     RECT  61.104 28.837 62.112 29.749 ;
     RECT  13.2 29.029 14.28 29.795 ;
     RECT  45.408 29.363 46.008 29.795 ;
     RECT  12.192 28.979 12.216 29.939 ;
     RECT  21.36 29.699 21.528 29.989 ;
     RECT  24 29.123 24.312 30.133 ;
     RECT  45.6 29.795 46.008 30.179 ;
     RECT  55.344 29.605 55.368 30.229 ;
     RECT  56.4 27.923 56.712 30.229 ;
     RECT  17.904 27.973 19.848 30.277 ;
     RECT  17.904 30.277 19.944 30.323 ;
     RECT  50.16 27.829 51.312 30.323 ;
     RECT  34.704 29.219 35.112 30.325 ;
     RECT  31.296 29.651 31.32 30.467 ;
     RECT  38.544 29.029 38.568 30.611 ;
     RECT  23.616 30.133 24.312 30.613 ;
     RECT  55.344 30.229 56.712 30.709 ;
     RECT  6.336 29.075 6.36 30.805 ;
     RECT  7.8 27.875 8.112 30.805 ;
     RECT  13.2 29.795 13.512 30.805 ;
     RECT  6.336 30.805 8.112 30.851 ;
     RECT  34.224 30.325 35.112 30.899 ;
     RECT  52.704 29.747 53.544 30.899 ;
     RECT  10.8 28.933 10.824 30.947 ;
     RECT  39.984 28.021 40.512 30.947 ;
     RECT  60.432 29.749 62.112 30.947 ;
     RECT  2.4 28.837 2.808 31.043 ;
     RECT  19.92 30.323 19.944 31.091 ;
     RECT  6.816 30.851 8.112 31.139 ;
     RECT  23.616 30.613 24.456 31.139 ;
     RECT  26.016 30.181 26.04 31.139 ;
     RECT  55.296 30.709 56.712 31.141 ;
     RECT  57.744 30.949 57.768 31.141 ;
     RECT  42.192 29.605 44.376 31.187 ;
     RECT  45.6 30.179 45.912 31.189 ;
     RECT  21.12 29.989 21.528 31.285 ;
     RECT  50.208 30.323 51.312 31.379 ;
     RECT  55.296 31.141 57.768 31.379 ;
     RECT  20.976 31.285 21.528 31.619 ;
     RECT  60.432 30.947 60.456 31.811 ;
     RECT  13.056 30.805 13.512 31.861 ;
     RECT  34.8 30.899 35.112 31.861 ;
     RECT  20.976 31.619 21 31.955 ;
     RECT  45.504 31.189 45.912 32.195 ;
     RECT  48.096 30.565 48.12 32.197 ;
     RECT  24 31.139 24.456 32.291 ;
     RECT  37.152 32.341 37.176 32.437 ;
     RECT  48.096 32.197 48.504 32.437 ;
     RECT  50.88 31.379 51.312 32.437 ;
     RECT  3.84 31.765 3.864 32.483 ;
     RECT  42.432 31.187 44.376 32.483 ;
     RECT  55.488 31.379 57.768 32.483 ;
     RECT  25.68 31.333 25.704 32.771 ;
     RECT  40.2 30.947 40.512 32.821 ;
     RECT  52.704 30.899 53.064 33.011 ;
     RECT  12.528 31.861 13.512 33.107 ;
     RECT  24 32.291 24.312 33.253 ;
     RECT  2.4 31.043 2.712 33.397 ;
     RECT  27.744 32.965 27.768 33.541 ;
     RECT  50.544 32.437 51.312 33.541 ;
     RECT  34.8 31.861 35.544 33.587 ;
     RECT  56.4 32.483 57.768 33.635 ;
     RECT  59.28 30.277 59.304 33.635 ;
     RECT  47.952 32.437 48.504 33.683 ;
     RECT  53.04 33.011 53.064 33.683 ;
     RECT  22.752 32.965 22.776 33.779 ;
     RECT  24 33.253 24.504 33.779 ;
     RECT  7.8 31.139 8.112 33.829 ;
     RECT  56.4 33.635 57 33.875 ;
     RECT  37.056 32.437 37.176 33.923 ;
     RECT  43.344 32.483 44.376 33.923 ;
     RECT  7.8 33.829 8.76 33.971 ;
     RECT  27.216 33.541 27.768 34.019 ;
     RECT  9.84 31.477 9.864 34.067 ;
     RECT  50.16 33.541 51.312 34.117 ;
     RECT  55.248 33.589 55.272 34.259 ;
     RECT  27.216 34.019 27.24 34.355 ;
     RECT  2.4 33.397 3.576 34.403 ;
     RECT  13.2 33.107 13.512 34.453 ;
     RECT  33.6 33.445 33.624 34.499 ;
     RECT  56.4 33.875 56.712 34.501 ;
     RECT  43.488 33.923 44.376 34.597 ;
     RECT  45.6 32.195 45.912 34.597 ;
     RECT  39.36 32.821 40.512 34.739 ;
     RECT  43.488 34.597 45.912 34.741 ;
     RECT  48.48 33.683 48.504 34.835 ;
     RECT  24 33.779 24.408 35.269 ;
     RECT  34.8 33.587 35.112 35.269 ;
     RECT  22.128 34.501 22.152 35.459 ;
     RECT  13.2 34.453 13.704 35.555 ;
     RECT  54.912 34.741 54.936 35.699 ;
     RECT  50.16 34.117 51.432 35.747 ;
     RECT  55.968 34.501 56.712 35.747 ;
     RECT  37.152 33.923 37.176 35.845 ;
     RECT  36.816 35.845 37.176 35.891 ;
     RECT  43.488 34.741 46.632 35.891 ;
     RECT  45.6 35.891 46.632 35.893 ;
     RECT  45.6 35.893 46.728 36.083 ;
     RECT  56.4 35.747 56.712 36.325 ;
     RECT  7.8 33.971 8.112 36.373 ;
     RECT  53.616 34.501 53.64 36.421 ;
     RECT  61.8 30.947 62.112 36.421 ;
     RECT  50.16 35.747 51.312 36.515 ;
     RECT  52.752 36.421 53.64 36.517 ;
     RECT  34.704 35.269 35.112 36.563 ;
     RECT  40.2 34.739 40.512 36.565 ;
     RECT  23.664 35.269 24.408 36.661 ;
     RECT  52.752 36.517 54.168 36.757 ;
     RECT  59.232 34.597 59.256 36.757 ;
     RECT  59.232 36.757 59.352 36.803 ;
     RECT  13.2 35.555 13.512 36.997 ;
     RECT  43.488 35.891 44.376 36.997 ;
     RECT  41.904 34.501 41.928 37.091 ;
     RECT  56.4 36.325 56.808 37.141 ;
     RECT  7.248 36.373 8.112 37.523 ;
     RECT  30.96 36.469 30.984 37.571 ;
     RECT  52.752 36.757 54.984 37.573 ;
     RECT  15.936 35.653 15.96 37.619 ;
     RECT  52.752 37.573 55.032 37.813 ;
     RECT  12 35.845 12.024 37.909 ;
     RECT  13.2 36.997 14.328 37.909 ;
     RECT  12 37.909 14.328 37.955 ;
     RECT  2.4 34.403 2.712 38.149 ;
     RECT  58.128 37.573 58.152 38.149 ;
     RECT  59.328 36.803 59.352 38.149 ;
     RECT  39.36 36.565 40.512 38.195 ;
     RECT  52.56 37.813 55.032 38.195 ;
     RECT  7.44 37.523 8.112 38.243 ;
     RECT  56.4 37.141 57 38.245 ;
     RECT  58.128 38.149 59.352 38.245 ;
     RECT  56.4 38.245 59.352 38.291 ;
     RECT  45.6 36.083 46.008 38.389 ;
     RECT  48.72 36.757 48.744 38.389 ;
     RECT  52.752 38.195 55.032 38.435 ;
     RECT  56.4 38.291 58.008 38.435 ;
     RECT  50.832 36.515 51.312 38.437 ;
     RECT  52.752 38.435 53.832 38.579 ;
     RECT  5.712 38.149 5.736 38.581 ;
     RECT  12.528 37.955 14.328 38.675 ;
     RECT  59.04 38.291 59.352 38.677 ;
     RECT  34.8 36.563 35.112 38.725 ;
     RECT  43.392 36.997 44.376 39.061 ;
     RECT  2.4 38.149 3.384 39.203 ;
     RECT  52.752 38.579 53.592 39.203 ;
     RECT  38.016 36.997 38.04 39.251 ;
     RECT  9.216 37.765 9.24 39.301 ;
     RECT  55.008 38.435 55.032 39.347 ;
     RECT  59.04 38.677 59.544 39.395 ;
     RECT  48.72 38.389 48.984 39.443 ;
     RECT  23.328 36.661 24.408 39.539 ;
     RECT  50.688 38.437 51.312 39.539 ;
     RECT  23.376 39.539 24.408 39.635 ;
     RECT  5.712 38.581 6.264 39.637 ;
     RECT  13.2 38.675 14.328 39.637 ;
     RECT  9.216 39.301 10.152 39.731 ;
     RECT  31.584 38.101 31.608 39.781 ;
     RECT  5.136 39.637 6.264 39.923 ;
     RECT  33.84 38.725 35.112 39.923 ;
     RECT  59.52 39.395 59.544 39.923 ;
     RECT  31.488 39.781 31.608 40.165 ;
     RECT  31.488 40.165 32.472 40.595 ;
     RECT  45.6 38.389 46.776 40.595 ;
     RECT  5.136 39.923 5.736 40.739 ;
     RECT  34.656 39.923 35.112 40.835 ;
     RECT  39.84 38.195 40.512 40.837 ;
     RECT  41.664 40.165 41.688 40.837 ;
     RECT  48.96 39.443 48.984 40.883 ;
     RECT  10.128 39.731 10.152 40.981 ;
     RECT  56.4 38.435 56.712 40.981 ;
     RECT  43.344 39.061 44.376 41.027 ;
     RECT  60.96 36.421 62.112 41.027 ;
     RECT  32.448 40.595 32.472 41.075 ;
     RECT  39.84 40.837 41.688 41.075 ;
     RECT  50.832 39.539 51.312 41.075 ;
     RECT  57.744 38.435 58.008 41.077 ;
     RECT  47.904 40.405 47.928 41.173 ;
     RECT  23.904 39.635 24.408 41.317 ;
     RECT  23.904 41.317 24.504 41.459 ;
     RECT  12.528 39.637 14.328 41.509 ;
     RECT  52.8 39.203 53.592 41.509 ;
     RECT  10.128 40.981 10.584 41.555 ;
     RECT  12.096 41.509 14.328 41.555 ;
     RECT  23.904 41.459 24.312 41.557 ;
     RECT  29.4 27.059 29.712 41.557 ;
     RECT  34.8 40.835 35.112 41.557 ;
     RECT  47.28 41.173 47.928 41.557 ;
     RECT  27.6 36.133 27.624 41.603 ;
     RECT  52.8 41.509 53.784 41.605 ;
     RECT  43.392 41.027 44.376 41.651 ;
     RECT  55.632 40.981 56.712 41.749 ;
     RECT  52.8 41.605 54.024 41.797 ;
     RECT  31.536 41.557 31.56 41.845 ;
     RECT  40.2 41.075 41.688 41.891 ;
     RECT  30.768 41.845 31.56 41.987 ;
     RECT  6.768 41.557 6.792 42.227 ;
     RECT  23.28 41.557 24.312 42.227 ;
     RECT  40.2 41.891 40.968 42.227 ;
     RECT  47.232 41.557 48.456 42.227 ;
     RECT  57.744 41.077 58.104 42.227 ;
     RECT  31.536 41.987 31.56 42.371 ;
     RECT  39.024 41.557 39.048 42.515 ;
     RECT  52.56 41.797 54.024 42.613 ;
     RECT  10.128 41.555 10.152 42.709 ;
     RECT  52.56 42.613 54.12 42.709 ;
     RECT  61.8 41.027 62.112 42.709 ;
     RECT  59.088 41.509 59.112 42.755 ;
     RECT  34.8 41.557 35.208 42.803 ;
     RECT  57.744 42.227 57.96 42.803 ;
     RECT  48.288 42.227 48.456 43.091 ;
     RECT  15.792 39.781 15.816 43.283 ;
     RECT  52.512 42.709 54.12 43.283 ;
     RECT  13.2 41.555 14.328 43.285 ;
     RECT  19.968 39.349 19.992 43.285 ;
     RECT  12.096 41.555 12.12 43.331 ;
     RECT  47.232 42.227 47.256 43.427 ;
     RECT  52.512 43.283 54.024 43.571 ;
     RECT  19.968 43.285 20.376 43.717 ;
     RECT  19.968 43.717 20.52 43.763 ;
     RECT  61.152 42.709 62.112 43.763 ;
     RECT  55.344 41.749 56.712 43.811 ;
     RECT  43.488 41.651 44.376 43.861 ;
     RECT  45.6 40.595 45.912 43.861 ;
     RECT  57.936 42.803 57.96 43.861 ;
     RECT  57.936 43.861 58.68 43.909 ;
     RECT  28.992 41.557 29.712 43.955 ;
     RECT  13.2 43.285 14.376 44.147 ;
     RECT  20.352 43.763 20.52 44.147 ;
     RECT  17.904 30.323 18.912 44.195 ;
     RECT  18.048 44.195 18.912 44.243 ;
     RECT  5.712 40.739 5.736 44.293 ;
     RECT  5.712 44.293 6.072 44.339 ;
     RECT  13.2 44.147 14.232 44.437 ;
     RECT  43.488 43.861 45.912 44.437 ;
     RECT  30.816 43.285 30.84 44.483 ;
     RECT  55.968 43.811 56.712 44.483 ;
     RECT  43.488 44.437 46.632 44.579 ;
     RECT  57.936 43.909 58.872 44.579 ;
     RECT  52.56 43.571 54.024 44.627 ;
     RECT  50.88 41.075 51.312 44.629 ;
     RECT  43.776 44.579 46.632 44.675 ;
     RECT  56.4 44.483 56.712 44.773 ;
     RECT  57.936 44.579 58.68 44.773 ;
     RECT  50.592 44.629 51.312 44.963 ;
     RECT  52.56 44.627 53.784 45.059 ;
     RECT  56.4 44.773 58.68 45.059 ;
     RECT  9.696 42.709 10.152 45.155 ;
     RECT  50.88 44.963 51.312 45.253 ;
     RECT  52.56 45.059 53.064 45.253 ;
     RECT  56.4 45.059 58.152 45.347 ;
     RECT  50.88 45.253 53.064 45.443 ;
     RECT  45.6 44.675 46.632 45.541 ;
     RECT  22.944 44.341 22.968 45.587 ;
     RECT  6.048 44.339 6.072 45.685 ;
     RECT  7.8 38.243 8.112 45.685 ;
     RECT  12.672 44.437 14.232 45.731 ;
     RECT  57.936 45.347 58.152 45.731 ;
     RECT  61.8 43.763 62.112 45.733 ;
     RECT  29.4 43.955 29.712 46.069 ;
     RECT  43.776 44.675 44.376 46.069 ;
     RECT  48.288 43.091 48.312 46.069 ;
     RECT  20.496 44.147 20.52 46.211 ;
     RECT  51 45.443 53.064 46.307 ;
     RECT  31.488 45.493 31.512 46.499 ;
     RECT  60.96 45.733 62.112 46.501 ;
     RECT  34.8 42.803 35.112 46.645 ;
     RECT  36.816 35.891 36.84 46.645 ;
     RECT  6.048 45.685 8.112 46.739 ;
     RECT  10.128 45.155 10.152 46.739 ;
     RECT  16.656 45.973 16.68 46.787 ;
     RECT  28.656 46.069 29.712 46.787 ;
     RECT  42.384 44.965 42.408 46.787 ;
     RECT  57.936 45.731 57.96 46.787 ;
     RECT  56.4 45.347 56.808 46.789 ;
     RECT  29.4 46.787 29.712 47.029 ;
     RECT  31.152 46.645 31.176 47.029 ;
     RECT  29.4 47.029 31.176 47.075 ;
     RECT  48.288 46.069 48.504 47.075 ;
     RECT  60.336 46.501 62.112 47.075 ;
     RECT  18.192 44.243 18.912 47.123 ;
     RECT  43.776 46.069 44.472 47.123 ;
     RECT  34.8 46.645 36.84 47.269 ;
     RECT  34.8 47.269 36.984 47.315 ;
     RECT  40.2 42.227 40.512 47.317 ;
     RECT  60.336 47.075 60.744 47.363 ;
     RECT  48.48 47.075 48.504 47.507 ;
     RECT  24 42.227 24.312 47.701 ;
     RECT  18.6 47.123 18.912 47.749 ;
     RECT  13.2 45.731 14.232 47.797 ;
     RECT  38.736 42.709 38.76 47.845 ;
     RECT  40.2 47.317 40.632 47.845 ;
     RECT  26.976 44.725 27 47.891 ;
     RECT  38.736 47.845 40.632 47.891 ;
     RECT  60.432 47.363 60.744 47.891 ;
     RECT  11.856 46.741 11.88 47.939 ;
     RECT  60.432 47.891 60.456 48.083 ;
     RECT  13.2 47.797 14.76 48.133 ;
     RECT  7.8 46.739 8.112 48.229 ;
     RECT  13.104 48.133 14.76 48.373 ;
     RECT  44.064 47.123 44.472 48.419 ;
     RECT  45.6 45.541 46.68 48.419 ;
     RECT  7.632 48.229 8.112 48.421 ;
     RECT  24 47.701 25.176 48.515 ;
     RECT  34.8 47.315 35.976 48.661 ;
     RECT  36.96 47.315 36.984 48.661 ;
     RECT  44.064 48.419 44.376 48.755 ;
     RECT  18.6 47.749 19.656 48.805 ;
     RECT  34.8 48.661 36.984 48.805 ;
     RECT  18.6 48.805 19.992 48.851 ;
     RECT  13.104 48.373 14.808 48.899 ;
     RECT  17.088 47.557 17.112 48.997 ;
     RECT  51 46.307 52.824 49.043 ;
     RECT  17.088 48.997 17.352 49.187 ;
     RECT  39.312 47.891 40.632 49.187 ;
     RECT  10.944 48.997 10.968 49.333 ;
     RECT  19.968 48.851 19.992 49.333 ;
     RECT  10.944 49.333 11.352 49.379 ;
     RECT  19.968 49.333 20.52 49.379 ;
     RECT  17.088 49.187 17.208 49.429 ;
     RECT  2.4 39.203 2.712 49.477 ;
     RECT  24 48.515 24.312 49.477 ;
     RECT  4.272 48.949 4.296 49.523 ;
     RECT  44.064 48.755 44.088 49.525 ;
     RECT  55.248 45.877 55.272 49.525 ;
     RECT  61.8 47.075 62.112 49.525 ;
     RECT  16.608 49.429 17.208 49.571 ;
     RECT  55.008 49.525 55.272 49.571 ;
     RECT  51 49.043 52.056 50.051 ;
     RECT  18.6 48.851 18.912 50.101 ;
     RECT  34.8 48.805 37.416 50.147 ;
     RECT  20.496 49.379 20.52 50.195 ;
     RECT  56.4 46.789 57.048 50.245 ;
     RECT  24 49.477 24.408 50.293 ;
     RECT  17.136 49.571 17.208 50.485 ;
     RECT  48.72 50.005 48.744 50.581 ;
     RECT  17.136 50.485 17.592 50.819 ;
     RECT  17.568 50.819 17.592 50.867 ;
     RECT  51 50.051 51.576 50.915 ;
     RECT  45.6 48.419 46.632 50.917 ;
     RECT  43.92 49.525 44.088 50.963 ;
     RECT  2.4 49.477 2.808 51.059 ;
     RECT  55.008 49.571 55.032 51.109 ;
     RECT  56.4 50.245 57.432 51.109 ;
     RECT  13.2 48.899 14.808 51.301 ;
     RECT  29.4 47.075 30.264 51.301 ;
     RECT  29.4 51.301 30.744 51.347 ;
     RECT  55.008 51.109 57.432 51.347 ;
     RECT  61.248 49.525 62.112 51.349 ;
     RECT  11.328 49.379 11.352 51.395 ;
     RECT  45.264 50.917 46.632 51.395 ;
     RECT  6.048 46.739 6.072 51.397 ;
     RECT  7.536 48.421 8.112 51.397 ;
     RECT  55.008 51.347 56.904 51.731 ;
     RECT  61.248 51.349 62.328 51.779 ;
     RECT  24 50.293 25.224 51.781 ;
     RECT  45.6 51.395 46.632 51.877 ;
     RECT  61.248 51.779 62.112 51.923 ;
     RECT  18.6 50.101 19.032 51.925 ;
     RECT  43.92 50.963 43.944 51.925 ;
     RECT  48 50.581 48.744 51.925 ;
     RECT  39.312 49.187 40.512 51.973 ;
     RECT  6.048 51.397 8.112 52.067 ;
     RECT  13.104 51.301 14.808 52.163 ;
     RECT  55.008 51.731 56.808 52.259 ;
     RECT  24 51.781 25.368 52.357 ;
     RECT  21.6 46.165 21.624 52.405 ;
     RECT  21.264 52.405 21.624 52.451 ;
     RECT  33.12 51.637 33.144 52.499 ;
     RECT  43.92 51.925 44.28 52.501 ;
     RECT  45.6 51.877 46.824 52.501 ;
     RECT  18.6 51.925 19.896 52.547 ;
     RECT  24 52.357 25.944 52.547 ;
     RECT  36.96 50.147 37.416 52.547 ;
     RECT  39.312 51.973 41.448 52.547 ;
     RECT  43.92 52.501 46.872 52.547 ;
     RECT  48 51.925 49.704 52.547 ;
     RECT  13.2 52.163 14.808 52.549 ;
     RECT  51 50.915 51.48 53.027 ;
     RECT  44.16 52.547 46.872 53.029 ;
     RECT  7.536 52.067 8.112 53.075 ;
     RECT  21.264 52.451 21.288 53.075 ;
     RECT  34.8 50.147 35.976 53.075 ;
     RECT  44.16 53.029 47.64 53.219 ;
     RECT  44.16 53.219 47.256 53.267 ;
     RECT  27.312 53.413 27.336 53.555 ;
     RECT  48.72 52.547 49.704 53.605 ;
     RECT  51 53.027 51.312 53.605 ;
     RECT  42.912 52.069 42.936 53.747 ;
     RECT  54.288 52.981 54.312 53.747 ;
     RECT  30.72 51.347 30.744 53.843 ;
     RECT  55.776 52.259 56.808 53.941 ;
     RECT  6.048 52.067 6.072 54.085 ;
     RECT  25.92 52.547 25.944 54.085 ;
     RECT  13.2 52.549 15.432 54.323 ;
     RECT  14.688 54.323 15.432 54.419 ;
     RECT  10.08 54.373 10.104 54.611 ;
     RECT  44.208 53.267 47.256 54.755 ;
     RECT  48.72 53.605 51.312 54.755 ;
     RECT  52.464 52.981 52.488 54.851 ;
     RECT  48.72 54.755 49.992 54.899 ;
     RECT  29.4 51.347 29.712 54.901 ;
     RECT  58.944 52.357 58.968 54.949 ;
     RECT  58.944 54.949 59.16 54.995 ;
     RECT  6.048 54.085 6.36 55.283 ;
     RECT  14.688 54.419 15.24 55.331 ;
     RECT  21.072 55.189 21.096 55.331 ;
     RECT  0.192 33.829 0.216 55.379 ;
     RECT  22.896 55.333 22.92 55.523 ;
     RECT  54.96 53.941 56.808 55.763 ;
     RECT  51 54.755 51.312 55.765 ;
     RECT  18.6 52.547 19.704 55.813 ;
     RECT  36.96 52.547 36.984 55.813 ;
     RECT  29.28 54.901 29.712 55.907 ;
     RECT  60.432 54.661 60.456 55.907 ;
     RECT  17.04 55.813 19.704 56.147 ;
     RECT  54.96 55.763 54.984 56.243 ;
     RECT  25.92 54.085 26.184 56.389 ;
     RECT  45.6 54.755 47.256 56.533 ;
     RECT  48.864 54.899 49.992 56.533 ;
     RECT  36.96 55.813 37.08 56.723 ;
     RECT  34.8 53.075 35.112 56.773 ;
     RECT  13.2 54.323 13.512 56.821 ;
     RECT  14.688 55.331 14.808 56.821 ;
     RECT  25.92 56.389 26.232 56.821 ;
     RECT  24 52.547 24.504 56.869 ;
     RECT  27.84 57.013 27.864 57.061 ;
     RECT  33.072 56.341 33.096 57.107 ;
     RECT  25.776 56.821 26.232 57.203 ;
     RECT  6.048 55.283 6.072 57.205 ;
     RECT  6.048 57.205 6.264 57.251 ;
     RECT  18 56.147 19.704 57.349 ;
     RECT  24 56.869 24.552 57.349 ;
     RECT  25.776 57.203 25.8 57.349 ;
     RECT  18 57.349 20.52 57.395 ;
     RECT  36.96 56.723 36.984 57.635 ;
     RECT  59.136 54.995 59.16 57.635 ;
     RECT  27.744 57.061 27.864 57.779 ;
     RECT  44.208 54.755 44.232 57.829 ;
     RECT  45.6 56.533 49.992 57.829 ;
     RECT  44.208 57.829 49.992 57.875 ;
     RECT  44.208 57.875 48.888 57.971 ;
     RECT  53.712 57.733 53.736 58.019 ;
     RECT  13.2 56.821 14.808 58.115 ;
     RECT  12 57.829 12.024 58.117 ;
     RECT  4.224 56.917 4.248 58.163 ;
     RECT  24 57.349 25.8 58.211 ;
     RECT  12 58.117 12.072 58.357 ;
     RECT  6.24 57.251 6.264 58.403 ;
     RECT  24 58.211 24.744 58.405 ;
     RECT  29.4 55.907 29.712 58.405 ;
     RECT  25.776 58.211 25.8 58.451 ;
     RECT  18 57.395 18.912 58.453 ;
     RECT  18 58.453 19.032 58.643 ;
     RECT  23.904 58.405 24.744 58.645 ;
     RECT  11.712 58.357 12.072 58.739 ;
     RECT  45.36 57.971 48.888 58.787 ;
     RECT  32.448 57.973 32.472 58.883 ;
     RECT  48.864 58.787 48.888 58.883 ;
     RECT  29.28 58.405 29.712 58.933 ;
     RECT  51 55.765 51.576 58.979 ;
     RECT  15.984 58.021 16.008 59.077 ;
     RECT  15.984 59.077 16.632 59.123 ;
     RECT  20.496 57.395 20.52 59.123 ;
     RECT  44.208 57.971 44.232 59.123 ;
     RECT  45.36 58.787 47.832 59.123 ;
     RECT  23.664 58.645 24.744 59.171 ;
     RECT  29.184 58.933 29.712 59.173 ;
     RECT  46.992 59.123 47.832 59.267 ;
     RECT  33.072 59.173 33.096 59.363 ;
     RECT  56.4 55.763 56.808 59.509 ;
     RECT  45.36 59.123 46.008 59.555 ;
     RECT  23.904 59.171 24.744 59.603 ;
     RECT  14.784 58.115 14.808 59.699 ;
     RECT  24 59.603 24.744 59.747 ;
     RECT  29.088 59.173 29.712 59.843 ;
     RECT  27.84 57.779 27.864 59.987 ;
     RECT  49.968 57.875 49.992 59.987 ;
     RECT  34.8 56.773 35.592 60.085 ;
     RECT  34.8 60.085 36.12 60.371 ;
     RECT  4.368 59.221 4.392 60.373 ;
     RECT  13.2 58.115 13.512 60.373 ;
     RECT  4.128 60.373 4.392 60.419 ;
     RECT  40.2 52.547 41.448 60.419 ;
     RECT  56.4 59.509 57 60.419 ;
     RECT  40.2 60.419 41.352 60.467 ;
     RECT  54.912 59.797 54.936 60.467 ;
     RECT  11.712 58.739 11.736 60.515 ;
     RECT  29.232 59.843 29.712 60.611 ;
     RECT  43.152 59.797 43.176 60.611 ;
     RECT  29.4 60.611 29.712 60.757 ;
     RECT  47.664 59.267 47.832 60.851 ;
     RECT  27.792 60.373 27.816 60.853 ;
     RECT  27.6 60.853 27.816 60.995 ;
     RECT  7.632 53.075 8.112 61.043 ;
     RECT  16.608 59.123 16.632 61.043 ;
     RECT  18 58.643 18.912 61.043 ;
     RECT  29.4 60.757 30.264 61.043 ;
     RECT  34.8 60.371 35.592 61.043 ;
     RECT  4.128 60.419 4.152 61.235 ;
     RECT  30.768 61.189 30.792 61.285 ;
     RECT  9.12 57.109 9.144 61.379 ;
     RECT  27.792 60.995 27.816 61.379 ;
     RECT  30.768 61.285 31.416 61.427 ;
     RECT  31.392 61.427 31.416 61.475 ;
     RECT  29.4 61.043 29.712 61.573 ;
     RECT  37.008 61.525 37.032 61.669 ;
     RECT  13.2 60.373 13.608 61.715 ;
     RECT  40.2 60.467 40.872 61.861 ;
     RECT  42.864 60.901 42.888 61.955 ;
     RECT  39.216 61.861 40.872 62.051 ;
     RECT  37.008 61.669 37.128 62.099 ;
     RECT  45.36 59.555 45.912 62.195 ;
     RECT  37.008 62.099 37.032 62.291 ;
     RECT  40.2 62.051 40.872 62.291 ;
     RECT  45.456 62.195 45.912 62.291 ;
     RECT  29.088 61.573 29.712 62.435 ;
     RECT  47.808 60.851 47.832 62.435 ;
     RECT  2.4 51.059 2.712 62.649 ;
     RECT  7.8 61.043 8.112 62.649 ;
     RECT  13.2 61.715 13.512 62.649 ;
     RECT  18.6 61.043 18.912 62.649 ;
     RECT  24 59.747 24.312 62.649 ;
     RECT  29.4 62.435 29.712 62.649 ;
     RECT  34.8 61.043 35.112 62.649 ;
     RECT  40.2 62.291 40.512 62.649 ;
     RECT  45.6 62.291 45.912 62.649 ;
     RECT  51 58.979 51.312 62.649 ;
     RECT  56.4 60.419 56.712 62.649 ;
     RECT  61.8 51.923 62.112 62.649 ;
     RECT  2.4 62.649 2.52 62.663 ;
     RECT  7.8 62.649 7.92 62.663 ;
     RECT  13.2 62.649 13.32 62.663 ;
     RECT  18.6 62.649 18.72 62.663 ;
     RECT  24 62.649 24.12 62.663 ;
     RECT  29.4 62.649 29.52 62.663 ;
     RECT  34.8 62.649 34.92 62.663 ;
     RECT  40.2 62.649 40.32 62.663 ;
     RECT  45.6 62.649 45.72 62.663 ;
     RECT  51 62.649 51.12 62.663 ;
     RECT  56.4 62.649 56.52 62.663 ;
     RECT  61.8 62.649 61.92 62.663 ;
     RECT  24.312 7.381 25.392 8.675 ;
     RECT  8.112 8.245 9.6 8.965 ;
     RECT  22.776 8.485 24 10.307 ;
     RECT  8.28 8.965 9.6 12.181 ;
     RECT  42.168 9.925 43.536 10.307 ;
     RECT  18.912 10.115 19.08 10.789 ;
     RECT  2.712 10.213 3.984 11.459 ;
     RECT  42.168 10.307 42.744 11.269 ;
     RECT  13.608 10.309 14.832 10.597 ;
     RECT  13.656 10.597 14.832 11.699 ;
     RECT  47.928 10.741 49.248 13.523 ;
     RECT  18.912 10.789 20.352 12.179 ;
     RECT  28.56 10.883 28.608 12.325 ;
     RECT  35.112 11.509 36.096 12.563 ;
     RECT  42.144 11.939 42.72 13.429 ;
     RECT  10.248 11.941 11.28 12.035 ;
     RECT  24.312 11.987 25.296 12.995 ;
     RECT  8.28 12.181 9.36 12.227 ;
     RECT  8.112 12.227 9.36 14.773 ;
     RECT  35.112 12.563 35.88 12.901 ;
     RECT  42.744 12.901 43.872 13.715 ;
     RECT  24.312 12.995 24.408 14.389 ;
     RECT  6.696 13.045 7.8 14.867 ;
     RECT  53.304 13.093 54.816 13.621 ;
     RECT  49.272 13.139 50.736 13.523 ;
     RECT  56.712 13.141 58.128 17.651 ;
     RECT  47.928 13.523 48.696 13.621 ;
     RECT  53.4 13.621 54.816 14.869 ;
     RECT  34.416 13.859 34.8 14.005 ;
     RECT  33.288 14.005 34.8 15.107 ;
     RECT  5.16 14.197 6.672 14.867 ;
     RECT  54.888 14.197 56.4 16.115 ;
     RECT  50.736 14.243 51 15.349 ;
     RECT  42.144 14.435 42.72 15.589 ;
     RECT  8.232 14.773 9.36 16.835 ;
     RECT  53.4 14.869 54.576 15.443 ;
     RECT  49.56 15.349 51 16.787 ;
     RECT  53.304 15.443 54.576 16.501 ;
     RECT  38.376 15.541 39.84 16.259 ;
     RECT  40.512 15.589 41.712 16.691 ;
     RECT  41.736 15.589 42.72 15.829 ;
     RECT  51.312 15.637 52.32 16.357 ;
     RECT  44.472 15.925 45.6 16.499 ;
     RECT  58.776 16.019 59.064 17.077 ;
     RECT  24.408 16.069 25.632 16.115 ;
     RECT  24.312 16.115 25.632 17.075 ;
     RECT  54.6 16.115 56.4 16.261 ;
     RECT  39.216 16.259 40.2 17.605 ;
     RECT  54.6 16.261 55.728 17.075 ;
     RECT  28.608 16.403 29.04 17.077 ;
     RECT  45.216 16.499 45.6 17.605 ;
     RECT  53.592 16.501 54.576 17.123 ;
     RECT  52.344 16.547 53.568 17.027 ;
     RECT  35.88 16.885 37.152 17.077 ;
     RECT  51.432 17.027 53.568 18.181 ;
     RECT  27.96 17.077 29.04 17.123 ;
     RECT  35.88 17.077 37.008 17.219 ;
     RECT  58.776 17.077 59.856 17.699 ;
     RECT  27.96 17.123 29.4 20.725 ;
     RECT  53.592 17.123 54.168 17.605 ;
     RECT  58.632 17.699 59.856 18.275 ;
     RECT  51.432 18.181 52.704 21.443 ;
     RECT  58.632 18.275 59.304 19.621 ;
     RECT  56.712 20.341 58.032 21.155 ;
     RECT  28.056 20.725 29.4 21.877 ;
     RECT  40.512 20.725 41.52 22.787 ;
     RECT  60.792 21.061 61.8 22.211 ;
     RECT  49.728 21.155 50.16 22.165 ;
     RECT  56.712 21.155 56.808 21.781 ;
     RECT  58.56 21.155 58.608 22.645 ;
     RECT  10.032 21.395 10.992 22.069 ;
     RECT  42.216 21.397 43.632 21.493 ;
     RECT  51.312 21.443 52.704 21.637 ;
     RECT  42.216 21.493 43.344 21.923 ;
     RECT  51.312 21.637 52.56 24.227 ;
     RECT  28.152 21.877 29.4 24.613 ;
     RECT  43.248 21.923 43.344 22.117 ;
     RECT  9.864 22.069 10.992 22.979 ;
     RECT  14.136 22.117 15.264 24.227 ;
     RECT  31.608 22.165 32.976 23.555 ;
     RECT  48.696 22.165 50.16 22.693 ;
     RECT  24.312 22.645 25.584 22.741 ;
     RECT  48.984 22.693 50.16 22.739 ;
     RECT  48.984 22.739 51 24.037 ;
     RECT  45.264 22.787 45.6 23.173 ;
     RECT  9.864 22.979 10.248 24.133 ;
     RECT  6.36 22.981 7.8 27.205 ;
     RECT  44.28 23.173 45.6 24.901 ;
     RECT  21.672 23.557 23.04 23.893 ;
     RECT  42.168 23.701 43.248 25.091 ;
     RECT  18.912 23.845 19.92 26.675 ;
     RECT  21.672 23.893 22.752 24.083 ;
     RECT  19.944 24.037 21.36 26.675 ;
     RECT  48.984 24.037 50.832 24.181 ;
     RECT  21.384 24.083 22.752 24.899 ;
     RECT  22.776 24.083 24 24.899 ;
     RECT  12.216 24.181 13.2 29.939 ;
     RECT  48.984 24.181 50.256 24.323 ;
     RECT  51.312 24.227 52.704 26.773 ;
     RECT  55.176 24.325 56.4 25.139 ;
     RECT  16.776 24.469 17.904 25.331 ;
     RECT  44.376 24.901 45.6 25.573 ;
     RECT  38.232 25.045 39.408 25.475 ;
     RECT  40.512 25.045 41.76 28.691 ;
     RECT  41.784 25.091 43.248 27.877 ;
     RECT  44.472 25.573 45.6 26.963 ;
     RECT  29.712 25.669 30.768 26.243 ;
     RECT  45.912 25.763 46.008 26.773 ;
     RECT  28.128 26.243 28.512 27.013 ;
     RECT  60.408 26.485 61.8 27.875 ;
     RECT  18.912 26.675 21.36 27.973 ;
     RECT  58.608 26.771 58.896 27.877 ;
     RECT  51.312 26.773 52.656 28.547 ;
     RECT  44.376 26.963 45.6 28.453 ;
     RECT  27.48 27.013 28.512 27.059 ;
     RECT  58.92 27.107 60.384 27.875 ;
     RECT  6.408 27.205 7.8 29.075 ;
     RECT  61.104 27.875 61.8 28.837 ;
     RECT  5.112 27.877 6.336 29.075 ;
     RECT  41.784 27.877 43.056 27.925 ;
     RECT  56.856 27.877 58.128 27.923 ;
     RECT  56.712 27.923 58.128 29.123 ;
     RECT  41.784 27.925 42.96 28.691 ;
     RECT  19.848 27.973 21.36 29.989 ;
     RECT  29.712 28.357 30.816 29.651 ;
     RECT  44.376 28.453 45.408 29.795 ;
     RECT  51.312 28.547 52.704 33.011 ;
     RECT  42.192 28.691 42.96 29.605 ;
     RECT  10.824 28.933 11.952 28.979 ;
     RECT  10.824 28.979 12.192 29.939 ;
     RECT  38.568 29.029 39.984 30.611 ;
     RECT  6.36 29.075 7.8 30.805 ;
     RECT  24.312 29.123 24.456 30.613 ;
     RECT  54.312 29.605 55.344 29.747 ;
     RECT  55.368 29.605 56.4 30.229 ;
     RECT  55.296 29.747 55.344 30.709 ;
     RECT  44.376 29.795 45.6 31.189 ;
     RECT  13.056 29.939 13.2 30.805 ;
     RECT  19.848 29.989 21.12 30.277 ;
     RECT  19.944 30.277 21.12 31.091 ;
     RECT  59.304 30.277 60.432 31.811 ;
     RECT  18.912 30.323 19.92 31.091 ;
     RECT  60.456 30.947 61.8 31.811 ;
     RECT  56.712 30.949 57.744 31.141 ;
     RECT  57.768 30.949 59.28 33.635 ;
     RECT  2.712 31.043 2.808 31.765 ;
     RECT  20.976 31.091 21.12 31.285 ;
     RECT  44.376 31.189 45.504 32.195 ;
     RECT  24.456 31.333 25.68 32.291 ;
     RECT  50.544 31.379 50.88 32.437 ;
     RECT  2.712 31.765 3.84 32.483 ;
     RECT  44.376 32.195 45.6 34.597 ;
     RECT  24.312 32.291 25.68 32.771 ;
     RECT  35.544 32.437 37.056 33.587 ;
     RECT  2.712 32.483 3.576 33.397 ;
     RECT  55.488 32.483 56.4 33.589 ;
     RECT  24.312 32.771 24.504 33.253 ;
     RECT  22.776 32.965 24 33.779 ;
     RECT  51.312 33.011 51.432 34.117 ;
     RECT  33.624 33.445 34.8 34.499 ;
     RECT  55.272 33.589 56.4 34.259 ;
     RECT  59.232 33.635 59.256 34.597 ;
     RECT  22.752 33.779 24 34.501 ;
     RECT  8.76 33.829 9.84 33.971 ;
     RECT  55.248 34.259 56.4 34.501 ;
     RECT  34.704 34.499 34.8 35.269 ;
     RECT  22.152 34.501 24 35.269 ;
     RECT  40.512 34.501 41.904 37.091 ;
     RECT  55.248 34.501 55.968 34.741 ;
     RECT  53.64 34.741 54.912 35.699 ;
     RECT  54.936 34.741 55.968 35.699 ;
     RECT  22.152 35.269 23.664 35.459 ;
     RECT  23.328 35.459 23.664 36.661 ;
     RECT  13.512 35.555 13.704 36.997 ;
     RECT  53.64 35.699 55.968 35.747 ;
     RECT  51.312 35.747 51.432 36.421 ;
     RECT  53.64 35.747 56.4 36.517 ;
     RECT  12.024 35.845 13.2 37.909 ;
     RECT  36.84 35.891 37.176 36.997 ;
     RECT  44.376 35.891 45.6 43.861 ;
     RECT  51.312 36.421 52.752 37.813 ;
     RECT  29.712 36.469 30.96 37.571 ;
     RECT  54.168 36.517 56.4 36.757 ;
     RECT  54.984 36.757 56.4 37.573 ;
     RECT  59.232 36.803 59.328 37.573 ;
     RECT  36.84 36.997 38.016 39.251 ;
     RECT  38.04 36.997 39.36 38.195 ;
     RECT  41.928 36.997 43.392 37.091 ;
     RECT  55.032 37.573 56.4 39.347 ;
     RECT  57 37.573 58.128 38.245 ;
     RECT  58.152 37.573 59.328 38.149 ;
     RECT  8.112 37.765 9.216 39.731 ;
     RECT  51.312 37.813 52.56 38.195 ;
     RECT  51.312 38.195 52.752 39.203 ;
     RECT  58.008 38.291 59.04 39.395 ;
     RECT  53.832 38.435 55.008 38.579 ;
     RECT  56.712 38.435 57.744 42.803 ;
     RECT  53.592 38.579 55.008 39.347 ;
     RECT  12.528 38.675 13.2 39.637 ;
     RECT  59.544 38.677 60.96 39.923 ;
     RECT  51.312 39.203 52.8 41.797 ;
     RECT  18.912 39.349 19.968 43.763 ;
     RECT  58.008 39.395 59.52 39.923 ;
     RECT  48.72 39.443 48.96 40.405 ;
     RECT  14.328 39.781 15.792 43.283 ;
     RECT  58.008 39.923 58.104 41.077 ;
     RECT  40.512 40.165 41.664 40.837 ;
     RECT  46.776 40.405 47.904 40.595 ;
     RECT  47.928 40.405 48.96 40.883 ;
     RECT  31.488 40.595 32.448 41.075 ;
     RECT  45.912 40.595 47.904 41.173 ;
     RECT  47.928 40.883 48.456 41.557 ;
     RECT  31.488 41.075 31.56 41.557 ;
     RECT  39.84 41.075 40.2 41.557 ;
     RECT  45.912 41.173 47.28 41.557 ;
     RECT  10.584 41.509 12.096 41.555 ;
     RECT  58.104 41.509 59.088 42.227 ;
     RECT  12.12 41.555 13.2 43.331 ;
     RECT  5.736 41.557 6.768 42.227 ;
     RECT  6.792 41.557 7.8 42.227 ;
     RECT  27.624 41.557 28.992 41.603 ;
     RECT  31.488 41.557 31.536 41.845 ;
     RECT  39.048 41.557 40.2 42.515 ;
     RECT  45.912 41.557 47.232 43.427 ;
     RECT  54.024 41.749 55.344 42.613 ;
     RECT  51.312 41.797 52.56 42.709 ;
     RECT  29.712 41.845 30.768 41.987 ;
     RECT  29.712 41.987 31.536 42.371 ;
     RECT  47.256 42.227 48.288 43.427 ;
     RECT  57.96 42.227 59.088 42.755 ;
     RECT  29.712 42.371 30.84 43.285 ;
     RECT  39.024 42.515 40.2 42.709 ;
     RECT  54.12 42.613 55.344 43.283 ;
     RECT  38.76 42.709 40.2 47.845 ;
     RECT  51.312 42.709 52.512 43.571 ;
     RECT  57.96 42.755 58.872 43.861 ;
     RECT  56.712 42.803 57.936 44.773 ;
     RECT  14.328 43.283 14.376 43.285 ;
     RECT  54.024 43.283 55.344 43.811 ;
     RECT  29.712 43.285 30.816 44.483 ;
     RECT  12.672 43.331 13.2 44.437 ;
     RECT  45.912 43.427 46.632 44.437 ;
     RECT  51.312 43.571 52.56 45.253 ;
     RECT  18.912 43.763 20.352 44.147 ;
     RECT  58.68 43.861 58.872 43.909 ;
     RECT  22.968 44.341 24 45.587 ;
     RECT  55.968 44.483 56.4 45.877 ;
     RECT  43.488 44.579 43.776 44.965 ;
     RECT  44.376 44.675 45.6 46.069 ;
     RECT  42.408 44.965 43.776 46.787 ;
     RECT  56.808 45.347 57.936 46.787 ;
     RECT  12.672 45.731 13.2 46.741 ;
     RECT  55.272 45.877 56.4 49.571 ;
     RECT  16.68 45.973 18.192 46.787 ;
     RECT  44.472 46.069 45.6 48.419 ;
     RECT  20.52 46.165 21.6 46.211 ;
     RECT  29.712 46.645 31.152 47.029 ;
     RECT  7.632 46.739 7.8 48.229 ;
     RECT  11.88 46.741 13.2 47.939 ;
     RECT  17.088 46.787 18.192 47.123 ;
     RECT  56.808 46.787 57.048 46.789 ;
     RECT  60.744 47.075 61.8 47.891 ;
     RECT  17.088 47.123 18.6 47.557 ;
     RECT  35.976 47.315 36.96 48.661 ;
     RECT  17.112 47.557 18.6 48.997 ;
     RECT  60.456 47.891 61.8 48.083 ;
     RECT  13.104 47.939 13.2 48.133 ;
     RECT  61.248 48.083 61.8 49.525 ;
     RECT  44.376 48.419 45.6 48.755 ;
     RECT  6.072 48.421 7.536 51.397 ;
     RECT  24.312 48.515 24.408 49.477 ;
     RECT  44.088 48.755 45.6 50.917 ;
     RECT  18.912 48.851 19.968 49.379 ;
     RECT  17.352 48.997 18.6 49.187 ;
     RECT  17.208 49.187 18.6 50.485 ;
     RECT  20.52 49.333 21.6 50.195 ;
     RECT  18.912 49.379 20.496 50.101 ;
     RECT  2.808 49.477 4.272 49.523 ;
     RECT  55.032 49.571 56.4 51.109 ;
     RECT  19.032 50.101 20.496 50.195 ;
     RECT  35.976 50.147 36.96 53.075 ;
     RECT  17.592 50.485 18.6 50.867 ;
     RECT  46.632 50.581 48 51.877 ;
     RECT  44.088 50.917 45.264 50.963 ;
     RECT  43.944 50.963 45.264 51.395 ;
     RECT  29.712 51.347 30.72 53.843 ;
     RECT  43.944 51.395 45.6 51.925 ;
     RECT  46.824 51.877 48 52.501 ;
     RECT  44.28 51.925 45.6 52.501 ;
     RECT  49.704 51.925 51 53.605 ;
     RECT  6.072 52.067 7.536 53.075 ;
     RECT  41.448 52.069 42.912 53.747 ;
     RECT  42.936 52.069 43.92 52.547 ;
     RECT  55.008 52.259 55.776 52.981 ;
     RECT  19.896 52.405 21.264 52.547 ;
     RECT  46.872 52.501 48 52.547 ;
     RECT  24.504 52.547 25.92 56.821 ;
     RECT  42.936 52.547 44.16 53.267 ;
     RECT  46.872 52.547 48.72 53.029 ;
     RECT  51.48 52.981 52.464 53.027 ;
     RECT  54.312 52.981 55.776 53.747 ;
     RECT  51.312 53.027 52.464 54.851 ;
     RECT  47.64 53.029 48.72 53.219 ;
     RECT  6.072 53.075 7.632 54.085 ;
     RECT  47.256 53.219 48.72 54.899 ;
     RECT  42.936 53.267 44.208 53.747 ;
     RECT  25.944 53.413 27.312 53.555 ;
     RECT  25.944 53.555 26.184 54.085 ;
     RECT  54.96 53.747 55.776 53.941 ;
     RECT  6.36 54.085 7.632 55.283 ;
     RECT  13.512 54.323 14.688 56.821 ;
     RECT  58.968 54.661 60.432 54.949 ;
     RECT  60.456 54.661 61.8 55.907 ;
     RECT  44.232 54.755 45.6 57.829 ;
     RECT  49.992 54.755 51 59.987 ;
     RECT  51.312 54.851 51.576 55.765 ;
     RECT  59.16 54.949 60.432 55.907 ;
     RECT  19.704 55.189 21.072 55.331 ;
     RECT  22.92 55.333 24 55.523 ;
     RECT  54.984 55.763 56.4 56.243 ;
     RECT  35.592 56.773 36.96 57.635 ;
     RECT  24.504 56.821 25.776 56.869 ;
     RECT  24.552 56.869 25.776 57.349 ;
     RECT  2.712 56.917 4.224 58.163 ;
     RECT  26.232 57.061 27.744 57.203 ;
     RECT  8.112 57.109 9.12 61.379 ;
     RECT  6.264 57.205 7.632 58.403 ;
     RECT  18.912 57.395 20.496 58.453 ;
     RECT  12.024 57.829 13.2 58.117 ;
     RECT  48.888 57.875 49.968 58.883 ;
     RECT  44.232 57.971 45.36 59.123 ;
     RECT  14.808 58.021 15.984 59.123 ;
     RECT  13.512 58.115 14.784 59.699 ;
     RECT  12.072 58.117 13.2 58.739 ;
     RECT  24.744 58.211 25.776 58.451 ;
     RECT  27.864 58.405 29.28 58.933 ;
     RECT  19.032 58.453 20.496 58.643 ;
     RECT  11.736 58.739 13.2 60.515 ;
     RECT  47.832 58.787 48.864 58.883 ;
     RECT  27.864 58.933 29.184 59.173 ;
     RECT  16.632 59.077 18 61.043 ;
     RECT  46.008 59.123 46.992 59.267 ;
     RECT  27.864 59.173 29.088 59.843 ;
     RECT  13.512 59.699 13.608 60.373 ;
     RECT  54.936 59.797 56.4 60.467 ;
     RECT  27.864 59.843 29.232 59.987 ;
     RECT  27.84 59.987 29.232 60.373 ;
     RECT  2.712 60.373 4.128 61.235 ;
     RECT  27.816 60.373 29.232 60.611 ;
     RECT  27.816 60.611 29.4 61.379 ;
     RECT  29.712 61.043 30.264 61.189 ;
     RECT  29.712 61.189 30.768 61.427 ;
     RECT  29.088 61.379 29.4 61.573 ;
  END
END ot_hbm_native_bounded_cdc
END LIBRARY
